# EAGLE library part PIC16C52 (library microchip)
MICROCONTROLLER

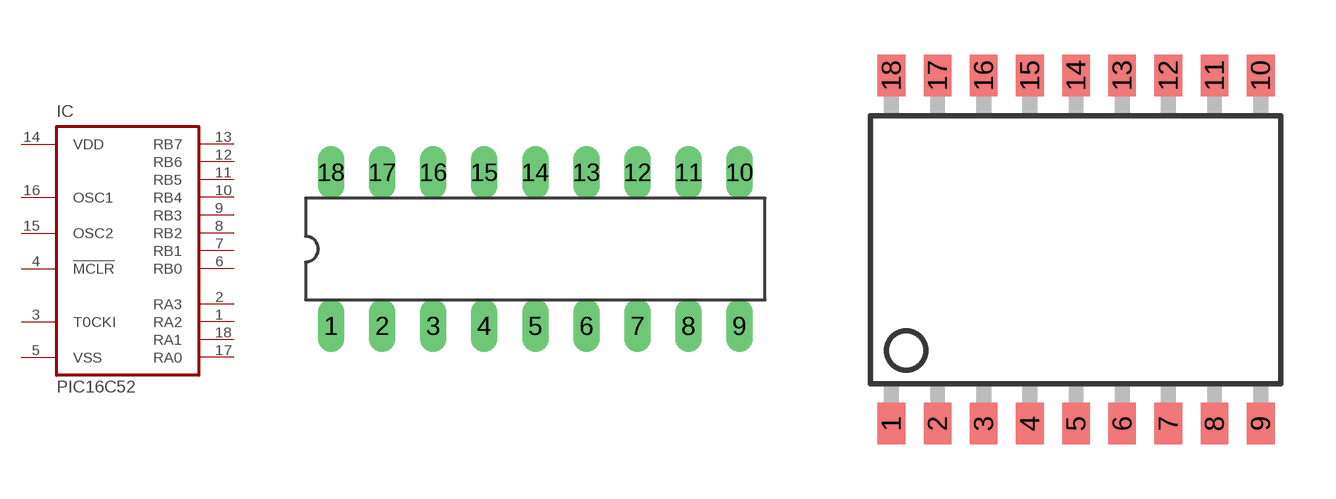
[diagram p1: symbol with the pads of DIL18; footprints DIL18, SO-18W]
Designator prefix IC

## PIC16C52P (OC_FARNELL: unknown; OC_NEWARK: unknown)  [DIL18]
1  RA2
2  RA3
3  T0CKI  in
4  !MCLR  in
5  VSS  pwr
6  RB0
7  RB1
8  RB2
9  RB3
10  RB4
11  RB5
12  RB6
13  RB7
14  VDD  pwr
15  OSC2  out
16  OSC1  in
17  RA0
18  RA1

## PIC16C52JW (OC_FARNELL: unknown; OC_NEWARK: unknown)  [DIL18]
Pads as for DIL18

## PIC16C52SO (OC_FARNELL: unknown; OC_NEWARK: unknown)  [SO-18W]
Pads as for DIL18

## Footprint DIL18 (pad centres in mm)
Dual In Line package type P
drill 0.813 long: 1 -10.16,-3.81; 2 -7.62,-3.81; 3 -5.08,-3.81; 4 -2.54,-3.81; 5 0,-3.81; 6 2.54,-3.81; 7 5.08,-3.81; 8 7.62,-3.81; 9 10.16,-3.81; 10 10.16,3.81; 11 7.62,3.81; 12 5.08,3.81; 13 2.54,3.81; 14 0,3.81; 15 -2.54,3.81; 16 -5.08,3.81; 17 -7.62,3.81; 18 -10.16,3.81

## Footprint SO-18W (pad centres in mm)
Small Outline Wide Plastic Gull Wing 300-mil body, package type SO
smd 0.762 x 1.143: 1 -5.08,-4.788; 2 -3.81,-4.788; 3 -2.54,-4.788; 4 -1.27,-4.788; 5 0,-4.788; 6 1.27,-4.788; 7 2.54,-4.788; 8 3.81,-4.788; 9 5.08,-4.788; 10 5.08,4.788; 11 3.81,4.788; 12 2.54,4.788; 13 1.27,4.788; 14 0,4.788; 15 -1.27,4.788; 16 -2.54,4.788; 17 -3.81,4.788; 18 -5.08,4.788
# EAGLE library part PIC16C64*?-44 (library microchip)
MICROCONTROLLER

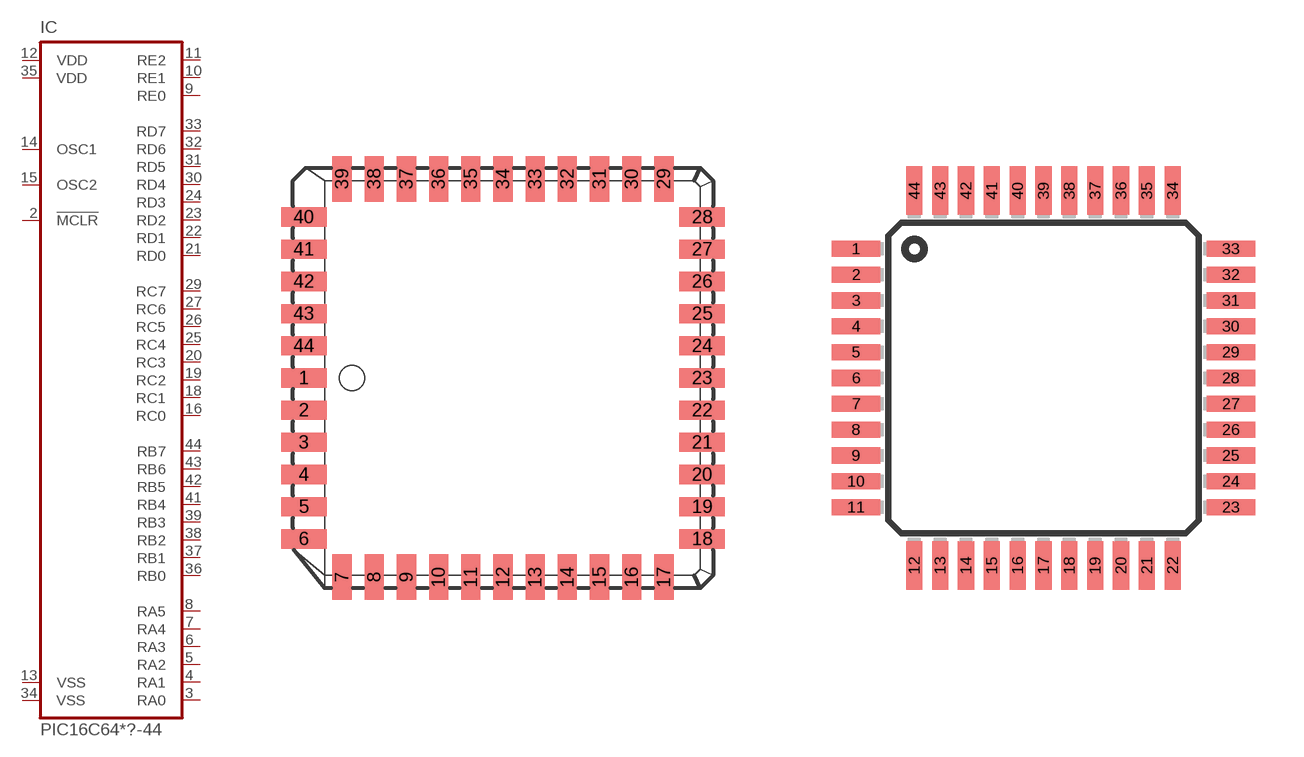
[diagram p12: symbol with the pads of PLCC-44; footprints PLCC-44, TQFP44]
Designator prefix IC

## PIC16C64L-44 (MF: MICROCHIP; MPN: PIC16C64A-20/L; OC_FARNELL: 9759646; OC_NEWARK: 23C4099)  [PLCC-44]
1  NC  nc
2  !MCLR  in
3  RA0
4  RA1
5  RA2
6  RA3
7  RA4
8  RA5
9  RE0
10  RE1
11  RE2
12  VDD  pwr
13  VSS  pwr
14  OSC1  in
15  OSC2  out
16  RC0
17  NC  nc
18  RC1
19  RC2
20  RC3
21  RD0
22  RD1
23  RD2
24  RD3
25  RC4
26  RC5
27  RC6
28  NC  nc
29  RC7
30  RD4
31  RD5
32  RD6
33  RD7
34  VSS  pwr
35  VDD  pwr
36  RB0
37  RB1
38  RB2
39  RB3
40  NC  nc
41  RB4
42  RB5
43  RB6
44  RB7

## PIC16C64PT-44 (OC_FARNELL: unknown; OC_NEWARK: unknown)  [TQFP44]
1  RC7
2  RD4
3  RD5
4  RD6
5  RD7
6  VSS  pwr
7  VDD  pwr
8  RB0
9  RB1
10  RB2
11  RB3
12  NC  nc
13  NC  nc
14  RB4
15  RB5
16  RB6
17  RB7
18  !MCLR  in
19  RA0
20  RA1
21  RA2
22  RA3
23  RA4
24  RA5
25  RE0
26  RE1
27  RE2
28  VDD  pwr
29  VSS  pwr
30  OSC1  in
31  OSC2  out
32  RC0
33  NC  nc
34  NC  nc
35  RC1
36  RC2
37  RC3
38  RD0
39  RD1
40  RD2
41  RD3
42  RC4
43  RC5
44  RC6

## Footprint PLCC-44 (pad centres in mm)
PLASTIC LEADED CHIP CARRIER square, package type L
smd 1.8 x 0.76: 1 -7.86,0; 2 -7.86,-1.27; 3 -7.86,-2.54; 4 -7.86,-3.81; 5 -7.86,-5.08; 6 -7.86,-6.35; 18 7.86,-6.35; 19 7.86,-5.08; 20 7.86,-3.81; 21 7.86,-2.54; 22 7.86,-1.27; 23 7.86,0; 24 7.86,1.27; 25 7.86,2.54; 26 7.86,3.81; 27 7.86,5.08; 28 7.86,6.35; 40 -7.86,6.35; 41 -7.86,5.08; 42 -7.86,3.81; 43 -7.86,2.54; 44 -7.86,1.27
smd 0.76 x 1.8: 7 -6.35,-7.86; 8 -5.08,-7.86; 9 -3.81,-7.86; 10 -2.54,-7.86; 11 -1.27,-7.86; 12 0,-7.86; 13 1.27,-7.86; 14 2.54,-7.86; 15 3.81,-7.86; 16 5.08,-7.86; 17 6.35,-7.86; 29 6.35,7.86; 30 5.08,7.86; 31 3.81,7.86; 32 2.54,7.86; 33 1.27,7.86; 34 0,7.86; 35 -1.27,7.86; 36 -2.54,7.86; 37 -3.81,7.86; 38 -5.08,7.86; 39 -6.35,7.86

## Footprint TQFP44 (pad centres in mm)
Thin Quad Flat Pack package type TQ
smd 1.5 x 0.5: 1 -5.8,4; 2 -5.8,3.2; 3 -5.8,2.4; 4 -5.8,1.6; 5 -5.8,0.8; 6 -5.8,0; 7 -5.8,-0.8; 8 -5.8,-1.6; 9 -5.8,-2.4; 10 -5.8,-3.2; 11 -5.8,-4; 23 5.8,-4; 24 5.8,-3.2; 25 5.8,-2.4; 26 5.8,-1.6; 27 5.8,-0.8; 28 5.8,0; 29 5.8,0.8; 30 5.8,1.6; 31 5.8,2.4; 32 5.8,3.2; 33 5.8,4
smd 0.5 x 1.5: 12 -4,-5.8; 13 -3.2,-5.8; 14 -2.4,-5.8; 15 -1.6,-5.8; 16 -0.8,-5.8; 17 0,-5.8; 18 0.8,-5.8; 19 1.6,-5.8; 20 2.4,-5.8; 21 3.2,-5.8; 22 4,-5.8; 34 4,5.8; 35 3.2,5.8; 36 2.4,5.8; 37 1.6,5.8; 38 0.8,5.8; 39 0,5.8; 40 -0.8,5.8; 41 -1.6,5.8; 42 -2.4,5.8; 43 -3.2,5.8; 44 -4,5.8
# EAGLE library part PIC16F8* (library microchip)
MICROCONTROLLER 8-Bit PIC16F8X Family - CMOS Flash/EEPROM Pin Compatible : PIC16F83, PIC16CR83, PIC16F84A, PIC16CR84 see also PIC16C*

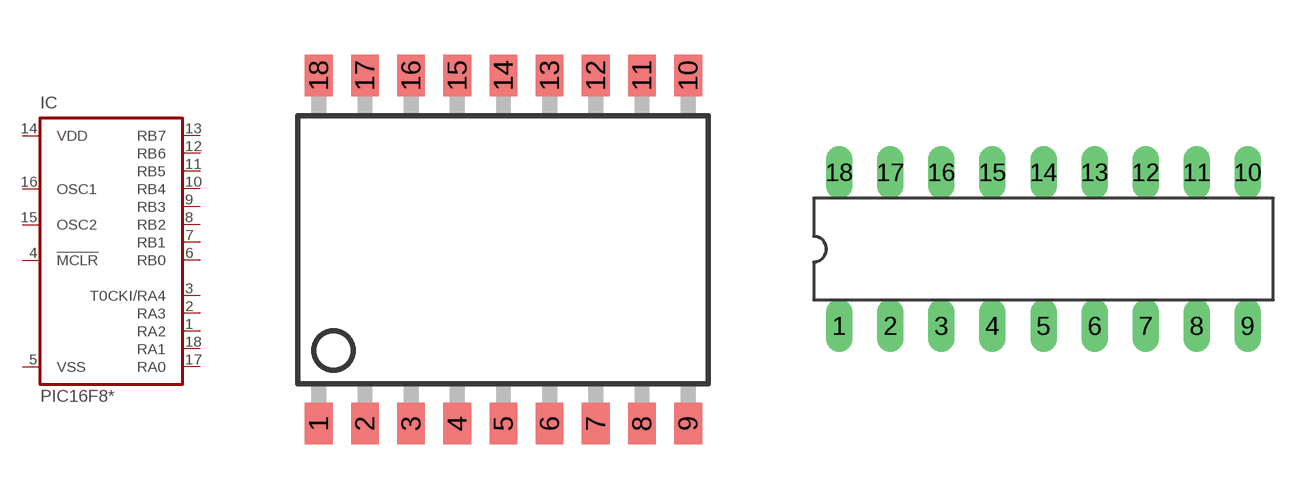
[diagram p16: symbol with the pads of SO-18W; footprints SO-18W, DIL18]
Designator prefix IC

## PIC16F83SO (MF: MICROCHIP; MPN: PIC16F83-04/SO; OC_FARNELL: unknown; OC_NEWARK: 23C4997), PIC16F84ASO (MF: MICROCHIP; MPN: PIC16F84A-04/SO; OC_FARNELL: 9760890; OC_NEWARK: 69K7634)  [SO-18W]
1  RA2
2  RA3
3  T0CKI/RA4
4  !MCLR  in
5  VSS  pwr
6  RB0
7  RB1
8  RB2
9  RB3
10  RB4
11  RB5
12  RB6
13  RB7
14  VDD  pwr
15  OSC2  out
16  OSC1  in
17  RA0
18  RA1

## PIC16F83P (MPN: PIC16F83-04/P; OC_FARNELL: 1084354; OC_NEWARK: 97K7388), PIC16F84AP (MF: MICROCHIP; MPN: PIC16F84A-04I/P; OC_FARNELL: 9760865; OC_NEWARK: 69K7635)  [DIL18]
Pads as for SO-18W

## Footprint SO-18W (pad centres in mm)
Small Outline Wide Plastic Gull Wing 300-mil body, package type SO
smd 0.762 x 1.143: 1 -5.08,-4.788; 2 -3.81,-4.788; 3 -2.54,-4.788; 4 -1.27,-4.788; 5 0,-4.788; 6 1.27,-4.788; 7 2.54,-4.788; 8 3.81,-4.788; 9 5.08,-4.788; 10 5.08,4.788; 11 3.81,4.788; 12 2.54,4.788; 13 1.27,4.788; 14 0,4.788; 15 -1.27,4.788; 16 -2.54,4.788; 17 -3.81,4.788; 18 -5.08,4.788

## Footprint DIL18 (pad centres in mm)
Dual In Line package type P
drill 0.813 long: 1 -10.16,-3.81; 2 -7.62,-3.81; 3 -5.08,-3.81; 4 -2.54,-3.81; 5 0,-3.81; 6 2.54,-3.81; 7 5.08,-3.81; 8 7.62,-3.81; 9 10.16,-3.81; 10 10.16,3.81; 11 7.62,3.81; 12 5.08,3.81; 13 2.54,3.81; 14 0,3.81; 15 -2.54,3.81; 16 -5.08,3.81; 17 -7.62,3.81; 18 -10.16,3.81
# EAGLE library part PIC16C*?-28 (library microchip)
MICROCONTROLLER 8-BitEPROM/ROM-based Pin compatible: PIC16CR62, PIC16C62A, PIC16C63, PIC16CR63 PIC16C66, PIC16C72, PIC16C73A, PIC16C76

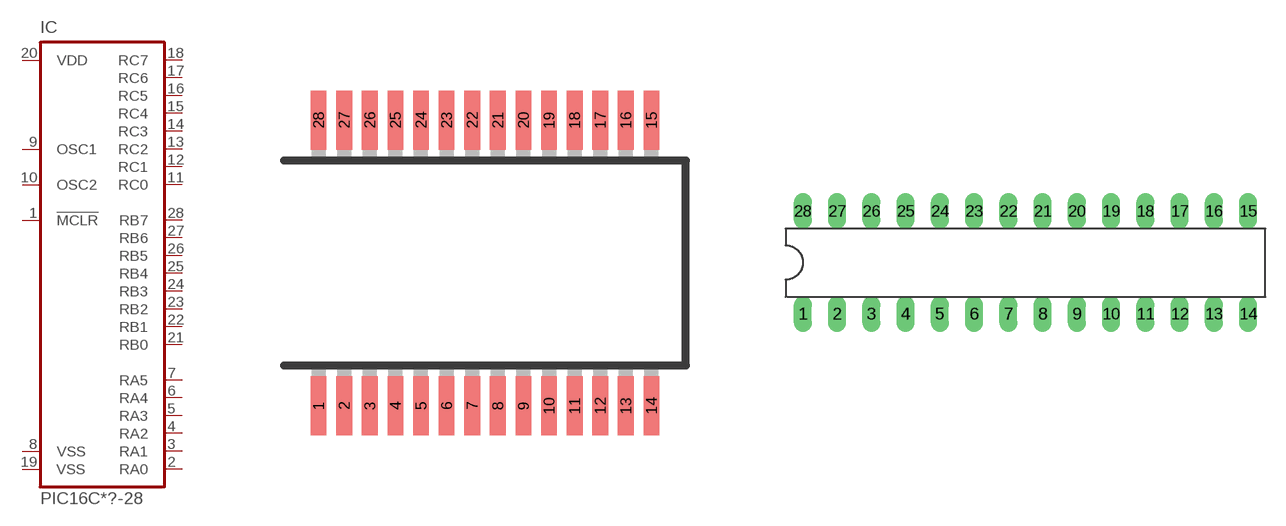
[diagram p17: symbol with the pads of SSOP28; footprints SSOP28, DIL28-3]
Designator prefix IC

## PIC16C62ASS-28 (MF: MICROCHIP; MPN: PIC16C62A-04/SS; OC_FARNELL: unknown; OC_NEWARK: 23C3766), PIC16C63SS-28 (MF: MICROCHIP; MPN: PIC16C63A-04/SS; OC_FARNELL: unknown; OC_NEWARK: 96K3811), PIC16C66SS-28 (OC_FARNELL: unknown; OC_NEWARK: unknown), PIC16C72SS-28 (MF: MICROCHIP; MPN: PIC16C72A-04/SS; OC_FARNELL: unknown; OC_NEWARK: 23C4612), PIC16C73ASS-28 (MPN: PIC16C73B-20I/SS; OC_FARNELL: 1137313; OC_NEWARK: 24M5884), PIC16C76SS-28 (OC_FARNELL: unknown; OC_NEWARK: unknown), PIC16CR62SS-28 (OC_FARNELL: unknown; OC_NEWARK: unknown), PIC16CR63SS-28 (OC_FARNELL: unknown; OC_NEWARK: unknown)  [SSOP28]
1  !MCLR  in
2  RA0
3  RA1
4  RA2
5  RA3
6  RA4
7  RA5
8  VSS  pwr
9  OSC1
10  OSC2
11  RC0
12  RC1
13  RC2
14  RC3
15  RC4
16  RC5
17  RC6
18  RC7
19  VSS  pwr
20  VDD  pwr
21  RB0
22  RB1
23  RB2
24  RB3
25  RB4
26  RB5
27  RB6
28  RB7

## PIC16C62AP-28 (MF: MICROCHIP; MPN: PIC16C62A-10/SP; OC_FARNELL: 9759557; OC_NEWARK: 23C3774), PIC16C63P-28 (MF: MICROCHIP; MPN: PIC16C63-04I/SP; OC_FARNELL: 9759590; OC_NEWARK: 23C4025), PIC16C66P-28 (MF: MICROCHIP; MPN: PIC16C66-04I/SP; OC_FARNELL: 9759735; OC_NEWARK: 23C4276), PIC16C72P-28 (MF: MICROCHIP; MPN: PIC16C72-04/SO; OC_FARNELL: 1196858; OC_NEWARK: 23C4583), PIC16C73AP-28 (MF: MICROCHIP; MPN: PIC16C73A-20I/SP; OC_FARNELL: 1815911; OC_NEWARK: 23C4675), PIC16C76P-28 (MF: MICROCHIP; MPN: PIC16C76-20/SP; OC_FARNELL: 1196859; OC_NEWARK: 12C1934), PIC16CR62P-28 (OC_FARNELL: unknown; OC_NEWARK: unknown), PIC16CR63P-28 (OC_FARNELL: unknown; OC_NEWARK: unknown)  [DIL28-3]
Pads as for SSOP28

## PIC16C62ASO-28 (MF: MICROCHIP; MPN: PIC16C62A-20/SO; OC_FARNELL: 9759573; OC_NEWARK: 23C3782), PIC16C63SO-28 (MPN: PIC16C63-04/SO; OC_FARNELL: 9759581; OC_NEWARK: 97K7237), PIC16C66SO-28 (MPN: PIC16C66-10/SO; OC_FARNELL: 9759727; OC_NEWARK: 97K7254), PIC16C72SO-28 (MF: MICROCHIP; MPN: PIC16C72-04/SO; OC_FARNELL: 9759891; OC_NEWARK: 23C4583), PIC16C73ASO-28 (MPN: PIC16C73A-04/SO; OC_FARNELL: 9759930; OC_NEWARK: 97K7282), PIC16C76SO-28 (MF: MICROCHIP; MPN: PIC16C76-20/SO; OC_FARNELL: unknown; OC_NEWARK: 65K1040), PIC16CR62SO-28 (OC_FARNELL: unknown; OC_NEWARK: unknown), PIC16CR63SO-28 (OC_FARNELL: unknown; OC_NEWARK: unknown)  [SO28W]
Pads as for SSOP28

## PIC16C62PS-28 (MF: MICROCHIP; MPN: PIC16C62B-20/SP; OC_FARNELL: 9759565; OC_NEWARK: 12C1900), PIC16C62APS-28 (MF: MICROCHIP; MPN: PIC16C62A-10/SP; OC_FARNELL: 1818502; OC_NEWARK: 23C3774), PIC16C63PS-28 (MF: MICROCHIP; MPN: PIC16C63-04I/SP; OC_FARNELL: 9759590; OC_NEWARK: 23C4025), PIC16C66PS-28 (MF: MICROCHIP; MPN: PIC16C66-04I/SP; OC_FARNELL: 685999; OC_NEWARK: 23C4276), PIC16C72PS-28 (MF: MICROCHIP; MPN: PIC16C72A-04/SP; OC_FARNELL: 1196858; OC_NEWARK: 12C1924), PIC16C73APS-28 (MF: MICROCHIP; MPN: PIC16C73A-20/SP; OC_FARNELL: 1196850; OC_NEWARK: 69K7069), PIC16C76PS-28 (MF: MICROCHIP; MPN: PIC16C76-04/SP; OC_FARNELL: 1196836; OC_NEWARK: 96K3849), PIC16CR63PS-28 (OC_FARNELL: unknown; OC_NEWARK: unknown)  [DIL28-3]
Pads as for SSOP28

## PIC16C62AJW-28 (MF: MICROCHIP; MPN: PIC16C62A-10/SP; OC_FARNELL: 9759557; OC_NEWARK: 23C3774), PIC16C63JW-28 (MPN: PIC16C63-04/SP; OC_FARNELL: 1084289; OC_NEWARK: 97K7238), PIC16C66JW-28 (MF: MICROCHIP; MPN: PIC16C66/JW; OC_FARNELL: 685999; OC_NEWARK: 96K3820), PIC16C72JW-28 (MF: MICROCHIP; MPN: PIC16C72-20/SP; OC_FARNELL: 1196858; OC_NEWARK: 23C4602), PIC16C73AJW-28 (MPN: PIC16C73A-10/SP; OC_FARNELL: 9759948; OC_NEWARK: 97K7284), PIC16C76JW-28 (MPN: PIC16C76-04/SP; OC_FARNELL: 1196836; OC_NEWARK: 97K7307), PIC16CR62JW-28 (OC_FARNELL: unknown; OC_NEWARK: unknown), PIC16CR63JW-28 (OC_FARNELL: unknown; OC_NEWARK: unknown)  [DIL28-6]
Pads as for SSOP28

## Footprint SSOP28 (pad centres in mm)
Shrink Small Outline Package package type SS
smd 0.4 x 1.5: 1 -4.225,-3.625; 2 -3.575,-3.625; 3 -2.925,-3.625; 4 -2.275,-3.625; 5 -1.625,-3.625; 6 -0.975,-3.625; 7 -0.325,-3.625; 8 0.325,-3.625; 9 0.975,-3.625; 10 1.625,-3.625; 11 2.275,-3.625; 12 2.925,-3.625; 13 3.575,-3.625; 14 4.225,-3.625; 15 4.225,3.625; 16 3.575,3.625; 17 2.925,3.625; 18 2.275,3.625; 19 1.625,3.625; 20 0.975,3.625; 21 0.325,3.625; 22 -0.325,3.625; 23 -0.975,3.625; 24 -1.625,3.625; 25 -2.275,3.625; 26 -2.925,3.625; 27 -3.575,3.625; 28 -4.225,3.625

## Footprint DIL28-3 (pad centres in mm)
Dual In Line package type P
drill 0.813 long: 1 -16.51,-3.81; 2 -13.97,-3.81; 3 -11.43,-3.81; 4 -8.89,-3.81; 5 -6.35,-3.81; 6 -3.81,-3.81; 7 -1.27,-3.81; 8 1.27,-3.81; 9 3.81,-3.81; 10 6.35,-3.81; 11 8.89,-3.81; 12 11.43,-3.81; 13 13.97,-3.81; 14 16.51,-3.81; 15 16.51,3.81; 16 13.97,3.81; 17 11.43,3.81; 18 8.89,3.81; 19 6.35,3.81; 20 3.81,3.81; 21 1.27,3.81; 22 -1.27,3.81; 23 -3.81,3.81; 24 -6.35,3.81; 25 -8.89,3.81; 26 -11.43,3.81; 27 -13.97,3.81; 28 -16.51,3.81

## Footprint SO28W (pad centres in mm)
28-Lead Plastic Small Outline (SO) Wide, 300 mil Body (SOIC) Source: http://ww1.microchip.com/downloads/en/devicedoc/39632c.pdf
smd 0.65 x 1.7: 1 -7.62,-4.78; 2 -6.35,-4.78; 3 -5.08,-4.78; 4 -3.81,-4.78; 5 -2.54,-4.78; 6 -1.27,-4.78; 7 0,-4.78; 8 1.27,-4.78; 9 2.54,-4.78; 10 3.81,-4.78; 11 5.08,-4.78; 12 6.35,-4.78; 13 7.62,-4.78; 14 8.89,-4.78; 15 8.89,4.78; 16 7.62,4.78; 17 6.35,4.78; 18 5.08,4.78; 19 3.81,4.78; 20 2.54,4.78; 21 1.27,4.78; 22 0,4.78; 23 -1.27,4.78; 24 -2.54,4.78; 25 -3.81,4.78; 26 -5.08,4.78; 27 -6.35,4.78; 28 -7.62,4.78

## Footprint DIL28-6 (pad centres in mm)
Dual In Line package type P
drill 0.813 long: 1 -16.51,-7.62; 2 -13.97,-7.62; 3 -11.43,-7.62; 4 -8.89,-7.62; 5 -6.35,-7.62; 6 -3.81,-7.62; 7 -1.27,-7.62; 8 1.27,-7.62; 9 3.81,-7.62; 10 6.35,-7.62; 11 8.89,-7.62; 12 11.43,-7.62; 13 13.97,-7.62; 14 16.51,-7.62; 15 16.51,7.62; 16 13.97,7.62; 17 11.43,7.62; 18 8.89,7.62; 19 6.35,7.62; 20 3.81,7.62; 21 1.27,7.62; 22 -1.27,7.62; 23 -3.81,7.62; 24 -6.35,7.62; 25 -8.89,7.62; 26 -11.43,7.62; 27 -13.97,7.62; 28 -16.51,7.62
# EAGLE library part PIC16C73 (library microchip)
MICROCONTROLLER EPROM/ROM-based

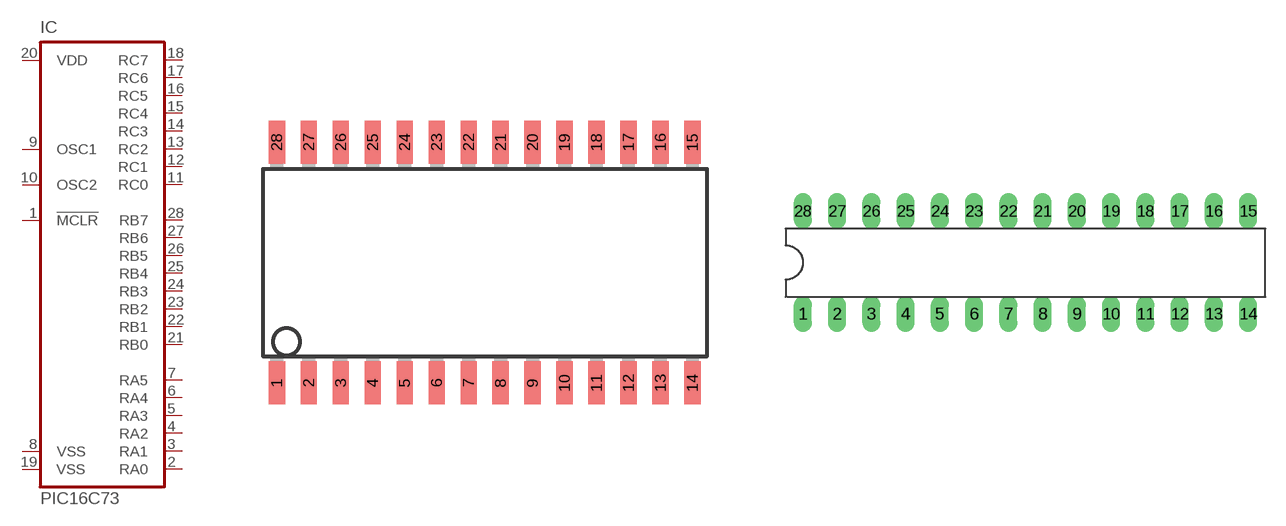
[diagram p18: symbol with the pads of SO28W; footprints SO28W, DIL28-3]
Designator prefix IC

## PIC16C73SO (MF: MICROCHIP; MPN: PIC16C73B-20/SO; OC_FARNELL: 9759999; OC_NEWARK: 12C1926)  [SO28W]
1  !MCLR  in
2  RA0
3  RA1
4  RA2
5  RA3
6  RA4
7  RA5
8  VSS  pwr
9  OSC1
10  OSC2
11  RC0
12  RC1
13  RC2
14  RC3
15  RC4
16  RC5
17  RC6
18  RC7
19  VSS  pwr
20  VDD  pwr
21  RB0
22  RB1
23  RB2
24  RB3
25  RB4
26  RB5
27  RB6
28  RB7

## PIC16C73P (MF: MICROCHIP; MPN: PIC16C73B-04I/SP; OC_FARNELL: 9759980; OC_NEWARK: 96K3842)  [DIL28-3]
Pads as for SO28W

## Footprint SO28W (pad centres in mm)
28-Lead Plastic Small Outline (SO) Wide, 300 mil Body (SOIC) Source: http://ww1.microchip.com/downloads/en/devicedoc/39632c.pdf
smd 0.65 x 1.7: 1 -7.62,-4.78; 2 -6.35,-4.78; 3 -5.08,-4.78; 4 -3.81,-4.78; 5 -2.54,-4.78; 6 -1.27,-4.78; 7 0,-4.78; 8 1.27,-4.78; 9 2.54,-4.78; 10 3.81,-4.78; 11 5.08,-4.78; 12 6.35,-4.78; 13 7.62,-4.78; 14 8.89,-4.78; 15 8.89,4.78; 16 7.62,4.78; 17 6.35,4.78; 18 5.08,4.78; 19 3.81,4.78; 20 2.54,4.78; 21 1.27,4.78; 22 0,4.78; 23 -1.27,4.78; 24 -2.54,4.78; 25 -3.81,4.78; 26 -5.08,4.78; 27 -6.35,4.78; 28 -7.62,4.78

## Footprint DIL28-3 (pad centres in mm)
Dual In Line package type P
drill 0.813 long: 1 -16.51,-3.81; 2 -13.97,-3.81; 3 -11.43,-3.81; 4 -8.89,-3.81; 5 -6.35,-3.81; 6 -3.81,-3.81; 7 -1.27,-3.81; 8 1.27,-3.81; 9 3.81,-3.81; 10 6.35,-3.81; 11 8.89,-3.81; 12 11.43,-3.81; 13 13.97,-3.81; 14 16.51,-3.81; 15 16.51,3.81; 16 13.97,3.81; 17 11.43,3.81; 18 8.89,3.81; 19 6.35,3.81; 20 3.81,3.81; 21 1.27,3.81; 22 -1.27,3.81; 23 -3.81,3.81; 24 -6.35,3.81; 25 -8.89,3.81; 26 -11.43,3.81; 27 -13.97,3.81; 28 -16.51,3.81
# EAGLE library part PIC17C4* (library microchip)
MICROCONTROLLER EPROM-based

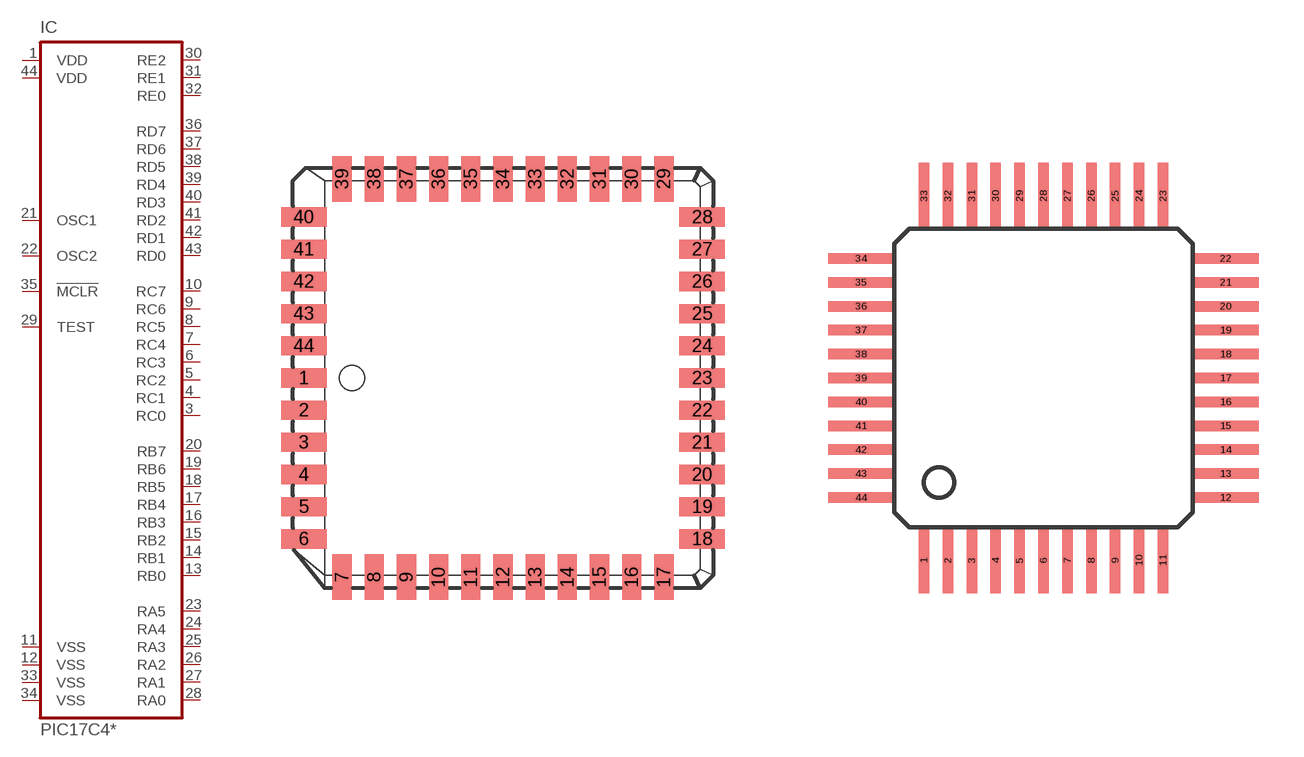
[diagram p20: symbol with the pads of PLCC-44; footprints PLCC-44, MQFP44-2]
Designator prefix IC

## PIC17C42L (MF: MICROCHIP; MPN: PIC17C42A-25I/L; OC_FARNELL: unknown; OC_NEWARK: 23C5787), PIC17C43L (MF: MICROCHIP; MPN: PIC17C43-16/L; OC_FARNELL: 9761861; OC_NEWARK: 23C5830), PIC17C44L (MF: MICROCHIP; MPN: PIC17C44-16/L; OC_FARNELL: 9761918; OC_NEWARK: 69K7642)  [PLCC-44]
1  VDD  pwr
2  NC  nc
3  RC0
4  RC1
5  RC2
6  RC3
7  RC4
8  RC5
9  RC6
10  RC7
11  VSS  pwr
12  VSS  pwr
13  RB0
14  RB1
15  RB2
16  RB3
17  RB4
18  RB5
19  RB6
20  RB7
21  OSC1  in
22  OSC2  out
23  RA5
24  RA4
25  RA3
26  RA2
27  RA1
28  RA0
29  TEST  in
30  RE2
31  RE1
32  RE0
33  VSS  pwr
34  VSS  pwr
35  !MCLR  in
36  RD7
37  RD6
38  RD5
39  RD4
40  RD3
41  RD2
42  RD1
43  RD0
44  VDD  pwr

## PIC17C42PQ (MF: MICROCHIP; MPN: PIC17C42A-16/PQ; OC_FARNELL: unknown; OC_NEWARK: 23C5769), PIC17C43PQ (MF: MICROCHIP; MPN: PIC17C43-33/PT; OC_FARNELL: unknown; OC_NEWARK: 23C5857), PIC17C44PQ (OC_FARNELL: unknown; OC_NEWARK: unknown)  [MQFP44-2]
1  TEST  in
2  RE2
3  RE1
4  RE0
5  VSS  pwr
6  VSS  pwr
7  !MCLR  in
8  RD7
9  RD6
10  RD5
11  RD4
12  RD3
13  RD2
14  RD1
15  RD0
16  VDD  pwr
17  VDD  pwr
18  NC  nc
19  RC0
20  RC1
21  RC2
22  RC3
23  RC4
24  RC5
25  RC6
26  RC7
27  VSS  pwr
28  VSS  pwr
29  RB0
30  RB1
31  RB2
32  RB3
33  RB4
34  RB5
35  RB6
36  RB7
37  OSC1  in
38  OSC2  out
39  RA5
40  RA4
41  RA3
42  RA2
43  RA1
44  RA0

## Footprint PLCC-44 (pad centres in mm)
PLASTIC LEADED CHIP CARRIER square, package type L
smd 1.8 x 0.76: 1 -7.86,0; 2 -7.86,-1.27; 3 -7.86,-2.54; 4 -7.86,-3.81; 5 -7.86,-5.08; 6 -7.86,-6.35; 18 7.86,-6.35; 19 7.86,-5.08; 20 7.86,-3.81; 21 7.86,-2.54; 22 7.86,-1.27; 23 7.86,0; 24 7.86,1.27; 25 7.86,2.54; 26 7.86,3.81; 27 7.86,5.08; 28 7.86,6.35; 40 -7.86,6.35; 41 -7.86,5.08; 42 -7.86,3.81; 43 -7.86,2.54; 44 -7.86,1.27
smd 0.76 x 1.8: 7 -6.35,-7.86; 8 -5.08,-7.86; 9 -3.81,-7.86; 10 -2.54,-7.86; 11 -1.27,-7.86; 12 0,-7.86; 13 1.27,-7.86; 14 2.54,-7.86; 15 3.81,-7.86; 16 5.08,-7.86; 17 6.35,-7.86; 29 6.35,7.86; 30 5.08,7.86; 31 3.81,7.86; 32 2.54,7.86; 33 1.27,7.86; 34 0,7.86; 35 -1.27,7.86; 36 -2.54,7.86; 37 -3.81,7.86; 38 -5.08,7.86; 39 -6.35,7.86

## Footprint MQFP44-2 (pad centres in mm)
Plastic Metric Quad Flat Pack package type PQ
smd 0.35 x 2.2: 1 -4,-6.1; 2 -3.2,-6.1; 3 -2.4,-6.1; 4 -1.6,-6.1; 5 -0.8,-6.1; 6 0,-6.1; 7 0.8,-6.1; 8 1.6,-6.1; 9 2.4,-6.1; 10 3.2,-6.1; 11 4,-6.1; 23 4,6.1; 24 3.2,6.1; 25 2.4,6.1; 26 1.6,6.1; 27 0.8,6.1; 28 0,6.1; 29 -0.8,6.1; 30 -1.6,6.1; 31 -2.4,6.1; 32 -3.2,6.1; 33 -4,6.1
smd 2.2 x 0.35: 12 6.1,-4; 13 6.1,-3.2; 14 6.1,-2.4; 15 6.1,-1.6; 16 6.1,-0.8; 17 6.1,0; 18 6.1,0.8; 19 6.1,1.6; 20 6.1,2.4; 21 6.1,3.2; 22 6.1,4; 34 -6.1,4; 35 -6.1,3.2; 36 -6.1,2.4; 37 -6.1,1.6; 38 -6.1,0.8; 39 -6.1,0; 40 -6.1,-0.8; 41 -6.1,-1.6; 42 -6.1,-2.4; 43 -6.1,-3.2; 44 -6.1,-4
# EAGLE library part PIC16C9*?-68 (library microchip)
MICROCONTROLLER with LCD driver

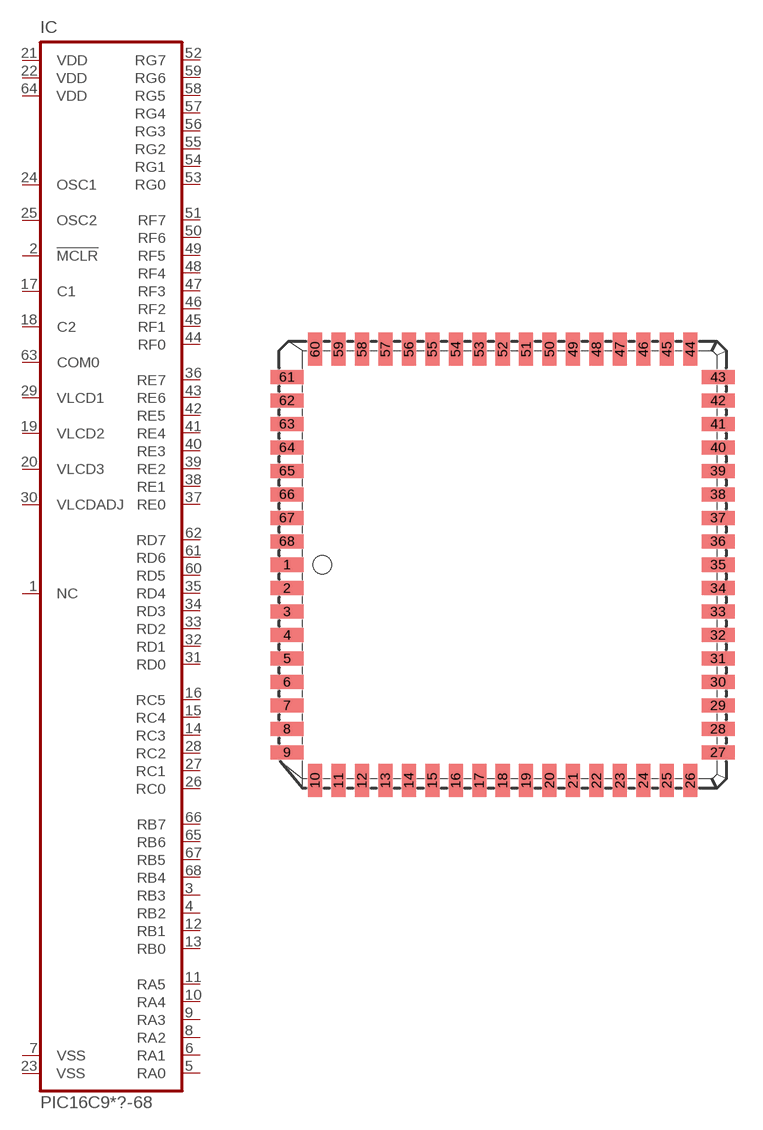
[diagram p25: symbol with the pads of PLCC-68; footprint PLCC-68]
Designator prefix IC

## PIC16C923L-68 (MF: MICROCHIP; MPN: PIC16C923-04/L; OC_FARNELL: 1196843; OC_NEWARK: 23C4927), PIC16C924L-68 (MF: MICROCHIP; MPN: PIC16C924-08I/L; OC_FARNELL: unknown; OC_NEWARK: 23C4949)  [PLCC-68]
1  NC  nc
2  !MCLR  in
3  RB3
4  RB2
5  RA0
6  RA1
7  VSS  pwr
8  RA2
9  RA3
10  RA4
11  RA5
12  RB1
13  RB0
14  RC3
15  RC4
16  RC5
17  C1  in
18  C2  in
19  VLCD2  in
20  VLCD3  in
21  VDD  pwr
22  VDD  pwr
23  VSS  pwr
24  OSC1  in
25  OSC2  out
26  RC0
27  RC1
28  RC2
29  VLCD1  in
30  VLCDADJ  in
31  RD0
32  RD1
33  RD2
34  RD3
35  RD4
36  RE7
37  RE0
38  RE1
39  RE2
40  RE3
41  RE4
42  RE5
43  RE6
44  RF0
45  RF1
46  RF2
47  RF3
48  RF4
49  RF5
50  RF6
51  RF7
52  RG7
53  RG0
54  RG1
55  RG2
56  RG3
57  RG4
58  RG5
59  RG6
60  RD5
61  RD6
62  RD7
63  COM0  out
64  VDD  pwr
65  RB6
66  RB7
67  RB5
68  RB4

## Footprint PLCC-68 (pad centres in mm)
PLASTIC LEADED CHIP CARRIER square, package type L
smd 1.8 x 0.76: 1 -11.67,0; 2 -11.67,-1.27; 3 -11.67,-2.54; 4 -11.67,-3.81; 5 -11.67,-5.08; 6 -11.67,-6.35; 7 -11.67,-7.62; 8 -11.67,-8.89; 9 -11.67,-10.16; 27 11.67,-10.16; 28 11.67,-8.89; 29 11.67,-7.62; 30 11.67,-6.35; 31 11.67,-5.08; 32 11.67,-3.81; 33 11.67,-2.54; 34 11.67,-1.27; 35 11.67,0; 36 11.67,1.27; 37 11.67,2.54; 38 11.67,3.81; 39 11.67,5.08; 40 11.67,6.35; 41 11.67,7.62; 42 11.67,8.89; 43 11.67,10.16; 61 -11.67,10.16; 62 -11.67,8.89; 63 -11.67,7.62; 64 -11.67,6.35; 65 -11.67,5.08; 66 -11.67,3.81; 67 -11.67,2.54; 68 -11.67,1.27
smd 0.76 x 1.8: 10 -10.16,-11.67; 11 -8.89,-11.67; 12 -7.62,-11.67; 13 -6.35,-11.67; 14 -5.08,-11.67; 15 -3.81,-11.67; 16 -2.54,-11.67; 17 -1.27,-11.67; 18 0,-11.67; 19 1.27,-11.67; 20 2.54,-11.67; 21 3.81,-11.67; 22 5.08,-11.67; 23 6.35,-11.67; 24 7.62,-11.67; 25 8.89,-11.67; 26 10.16,-11.67; 44 10.16,11.67; 45 8.89,11.67; 46 7.62,11.67; 47 6.35,11.67; 48 5.08,11.67; 49 3.81,11.67; 50 2.54,11.67; 51 1.27,11.67; 52 0,11.67; 53 -1.27,11.67; 54 -2.54,11.67; 55 -3.81,11.67; 56 -5.08,11.67; 57 -6.35,11.67; 58 -7.62,11.67; 59 -8.89,11.67; 60 -10.16,11.67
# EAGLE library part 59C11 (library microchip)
Serial EEPROM 1 K, 5.0 V, CMOS

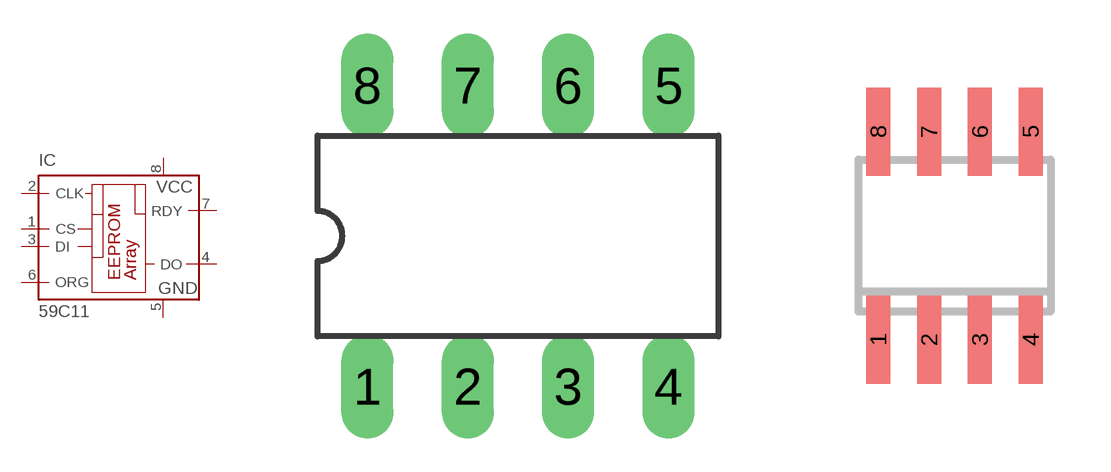
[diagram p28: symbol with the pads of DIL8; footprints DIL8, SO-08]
Designator prefix IC

## 59C11P (OC_FARNELL: unknown; OC_NEWARK: unknown)  [DIL8]
1  CS  in
2  CLK  in
3  DI  in
4  DO  hiz
5  GND  pwr
6  ORG  in
7  RDY  out
8  VCC  pwr

## 59C11SN (OC_FARNELL: unknown; OC_NEWARK: unknown)  [SO-08]
Pads as for DIL8

## 59C11SM (OC_FARNELL: unknown; OC_NEWARK: unknown)  [SO-08M]
Pads as for DIL8

## Footprint DIL8 (pad centres in mm)
Dual In Line package type P
drill 0.813 long: 1 -3.81,-3.81; 2 -1.27,-3.81; 3 1.27,-3.81; 4 3.81,-3.81; 5 3.81,3.81; 6 1.27,3.81; 7 -1.27,3.81; 8 -3.81,3.81

## Footprint SO-08 (pad centres in mm)
Small Outline Narrow Plastic Gull Wing 150-mil body, package type SN
smd 0.6 x 2.2: 1 -1.905,-2.6; 2 -0.635,-2.6; 3 0.635,-2.6; 4 1.905,-2.6; 5 1.905,2.6; 6 0.635,2.6; 7 -0.635,2.6; 8 -1.905,2.6

## Footprint SO-08M (pad centres in mm)
Small Outline Medium Plastic Gull Wing 207-mil body, package type SM
smd 0.6 x 2.2: 1 -1.905,-3.33; 2 -0.635,-3.33; 3 0.635,-3.33; 4 1.905,-3.33; 5 1.905,3.33; 6 0.635,3.33; 7 -0.635,3.33; 8 -1.905,3.33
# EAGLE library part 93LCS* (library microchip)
EEPROM 2 K/4 K, 2.5 V Microwire with software write protect

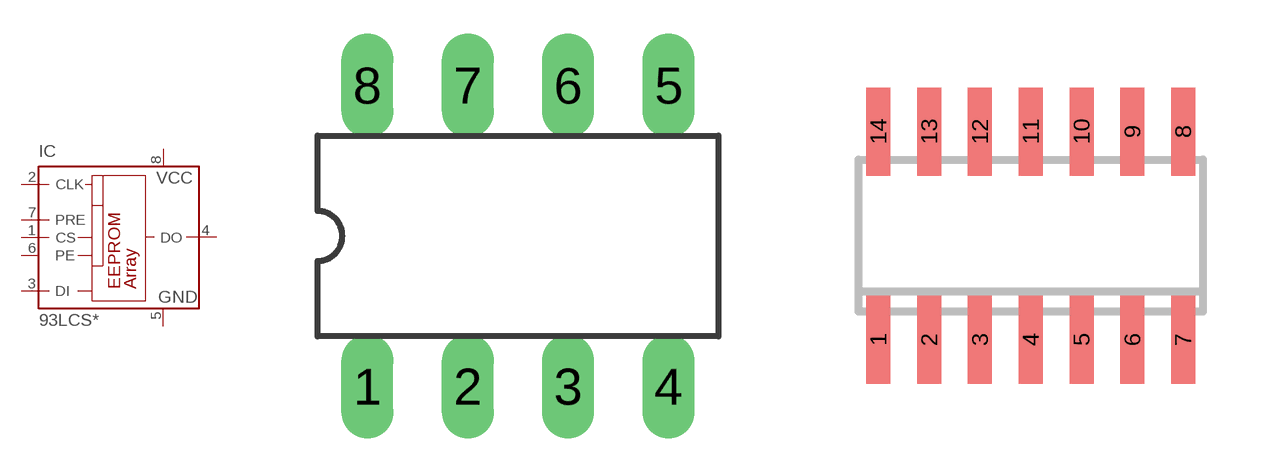
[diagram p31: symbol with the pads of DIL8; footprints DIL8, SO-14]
Designator prefix IC

## 93LCS56P (OC_FARNELL: unknown; OC_NEWARK: unknown), 93LCS66P (OC_FARNELL: unknown; OC_NEWARK: unknown)  [DIL8]
1  CS  in
2  CLK  in
3  DI  in
4  DO  hiz
5  GND  pwr
6  PE  in
7  PRE  in
8  VCC  pwr

## 93LCS56SL (OC_FARNELL: unknown; OC_NEWARK: unknown), 93LCS66SL (OC_FARNELL: unknown; OC_NEWARK: unknown)  [SO-14]
2  CS  in
3  CLK  in
5  DI  in
6  DO  hiz
9  GND  pwr
10  PE  in
12  PRE  in
13  VCC  pwr

## 93LCS56SM (OC_FARNELL: unknown; OC_NEWARK: unknown), 93LCS66SM (OC_FARNELL: unknown; OC_NEWARK: unknown)  [SO-08M]
Pads as for DIL8

## 93LCS56SN (OC_FARNELL: unknown; OC_NEWARK: unknown), 93LCS66SN (OC_FARNELL: unknown; OC_NEWARK: unknown)  [SO-08]
Pads as for DIL8

## Footprint DIL8 (pad centres in mm)
Dual In Line package type P
drill 0.813 long: 1 -3.81,-3.81; 2 -1.27,-3.81; 3 1.27,-3.81; 4 3.81,-3.81; 5 3.81,3.81; 6 1.27,3.81; 7 -1.27,3.81; 8 -3.81,3.81

## Footprint SO-14 (pad centres in mm)
Small Outline Narrow Plastic Gull Wing 150-mil body, package type SL
smd 0.6 x 2.2: 1 -3.81,-2.6; 2 -2.54,-2.6; 3 -1.27,-2.6; 4 0,-2.6; 5 1.27,-2.6; 6 2.54,-2.6; 7 3.81,-2.6; 8 3.81,2.6; 9 2.54,2.6; 10 1.27,2.6; 11 0,2.6; 12 -1.27,2.6; 13 -2.54,2.6; 14 -3.81,2.6

## Footprint SO-08M (pad centres in mm)
Small Outline Medium Plastic Gull Wing 207-mil body, package type SM
smd 0.6 x 2.2: 1 -1.905,-3.33; 2 -0.635,-3.33; 3 0.635,-3.33; 4 1.905,-3.33; 5 1.905,3.33; 6 0.635,3.33; 7 -0.635,3.33; 8 -1.905,3.33

## Footprint SO-08 (pad centres in mm)
Small Outline Narrow Plastic Gull Wing 150-mil body, package type SN
smd 0.6 x 2.2: 1 -1.905,-2.6; 2 -0.635,-2.6; 3 0.635,-2.6; 4 1.905,-2.6; 5 1.905,2.6; 6 0.635,2.6; 7 -0.635,2.6; 8 -1.905,2.6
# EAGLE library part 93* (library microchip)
Serial EPROM 1 K/2 K/4 K, low voltage, Microwire

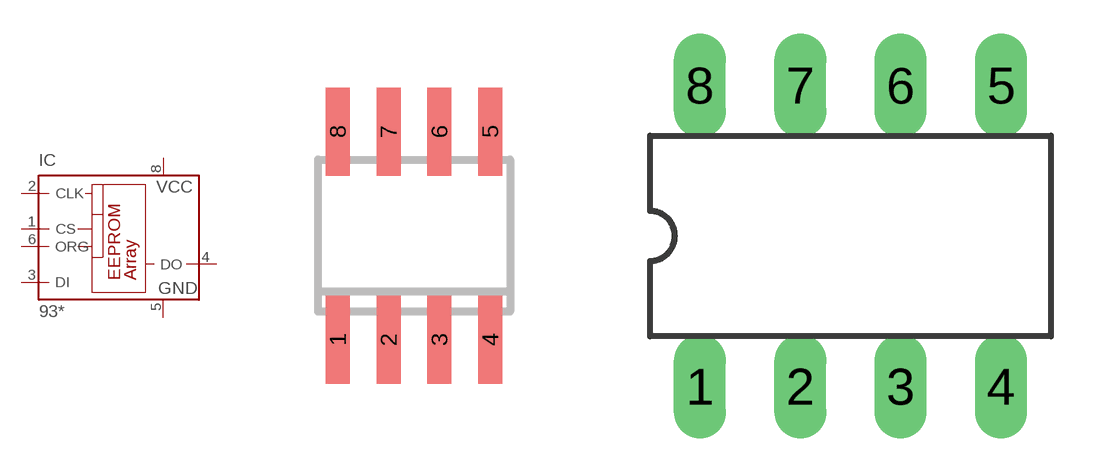
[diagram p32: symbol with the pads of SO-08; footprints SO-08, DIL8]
Designator prefix IC

## 93AA46SN (MF: MICROCHIP; MPN: 93AA46/SN; OC_FARNELL: 1331414; OC_NEWARK: 96K4100), 93AA56SN (MF: MICROCHIP; MPN: 93AA56/SN; OC_FARNELL: 1816074; OC_NEWARK: 92C7564), 93AA66SN (MF: MICROCHIP; MPN: 93AA66C-I/SN; OC_FARNELL: 1331441; OC_NEWARK: 30H4582), 93LC45SN (OC_FARNELL: unknown; OC_NEWARK: unknown), 93LC46SN (MF: MICROCHIP; MPN: 93LC46/SN; OC_FARNELL: 9758194; OC_NEWARK: 12C2030), 93LC66SN (MF: MICROCHIP; MPN: 93LC66/SN; OC_FARNELL: 1296586; OC_NEWARK: 65K1154)  [SO-08]
1  CS  in
2  CLK  in
3  DI  in
4  DO  hiz
5  GND  pwr
6  ORG  in
7  NU  pas
8  VCC  pwr

## 93AA46P (MF: MICROCHIP; MPN: 93AA46/P; OC_FARNELL: 1331412; OC_NEWARK: 96K4099), 93AA56P (MF: MICROCHIP; MPN: 93AA56C-I/P; OC_FARNELL: 1331421; OC_NEWARK: 30H4522), 93AA66P (MF: MICROCHIP; MPN: 93AA66/P; OC_FARNELL: 1331440; OC_NEWARK: 92C7573), 93LC46P (MF: MICROCHIP; MPN: 93LC46/P; OC_FARNELL: 1212720; OC_NEWARK: 33C3013), 93LC56P (MF: MICROCHIP; MPN: 93LC56/P; OC_FARNELL: 1556157; OC_NEWARK: 96K4105), 93LC66P (MF: MICROCHIP; MPN: 93LC66/P; OC_FARNELL: 1556169; OC_NEWARK: 62K2086)  [DIL8]
Pads as for SO-08

## 93AA46SM (MF: MICROCHIP; MPN: 93AA46A-I/SN; OC_FARNELL: 1331414; OC_NEWARK: 96K4101), 93AA56SM (MF: MICROCHIP; MPN: 93AA56/SN; OC_FARNELL: 1331418; OC_NEWARK: 92C7564), 93AA66SM (MF: MICROCHIP; MPN: 93AA66C-I/SN; OC_FARNELL: 1331432; OC_NEWARK: 30H4582), 93LC46SM (MF: MICROCHIP; MPN: 93LC46B/SN; OC_FARNELL: 1084341; OC_NEWARK: 65K1153), 93LC56SM (MF: MICROCHIP; MPN: 93LC56T/SN; OC_FARNELL: 9758240; OC_NEWARK: 92C7699), 93LC66SM (MF: MICROCHIP; MPN: 93LC66/SN; OC_FARNELL: 1296586; OC_NEWARK: 65K1154)  [SO-08M]
Pads as for SO-08

## 93LC46ST (MF: MICROCHIP; MPN: 93LC46C-I/ST; OC_FARNELL: 1817225; OC_NEWARK: 30H4716), 93LC56ST (MF: MICROCHIP; MPN: 93LC56B-I/ST; OC_FARNELL: unknown; OC_NEWARK: 92C7687), 93LC66ST (MF: MICROCHIP; MPN: 93LC66C-I/ST; OC_FARNELL: 1846729; OC_NEWARK: 30H4846)  [TSSOP8]
Pads as for SO-08

## Footprint SO-08 (pad centres in mm)
Small Outline Narrow Plastic Gull Wing 150-mil body, package type SN
smd 0.6 x 2.2: 1 -1.905,-2.6; 2 -0.635,-2.6; 3 0.635,-2.6; 4 1.905,-2.6; 5 1.905,2.6; 6 0.635,2.6; 7 -0.635,2.6; 8 -1.905,2.6

## Footprint DIL8 (pad centres in mm)
Dual In Line package type P
drill 0.813 long: 1 -3.81,-3.81; 2 -1.27,-3.81; 3 1.27,-3.81; 4 3.81,-3.81; 5 3.81,3.81; 6 1.27,3.81; 7 -1.27,3.81; 8 -3.81,3.81

## Footprint SO-08M (pad centres in mm)
Small Outline Medium Plastic Gull Wing 207-mil body, package type SM
smd 0.6 x 2.2: 1 -1.905,-3.33; 2 -0.635,-3.33; 3 0.635,-3.33; 4 1.905,-3.33; 5 1.905,3.33; 6 0.635,3.33; 7 -0.635,3.33; 8 -1.905,3.33

## Footprint TSSOP8 (pad centres in mm)
Thin Shrink Small Outline Package package type ST
smd 0.35 x 1.2: 1 -0.975,-2.925; 2 -0.325,-2.925; 3 0.325,-2.925; 4 0.975,-2.925; 5 0.975,2.925; 6 0.325,2.925; 7 -0.325,2.925; 8 -0.975,2.925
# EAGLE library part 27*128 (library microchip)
CMOS EPROM 128 K (16 K x 8)

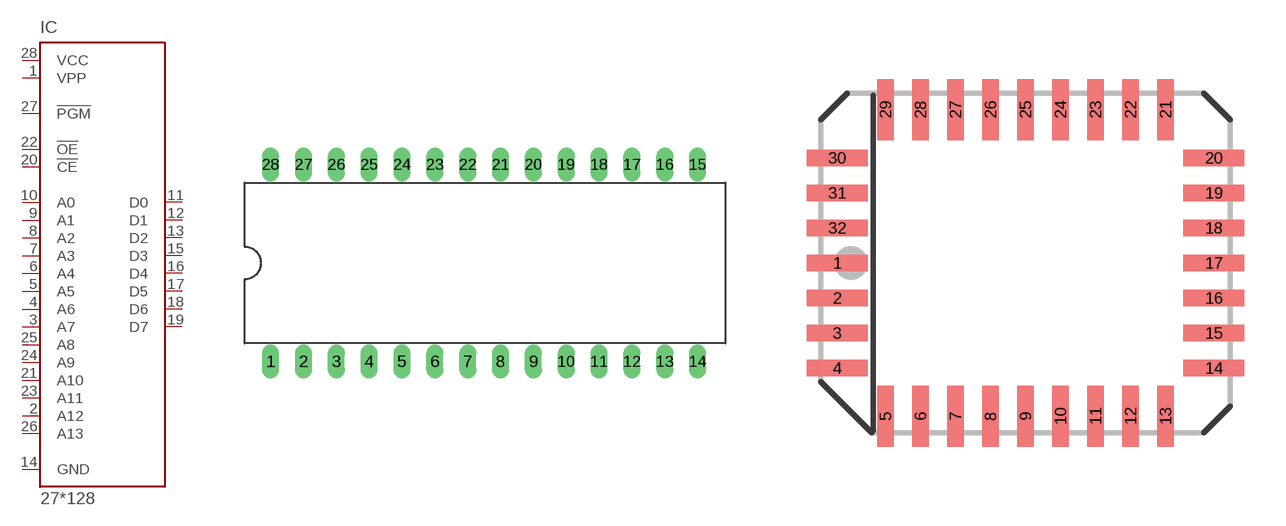
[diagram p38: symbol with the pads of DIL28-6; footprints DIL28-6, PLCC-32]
Designator prefix IC

## 27C128P (OC_FARNELL: unknown; OC_NEWARK: unknown)  [DIL28-6]
1  VPP  in
2  A12  in
3  A7  in
4  A6  in
5  A5  in
6  A4  in
7  A3  in
8  A2  in
9  A1  in
10  A0  in
11  D0  hiz
12  D1  hiz
13  D2  hiz
14  GND  pwr
15  D3  hiz
16  D4  hiz
17  D5  hiz
18  D6  hiz
19  D7  hiz
20  !CE  in
21  A10  in
22  !OE  in
23  A11  in
24  A9  in
25  A8  in
26  A13  in
27  !PGM  pas
28  VCC  pwr

## 27C128L (OC_FARNELL: unknown; OC_NEWARK: unknown)  [PLCC-32]
2  VPP  in
3  A12  in
4  A7  in
5  A6  in
6  A5  in
7  A4  in
8  A3  in
9  A2  in
10  A1  in
11  A0  in
13  D0  hiz
14  D1  hiz
15  D2  hiz
16  GND  pwr
18  D3  hiz
19  D4  hiz
20  D5  hiz
21  D6  hiz
22  D7  hiz
23  !CE  in
24  A10  in
25  !OE  in
27  A11  in
28  A9  in
29  A8  in
30  A13  in
31  !PGM  pas
32  VCC  pwr

## 27C128TS (OC_FARNELL: unknown; OC_NEWARK: unknown), 27LV128TS (OC_FARNELL: unknown; OC_NEWARK: unknown)  [TSOP28]
1  !OE  in
2  A11  in
3  A9  in
4  A8  in
5  A13  in
6  !PGM  pas
7  VCC  pwr
8  VPP  in
9  A12  in
10  A7  in
11  A6  in
12  A5  in
13  A4  in
14  A3  in
15  A2  in
16  A1  in
17  A0  in
18  D0  hiz
19  D1  hiz
20  D2  hiz
21  GND  pwr
22  D3  hiz
23  D4  hiz
24  D5  hiz
25  D6  hiz
26  D7  hiz
27  !CE  in
28  A10  in

## Footprint DIL28-6 (pad centres in mm)
Dual In Line package type P
drill 0.813 long: 1 -16.51,-7.62; 2 -13.97,-7.62; 3 -11.43,-7.62; 4 -8.89,-7.62; 5 -6.35,-7.62; 6 -3.81,-7.62; 7 -1.27,-7.62; 8 1.27,-7.62; 9 3.81,-7.62; 10 6.35,-7.62; 11 8.89,-7.62; 12 11.43,-7.62; 13 13.97,-7.62; 14 16.51,-7.62; 15 16.51,7.62; 16 13.97,7.62; 17 11.43,7.62; 18 8.89,7.62; 19 6.35,7.62; 20 3.81,7.62; 21 1.27,7.62; 22 -1.27,7.62; 23 -3.81,7.62; 24 -6.35,7.62; 25 -8.89,7.62; 26 -11.43,7.62; 27 -13.97,7.62; 28 -16.51,7.62

## Footprint PLCC-32 (pad centres in mm)
PLASTIC LEADED CHIP CARRIER rectangle, package type L
smd 2.2 x 0.6: 1 -6.83,0; 2 -6.83,-1.27; 3 -6.83,-2.54; 4 -6.83,-3.81; 14 6.83,-3.81; 15 6.83,-2.54; 16 6.83,-1.27; 17 6.83,0; 18 6.83,1.27; 19 6.83,2.54; 20 6.83,3.81; 30 -6.83,3.81; 31 -6.83,2.54; 32 -6.83,1.27
smd 0.6 x 2.2: 5 -5.08,-5.56; 6 -3.81,-5.56; 7 -2.54,-5.56; 8 -1.27,-5.56; 9 0,-5.56; 10 1.27,-5.56; 11 2.54,-5.56; 12 3.81,-5.56; 13 5.08,-5.56; 21 5.08,5.56; 22 3.81,5.56; 23 2.54,5.56; 24 1.27,5.56; 25 0,5.56; 26 -1.27,5.56; 27 -2.54,5.56; 28 -3.81,5.56; 29 -5.08,5.56

## Footprint TSOP28 (pad centres in mm)
Thin Small Outline Package Gull Wing type I, package type TS
smd 0.3 x 1: 1 -3.75,-9.7; 2 -3.25,-9.7; 3 -2.75,-9.7; 4 -2.25,-9.7; 5 -1.75,-9.7; 6 -1.25,-9.7; 7 -0.75,-9.7; 8 0.75,-9.7; 9 1.25,-9.7; 10 1.75,-9.7; 11 2.25,-9.7; 12 2.75,-9.7; 13 3.25,-9.7; 14 3.75,-9.7; 15 3.75,9.7; 16 3.25,9.7; 17 2.75,9.7; 18 2.25,9.7; 19 1.75,9.7; 20 1.25,9.7; 21 0.75,9.7; 22 -0.75,9.7; 23 -1.25,9.7; 24 -1.75,9.7; 25 -2.25,9.7; 26 -2.75,9.7; 27 -3.25,9.7; 28 -3.75,9.7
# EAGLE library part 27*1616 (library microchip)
EPROM Obsolete/EOL

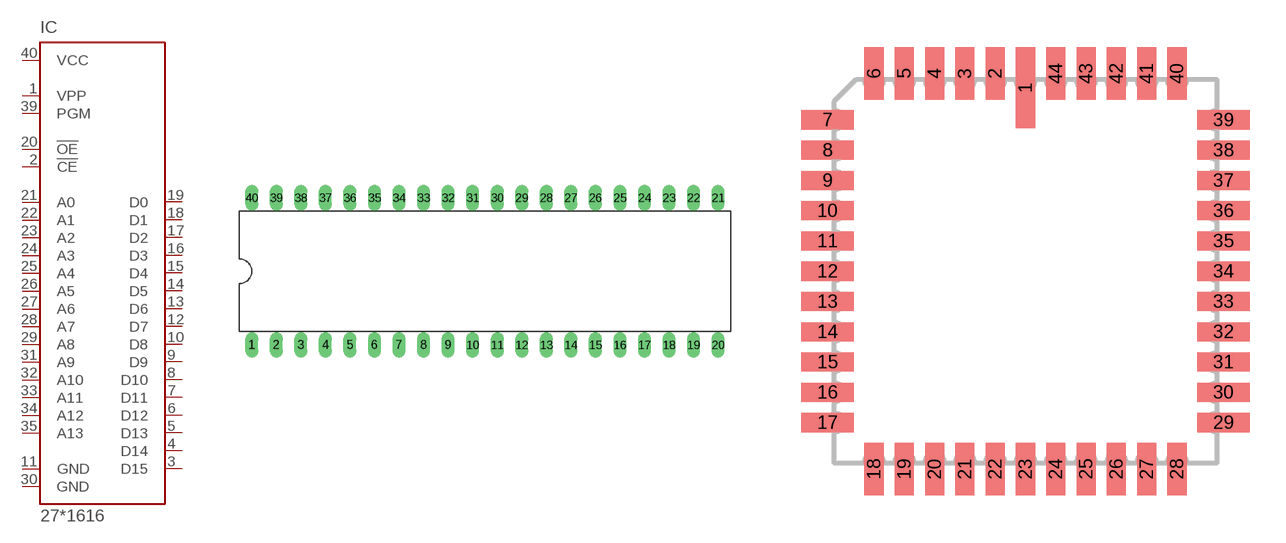
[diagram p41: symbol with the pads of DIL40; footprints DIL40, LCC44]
Designator prefix IC

## 27HC1616P (OC_FARNELL: unknown; OC_NEWARK: unknown)  [DIL40]
1  VPP  pas
2  !CE  in
3  D15  hiz
4  D14  hiz
5  D13  hiz
6  D12  hiz
7  D11  hiz
8  D10  hiz
9  D9  hiz
10  D8  hiz
11  GND  pwr
12  D7  hiz
13  D6  hiz
14  D5  hiz
15  D4  hiz
16  D3  hiz
17  D2  hiz
18  D1  hiz
19  D0  hiz
20  !OE  in
21  A0  in
22  A1  in
23  A2  in
24  A3  in
25  A4  in
26  A5  in
27  A6  in
28  A7  in
29  A8  in
30  GND  pwr
31  A9  in
32  A10  in
33  A11  in
34  A12  in
35  A13  in
36  NU36  nc
37  NU37  nc
38  NU38  nc
39  PGM  pas
40  VCC  pwr

## 271616L (OC_FARNELL: unknown; OC_NEWARK: unknown)  [LCC44]
2  VPP  pas
3  !CE  in
4  D15  hiz
5  D14  hiz
6  D13  hiz
7  D12  hiz
8  D11  hiz
9  D10  hiz
10  D9  hiz
11  D8  hiz
12  GND  pwr
13  NU36  nc
14  D7  hiz
15  D6  hiz
16  D5  hiz
17  D4  hiz
18  D3  hiz
19  D2  hiz
20  D1  hiz
21  D0  hiz
22  !OE  in
23  NU37  nc
24  A0  in
25  A1  in
26  A2  in
27  A3  in
28  A4  in
29  A5  in
30  A6  in
31  A7  in
32  A8  in
33  NU38  nc
34  GND  pwr
35  A9  in
36  A10  in
37  A11  in
38  A12  in
39  A13  in
43  PGM  pas
44  VCC  pwr

## Footprint DIL40 (pad centres in mm)
Dual In Line package type P
drill 0.813 long: 1 -24.13,-7.62; 2 -21.59,-7.62; 3 -19.05,-7.62; 4 -16.51,-7.62; 5 -13.97,-7.62; 6 -11.43,-7.62; 7 -8.89,-7.62; 8 -6.35,-7.62; 9 -3.81,-7.62; 10 -1.27,-7.62; 11 1.27,-7.62; 12 3.81,-7.62; 13 6.35,-7.62; 14 8.89,-7.62; 15 11.43,-7.62; 16 13.97,-7.62; 17 16.51,-7.62; 18 19.05,-7.62; 19 21.59,-7.62; 20 24.13,-7.62; 21 24.13,7.62; 22 21.59,7.62; 23 19.05,7.62; 24 16.51,7.62; 25 13.97,7.62; 26 11.43,7.62; 27 8.89,7.62; 28 6.35,7.62; 29 3.81,7.62; 30 1.27,7.62; 31 -1.27,7.62; 32 -3.81,7.62; 33 -6.35,7.62; 34 -8.89,7.62; 35 -11.43,7.62; 36 -13.97,7.62; 37 -16.51,7.62; 38 -19.05,7.62; 39 -21.59,7.62; 40 -24.13,7.62

## Footprint LCC44 (pad centres in mm)
CERAMIC LEADED CHIP CARRIER square, package type K
smd 0.8 x 3.4: 1 0,7.7
smd 0.8 x 2.2: 2 -1.27,8.3; 3 -2.54,8.3; 4 -3.81,8.3; 5 -5.08,8.3; 6 -6.35,8.3; 18 -6.35,-8.3; 19 -5.08,-8.3; 20 -3.81,-8.3; 21 -2.54,-8.3; 22 -1.27,-8.3; 23 0,-8.3; 24 1.27,-8.3; 25 2.54,-8.3; 26 3.81,-8.3; 27 5.08,-8.3; 28 6.35,-8.3; 40 6.35,8.3; 41 5.08,8.3; 42 3.81,8.3; 43 2.54,8.3; 44 1.27,8.3
smd 2.2 x 0.8: 7 -8.3,6.35; 8 -8.3,5.08; 9 -8.3,3.81; 10 -8.3,2.54; 11 -8.3,1.27; 12 -8.3,0; 13 -8.3,-1.27; 14 -8.3,-2.54; 15 -8.3,-3.81; 16 -8.3,-5.08; 17 -8.3,-6.35; 29 8.3,-6.35; 30 8.3,-5.08; 31 8.3,-3.81; 32 8.3,-2.54; 33 8.3,-1.27; 34 8.3,0; 35 8.3,1.27; 36 8.3,2.54; 37 8.3,3.81; 38 8.3,5.08; 39 8.3,6.35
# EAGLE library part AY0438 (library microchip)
LCD DRIVER

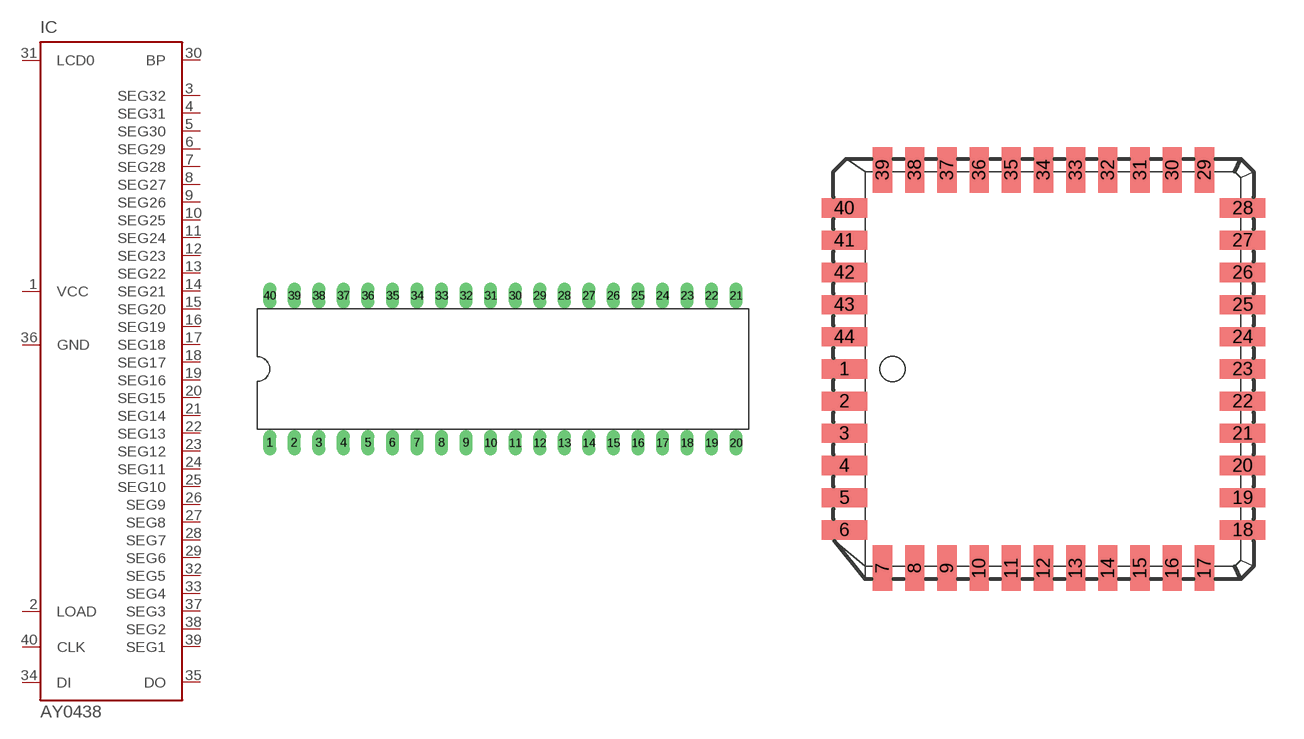
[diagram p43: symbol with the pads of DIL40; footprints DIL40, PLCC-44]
Designator prefix IC

## AY0438P (MF: MICROCHIP; MPN: AY0438/P; OC_FARNELL: 1627184; OC_NEWARK: 23C2747)  [DIL40]
1  VCC  pwr
2  LOAD  in
3  SEG32  out
4  SEG31  out
5  SEG30  out
6  SEG29  out
7  SEG28  out
8  SEG27  out
9  SEG26  out
10  SEG25  out
11  SEG24  out
12  SEG23  out
13  SEG22  out
14  SEG21  out
15  SEG20  out
16  SEG19  out
17  SEG18  out
18  SEG17  out
19  SEG16  out
20  SEG15  out
21  SEG14  out
22  SEG13  out
23  SEG12  out
24  SEG11  out
25  SEG10  out
26  SEG9  out
27  SEG8  out
28  SEG7  out
29  SEG6  out
30  BP  out
31  LCD0  in
32  SEG5  out
33  SEG4  out
34  DI  in
35  DO  out
36  GND  pwr
37  SEG3  out
38  SEG2  out
39  SEG1  out
40  CLK  in

## AY0438L (MF: MICROCHIP; MPN: AY0438/L; OC_FARNELL: 1467690; OC_NEWARK: 96K3652)  [PLCC-44]
1  VCC  pwr
2  LOAD  in
3  SEG32  out
4  SEG31  out
5  SEG30  out
7  SEG29  out
8  SEG28  out
9  SEG27  out
10  SEG26  out
11  SEG25  out
12  SEG24  out
13  SEG23  out
14  SEG22  out
15  SEG21  out
16  SEG20  out
17  SEG19  out
18  SEG18  out
19  SEG17  out
20  SEG16  out
21  SEG15  out
22  SEG14  out
23  SEG13  out
24  SEG12  out
25  SEG11  out
26  SEG10  out
27  SEG9  out
30  SEG8  out
31  SEG7  out
32  SEG6  out
33  BP  out
34  LCD0  in
35  SEG5  out
36  SEG4  out
37  DI  in
38  DO  out
40  GND  pwr
41  SEG3  out
42  SEG2  out
43  SEG1  out
44  CLK  in

## Footprint DIL40 (pad centres in mm)
Dual In Line package type P
drill 0.813 long: 1 -24.13,-7.62; 2 -21.59,-7.62; 3 -19.05,-7.62; 4 -16.51,-7.62; 5 -13.97,-7.62; 6 -11.43,-7.62; 7 -8.89,-7.62; 8 -6.35,-7.62; 9 -3.81,-7.62; 10 -1.27,-7.62; 11 1.27,-7.62; 12 3.81,-7.62; 13 6.35,-7.62; 14 8.89,-7.62; 15 11.43,-7.62; 16 13.97,-7.62; 17 16.51,-7.62; 18 19.05,-7.62; 19 21.59,-7.62; 20 24.13,-7.62; 21 24.13,7.62; 22 21.59,7.62; 23 19.05,7.62; 24 16.51,7.62; 25 13.97,7.62; 26 11.43,7.62; 27 8.89,7.62; 28 6.35,7.62; 29 3.81,7.62; 30 1.27,7.62; 31 -1.27,7.62; 32 -3.81,7.62; 33 -6.35,7.62; 34 -8.89,7.62; 35 -11.43,7.62; 36 -13.97,7.62; 37 -16.51,7.62; 38 -19.05,7.62; 39 -21.59,7.62; 40 -24.13,7.62

## Footprint PLCC-44 (pad centres in mm)
PLASTIC LEADED CHIP CARRIER square, package type L
smd 1.8 x 0.76: 1 -7.86,0; 2 -7.86,-1.27; 3 -7.86,-2.54; 4 -7.86,-3.81; 5 -7.86,-5.08; 6 -7.86,-6.35; 18 7.86,-6.35; 19 7.86,-5.08; 20 7.86,-3.81; 21 7.86,-2.54; 22 7.86,-1.27; 23 7.86,0; 24 7.86,1.27; 25 7.86,2.54; 26 7.86,3.81; 27 7.86,5.08; 28 7.86,6.35; 40 -7.86,6.35; 41 -7.86,5.08; 42 -7.86,3.81; 43 -7.86,2.54; 44 -7.86,1.27
smd 0.76 x 1.8: 7 -6.35,-7.86; 8 -5.08,-7.86; 9 -3.81,-7.86; 10 -2.54,-7.86; 11 -1.27,-7.86; 12 0,-7.86; 13 1.27,-7.86; 14 2.54,-7.86; 15 3.81,-7.86; 16 5.08,-7.86; 17 6.35,-7.86; 29 6.35,7.86; 30 5.08,7.86; 31 3.81,7.86; 32 2.54,7.86; 33 1.27,7.86; 34 0,7.86; 35 -1.27,7.86; 36 -2.54,7.86; 37 -3.81,7.86; 38 -5.08,7.86; 39 -6.35,7.86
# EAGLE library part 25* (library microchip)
Serial EEPROM 4K/ 8K , SPI bus

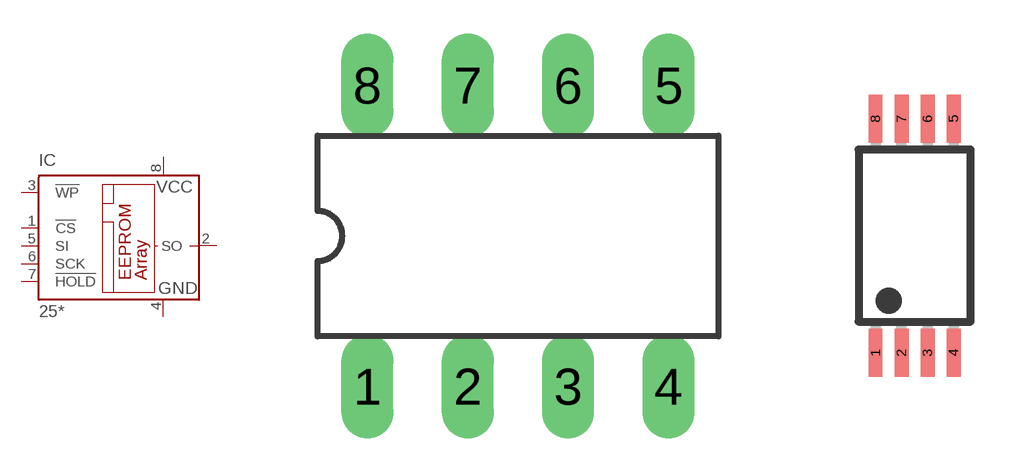
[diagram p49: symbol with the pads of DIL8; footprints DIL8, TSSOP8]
Designator prefix IC

## 25AA040P (MF: MICROCHIP; MPN: 25AA040-I/P; OC_FARNELL: 1331347; OC_NEWARK: 92C7334), 25AA080P (MF: MICROCHIP; MPN: 25AA080/P; OC_FARNELL: 1331352; OC_NEWARK: 92C7349), 25C040P (MF: MICROCHIP; MPN: 25C040/P; OC_FARNELL: 1607554; OC_NEWARK: 96K4084), 25C080P (MF: MICROCHIP; MPN: 25C080-I/P; OC_FARNELL: 1816073; OC_NEWARK: 92C7398), 25LC040P (MF: MICROCHIP; MPN: 25LC040/P; OC_FARNELL: 9758100; OC_NEWARK: 96K4091), 25LC080P (MF: MICROCHIP; MPN: 25LC080/P; OC_FARNELL: 1556143; OC_NEWARK: 92C7440)  [DIL8]
1  !CS  in
2  SO
3  !WP  in
4  GND  pwr
5  SI  in
6  SCK  in
7  !HOLD  in
8  VCC  pwr

## 25AA040ST (MPN: 25AA040A-I/MS; OC_FARNELL: 1331345; OC_NEWARK: 35M0801), 25C040ST (MF: MICROCHIP; MPN: 25C040T/SN; OC_FARNELL: unknown; OC_NEWARK: 30C5312), 25LC040ST (MF: MICROCHIP; MPN: 25LC040A-I/ST; OC_FARNELL: 1815998; OC_NEWARK: 72J3684)  [TSSOP8]
Pads as for DIL8

## 25AA080SN (MF: MICROCHIP; MPN: 25AA080/SN; OC_FARNELL: 1816072; OC_NEWARK: 92C7351), 25C080SN (MF: MICROCHIP; MPN: 25C080/SN; OC_FARNELL: unknown; OC_NEWARK: 96K4086), 25LC080SN (MF: MICROCHIP; MPN: 25LC080/SN; OC_FARNELL: 1137302; OC_NEWARK: 96K4092)  [SO-08]
Pads as for DIL8

## Footprint DIL8 (pad centres in mm)
Dual In Line package type P
drill 0.813 long: 1 -3.81,-3.81; 2 -1.27,-3.81; 3 1.27,-3.81; 4 3.81,-3.81; 5 3.81,3.81; 6 1.27,3.81; 7 -1.27,3.81; 8 -3.81,3.81

## Footprint TSSOP8 (pad centres in mm)
Thin Shrink Small Outline Package package type ST
smd 0.35 x 1.2: 1 -0.975,-2.925; 2 -0.325,-2.925; 3 0.325,-2.925; 4 0.975,-2.925; 5 0.975,2.925; 6 0.325,2.925; 7 -0.325,2.925; 8 -0.975,2.925

## Footprint SO-08 (pad centres in mm)
Small Outline Narrow Plastic Gull Wing 150-mil body, package type SN
smd 0.6 x 2.2: 1 -1.905,-2.6; 2 -0.635,-2.6; 3 0.635,-2.6; 4 1.905,-2.6; 5 1.905,2.6; 6 0.635,2.6; 7 -0.635,2.6; 8 -1.905,2.6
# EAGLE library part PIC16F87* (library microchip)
MICROCONTROLLER

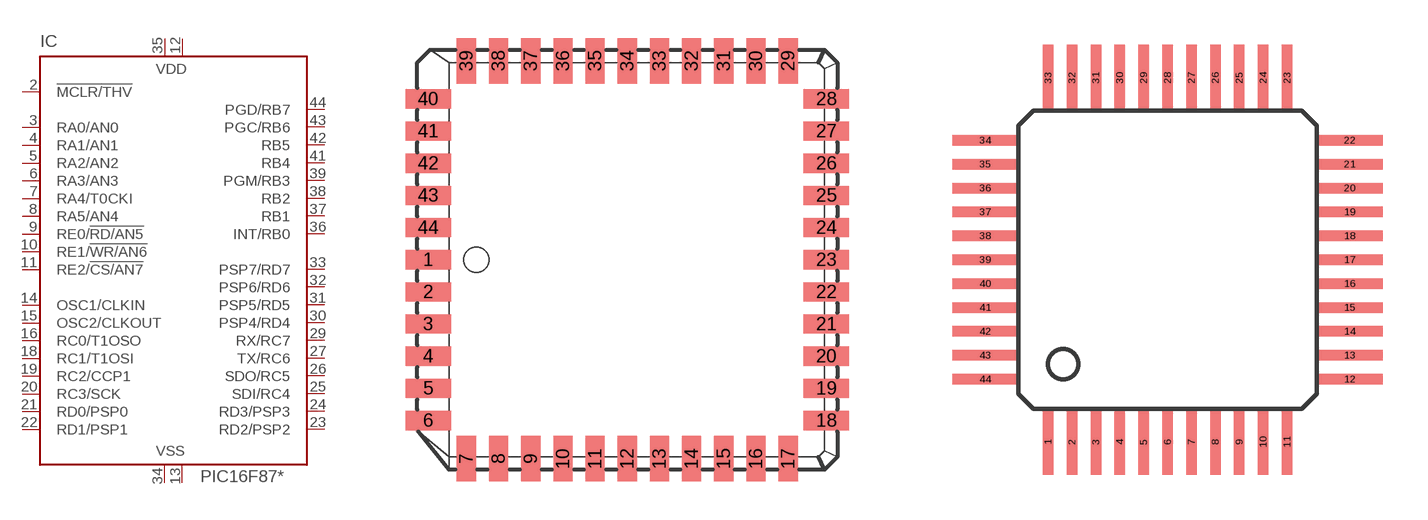
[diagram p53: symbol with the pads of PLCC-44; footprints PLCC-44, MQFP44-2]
Designator prefix IC

## PIC16F874L (MF: MICROCHIP; MPN: PIC16F874-04/L; OC_FARNELL: 9761160; OC_NEWARK: 23C5056), PIC16F877L (MF: MICROCHIP; MPN: PIC16F877-20/L; OC_FARNELL: 1660042; OC_NEWARK: 12C1952)  [PLCC-44]
2  !MCLR/THV  in
3  RA0/AN0
4  RA1/AN1
5  RA2/AN2
6  RA3/AN3
7  RA4/T0CKI
8  RA5/AN4
9  RE0/!RD/AN5
10  RE1/!WR/AN6
11  RE2/!CS/AN7
12  VDD  pwr
13  VSS  pwr
14  OSC1/CLKIN  in
15  OSC2/CLKOUT  out
16  RC0/T1OSO
18  RC1/T1OSI
19  RC2/CCP1
20  RC3/SCK
21  RD0/PSP0
22  RD1/PSP1
23  RD2/PSP2
24  RD3/PSP3
25  SDI/RC4
26  SDO/RC5
27  TX/RC6
29  RX/RC7
30  PSP4/RD4
31  PSP5/RD5
32  PSP6/RD6
33  PSP7/RD7
34  VSS  pwr
35  VDD  pwr
36  INT/RB0
37  RB1
38  RB2
39  PGM/RB3
41  RB4
42  RB5
43  PGC/RB6
44  PGD/RB7

## PIC16F874PQ (MPN: PIC16F874-20I/PQ; OC_FARNELL: 1084251; OC_NEWARK: 97K7435), PIC16F877PQ (MF: MICROCHIP; MPN: PIC16F877-04/PQ; OC_FARNELL: 9761357; OC_NEWARK: 23C5094)  [MQFP44-2]
1  RX/RC7
2  PSP4/RD4
3  PSP5/RD5
4  PSP6/RD6
5  PSP7/RD7
6  VSS  pwr
7  VDD  pwr
8  INT/RB0
9  RB1
10  RB2
11  PGM/RB3
14  RB4
15  RB5
16  PGC/RB6
17  PGD/RB7
18  !MCLR/THV  in
19  RA0/AN0
20  RA1/AN1
21  RA2/AN2
22  RA3/AN3
23  RA4/T0CKI
24  RA5/AN4
25  RE0/!RD/AN5
26  RE1/!WR/AN6
27  RE2/!CS/AN7
28  VDD  pwr
29  VSS  pwr
30  OSC1/CLKIN  in
31  OSC2/CLKOUT  out
32  RC0/T1OSO
35  RC1/T1OSI
36  RC2/CCP1
37  RC3/SCK
38  RD0/PSP0
39  RD1/PSP1
40  RD2/PSP2
41  RD3/PSP3
42  SDI/RC4
43  SDO/RC5
44  TX/RC6

## PIC16F874PT (MPN: PIC16F874-04/PQ; OC_FARNELL: 1084251; OC_NEWARK: 97K7429), PIC16F877PT (MF: MICROCHIP; MPN: PIC16F877-04/PQ; OC_FARNELL: 9761411; OC_NEWARK: 23C5094)  [TQFP44]
Pads as for MQFP44-2

## PIC16F874P (MPN: PIC16F874-04I/P; OC_FARNELL: 1196797; OC_NEWARK: 24M5903), PIC16F877P (MF: MICROCHIP; MPN: PIC16F877-04/P; OC_FARNELL: 9761349; OC_NEWARK: 61K3463)  [DIL40]
1  !MCLR/THV  in
2  RA0/AN0
3  RA1/AN1
4  RA2/AN2
5  RA3/AN3
6  RA4/T0CKI
7  RA5/AN4
8  RE0/!RD/AN5
9  RE1/!WR/AN6
10  RE2/!CS/AN7
11  VDD  pwr
12  VSS  pwr
13  OSC1/CLKIN  in
14  OSC2/CLKOUT  out
15  RC0/T1OSO
16  RC1/T1OSI
17  RC2/CCP1
18  RC3/SCK
19  RD0/PSP0
20  RD1/PSP1
21  RD2/PSP2
22  RD3/PSP3
23  SDI/RC4
24  SDO/RC5
25  TX/RC6
26  RX/RC7
27  PSP4/RD4
28  PSP5/RD5
29  PSP6/RD6
30  PSP7/RD7
31  VSS  pwr
32  VDD  pwr
33  INT/RB0
34  RB1
35  RB2
36  PGM/RB3
37  RB4
38  RB5
39  PGC/RB6
40  PGD/RB7

## PIC16F877SO (OC_FARNELL: unknown; OC_NEWARK: unknown)  [S44]
Pads as for PLCC-44

## Footprint PLCC-44 (pad centres in mm)
PLASTIC LEADED CHIP CARRIER square, package type L
smd 1.8 x 0.76: 1 -7.86,0; 2 -7.86,-1.27; 3 -7.86,-2.54; 4 -7.86,-3.81; 5 -7.86,-5.08; 6 -7.86,-6.35; 18 7.86,-6.35; 19 7.86,-5.08; 20 7.86,-3.81; 21 7.86,-2.54; 22 7.86,-1.27; 23 7.86,0; 24 7.86,1.27; 25 7.86,2.54; 26 7.86,3.81; 27 7.86,5.08; 28 7.86,6.35; 40 -7.86,6.35; 41 -7.86,5.08; 42 -7.86,3.81; 43 -7.86,2.54; 44 -7.86,1.27
smd 0.76 x 1.8: 7 -6.35,-7.86; 8 -5.08,-7.86; 9 -3.81,-7.86; 10 -2.54,-7.86; 11 -1.27,-7.86; 12 0,-7.86; 13 1.27,-7.86; 14 2.54,-7.86; 15 3.81,-7.86; 16 5.08,-7.86; 17 6.35,-7.86; 29 6.35,7.86; 30 5.08,7.86; 31 3.81,7.86; 32 2.54,7.86; 33 1.27,7.86; 34 0,7.86; 35 -1.27,7.86; 36 -2.54,7.86; 37 -3.81,7.86; 38 -5.08,7.86; 39 -6.35,7.86

## Footprint MQFP44-2 (pad centres in mm)
Plastic Metric Quad Flat Pack package type PQ
smd 0.35 x 2.2: 1 -4,-6.1; 2 -3.2,-6.1; 3 -2.4,-6.1; 4 -1.6,-6.1; 5 -0.8,-6.1; 6 0,-6.1; 7 0.8,-6.1; 8 1.6,-6.1; 9 2.4,-6.1; 10 3.2,-6.1; 11 4,-6.1; 23 4,6.1; 24 3.2,6.1; 25 2.4,6.1; 26 1.6,6.1; 27 0.8,6.1; 28 0,6.1; 29 -0.8,6.1; 30 -1.6,6.1; 31 -2.4,6.1; 32 -3.2,6.1; 33 -4,6.1
smd 2.2 x 0.35: 12 6.1,-4; 13 6.1,-3.2; 14 6.1,-2.4; 15 6.1,-1.6; 16 6.1,-0.8; 17 6.1,0; 18 6.1,0.8; 19 6.1,1.6; 20 6.1,2.4; 21 6.1,3.2; 22 6.1,4; 34 -6.1,4; 35 -6.1,3.2; 36 -6.1,2.4; 37 -6.1,1.6; 38 -6.1,0.8; 39 -6.1,0; 40 -6.1,-0.8; 41 -6.1,-1.6; 42 -6.1,-2.4; 43 -6.1,-3.2; 44 -6.1,-4

## Footprint TQFP44 (pad centres in mm)
Thin Quad Flat Pack package type TQ
smd 1.5 x 0.5: 1 -5.8,4; 2 -5.8,3.2; 3 -5.8,2.4; 4 -5.8,1.6; 5 -5.8,0.8; 6 -5.8,0; 7 -5.8,-0.8; 8 -5.8,-1.6; 9 -5.8,-2.4; 10 -5.8,-3.2; 11 -5.8,-4; 23 5.8,-4; 24 5.8,-3.2; 25 5.8,-2.4; 26 5.8,-1.6; 27 5.8,-0.8; 28 5.8,0; 29 5.8,0.8; 30 5.8,1.6; 31 5.8,2.4; 32 5.8,3.2; 33 5.8,4
smd 0.5 x 1.5: 12 -4,-5.8; 13 -3.2,-5.8; 14 -2.4,-5.8; 15 -1.6,-5.8; 16 -0.8,-5.8; 17 0,-5.8; 18 0.8,-5.8; 19 1.6,-5.8; 20 2.4,-5.8; 21 3.2,-5.8; 22 4,-5.8; 34 4,5.8; 35 3.2,5.8; 36 2.4,5.8; 37 1.6,5.8; 38 0.8,5.8; 39 0,5.8; 40 -0.8,5.8; 41 -1.6,5.8; 42 -2.4,5.8; 43 -3.2,5.8; 44 -4,5.8

## Footprint DIL40 (pad centres in mm)
Dual In Line package type P
drill 0.813 long: 1 -24.13,-7.62; 2 -21.59,-7.62; 3 -19.05,-7.62; 4 -16.51,-7.62; 5 -13.97,-7.62; 6 -11.43,-7.62; 7 -8.89,-7.62; 8 -6.35,-7.62; 9 -3.81,-7.62; 10 -1.27,-7.62; 11 1.27,-7.62; 12 3.81,-7.62; 13 6.35,-7.62; 14 8.89,-7.62; 15 11.43,-7.62; 16 13.97,-7.62; 17 16.51,-7.62; 18 19.05,-7.62; 19 21.59,-7.62; 20 24.13,-7.62; 21 24.13,7.62; 22 21.59,7.62; 23 19.05,7.62; 24 16.51,7.62; 25 13.97,7.62; 26 11.43,7.62; 27 8.89,7.62; 28 6.35,7.62; 29 3.81,7.62; 30 1.27,7.62; 31 -1.27,7.62; 32 -3.81,7.62; 33 -6.35,7.62; 34 -8.89,7.62; 35 -11.43,7.62; 36 -13.97,7.62; 37 -16.51,7.62; 38 -19.05,7.62; 39 -21.59,7.62; 40 -24.13,7.62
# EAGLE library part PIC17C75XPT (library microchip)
MICROCONTROLLER

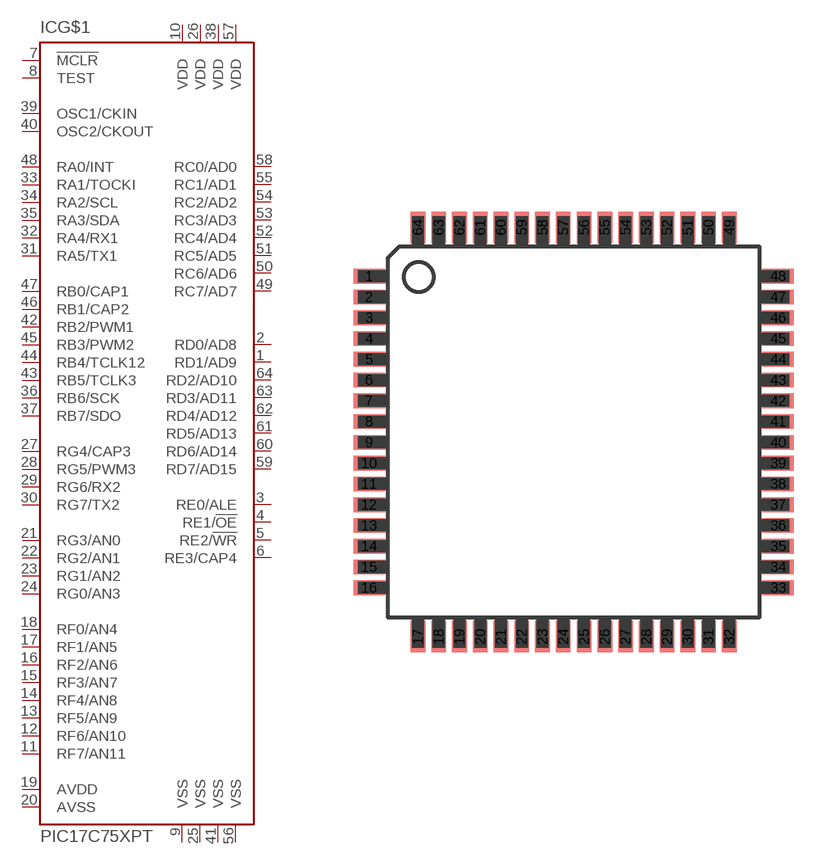
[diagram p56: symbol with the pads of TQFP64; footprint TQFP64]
Designator prefix IC; gates G$1=PIC17C75X P1=VDD P2=VDD P3=VDD P4=VDD P5=VSS P6=VSS P7=VSS P8=VSS

## PIC17C75XPT (MF: MICROCHIP; MPN: PIC17C756A-33I/PT; OC_FARNELL: unknown; OC_NEWARK: 23C5980)  [TQFP64]
1  G$1:RD1/AD9
2  G$1:RD0/AD8
3  G$1:RE0/ALE
4  G$1:RE1/!OE
5  G$1:RE2/!WR
6  G$1:RE3/CAP4
7  G$1:!MCLR  in
8  G$1:TEST  in
9  P5:VSS  pwr
10  P1:VDD  pwr
11  G$1:RF7/AN11
12  G$1:RF6/AN10
13  G$1:RF5/AN9
14  G$1:RF4/AN8
15  G$1:RF3/AN7
16  G$1:RF2/AN6
17  G$1:RF1/AN5
18  G$1:RF0/AN4
19  G$1:AVDD  pwr
20  G$1:AVSS  pwr
21  G$1:RG3/AN0
22  G$1:RG2/AN1
23  G$1:RG1/AN2
24  G$1:RG0/AN3
25  P6:VSS  pwr
26  P2:VDD  pwr
27  G$1:RG4/CAP3
28  G$1:RG5/PWM3
29  G$1:RG6/RX2
30  G$1:RG7/TX2
31  G$1:RA5/TX1
32  G$1:RA4/RX1
33  G$1:RA1/TOCKI  in
34  G$1:RA2/SCL
35  G$1:RA3/SDA
36  G$1:RB6/SCK
37  G$1:RB7/SDO
38  P3:VDD  pwr
39  G$1:OSC1/CKIN  in
40  G$1:OSC2/CKOUT  out
41  P7:VSS  pwr
42  G$1:RB2/PWM1
43  G$1:RB5/TCLK3
44  G$1:RB4/TCLK12
45  G$1:RB3/PWM2
46  G$1:RB1/CAP2
47  G$1:RB0/CAP1
48  G$1:RA0/INT  in
49  G$1:RC7/AD7
50  G$1:RC6/AD6
51  G$1:RC5/AD5
52  G$1:RC4/AD4
53  G$1:RC3/AD3
54  G$1:RC2/AD2
55  G$1:RC1/AD1
56  P8:VSS  pwr
57  P4:VDD  pwr
58  G$1:RC0/AD0
59  G$1:RD7/AD15
60  G$1:RD6/AD14
61  G$1:RD5/AD13
62  G$1:RD4/AD12
63  G$1:RD3/AD11
64  G$1:RD2/AD10

## Footprint TQFP64 (pad centres in mm)
Thin Quad Flat Pack
smd 1.194 x 0.559: 1 -7.76,5.905; 2 -7.76,5.118; 3 -7.76,4.331; 4 -7.76,3.543; 5 -7.76,2.756; 6 -7.76,1.968; 7 -7.76,1.181; 8 -7.76,0.394; 9 -7.76,-0.394; 10 -7.76,-1.181; 11 -7.76,-1.968; 12 -7.76,-2.756; 13 -7.76,-3.543; 14 -7.76,-4.331; 15 -7.76,-5.118; 16 -7.76,-5.905; 33 7.76,-5.905; 34 7.76,-5.118; 35 7.76,-4.331; 36 7.76,-3.543; 37 7.76,-2.756; 38 7.76,-1.968; 39 7.76,-1.181; 40 7.76,-0.394; 41 7.76,0.394; 42 7.76,1.181; 43 7.76,1.968; 44 7.76,2.756; 45 7.76,3.543; 46 7.76,4.331; 47 7.76,5.118; 48 7.76,5.905
smd 0.559 x 1.194: 17 -5.905,-7.76; 18 -5.118,-7.76; 19 -4.331,-7.76; 20 -3.543,-7.76; 21 -2.756,-7.76; 22 -1.968,-7.76; 23 -1.181,-7.76; 24 -0.394,-7.76; 25 0.394,-7.76; 26 1.181,-7.76; 27 1.968,-7.76; 28 2.756,-7.76; 29 3.543,-7.76; 30 4.331,-7.76; 31 5.118,-7.76; 32 5.905,-7.76; 49 5.905,7.76; 50 5.118,7.76; 51 4.331,7.76; 52 3.543,7.76; 53 2.756,7.76; 54 1.968,7.76; 55 1.181,7.76; 56 0.394,7.76; 57 -0.394,7.76; 58 -1.181,7.76; 59 -1.968,7.76; 60 -2.756,7.76; 61 -3.543,7.76; 62 -4.331,7.76; 63 -5.118,7.76; 64 -5.905,7.76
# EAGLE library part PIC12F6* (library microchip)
Data Sheet 8-Pin FLASH-Based 8-Bit CMOS Microcontrollers Source: http://www.microchip.com .. 41190c.pdf

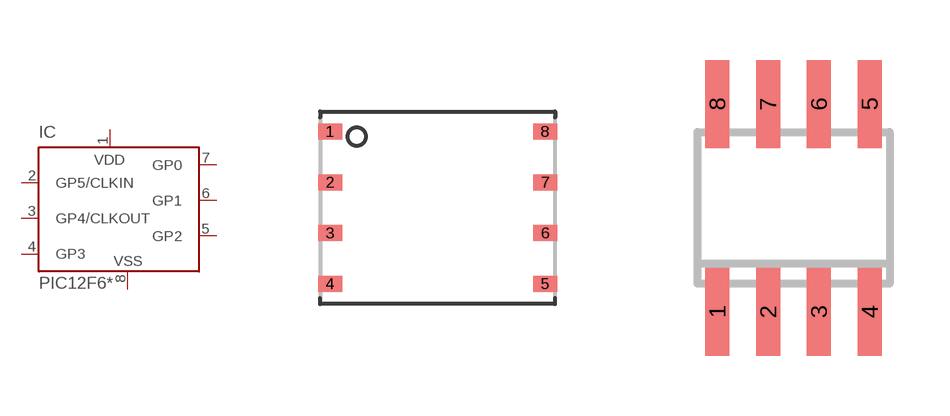
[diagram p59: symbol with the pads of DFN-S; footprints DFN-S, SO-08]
Designator prefix IC

## PIC12F629MF (MF: MICROCHIP; MPN: PIC12F629-I/MD; OC_FARNELL: 1618004; OC_NEWARK: 56K7222), PIC12F675MF (MPN: PIC12F675-I/MD; OC_FARNELL: unknown; OC_NEWARK: 56K7227)  [DFN-S]
1  VDD  pwr
2  GP5/CLKIN
3  GP4/CLKOUT
4  GP3  in
5  GP2
6  GP1
7  GP0
8  VSS  pwr

## PIC12F629SN (MF: MICROCHIP; MPN: PIC12F629-I/SN; OC_FARNELL: 9759000; OC_NEWARK: 61K3433), PIC12F675SN (MF: MICROCHIP; MPN: PIC12F675-E/SN; OC_FARNELL: 9759026; OC_NEWARK: 92C4341)  [SO-08]
Pads as for DFN-S

## PIC12F629P (MF: MICROCHIP; MPN: PIC12F629-I/P; OC_FARNELL: 1292253; OC_NEWARK: 67K0822), PIC12F675P (MF: MICROCHIP; MPN: PIC12F675-E/P; OC_FARNELL: 9759018; OC_NEWARK: 92C4340)  [DIL8]
Pads as for DFN-S

## Footprint DFN-S (pad centres in mm)
8-Lead Plastic Dual Flat No Lead Package (MF) 6x5 mm Body (DFN-S) Source: http://www.microchip.com .. 41190c.pdf
smd 0.6 x 0.4: 1 -2.69,1.905; 2 -2.69,0.635; 3 -2.69,-0.635; 4 -2.69,-1.905; 5 2.69,-1.905; 6 2.69,-0.635; 7 2.69,0.635; 8 2.69,1.905

## Footprint SO-08 (pad centres in mm)
Small Outline Narrow Plastic Gull Wing 150-mil body, package type SN
smd 0.6 x 2.2: 1 -1.905,-2.6; 2 -0.635,-2.6; 3 0.635,-2.6; 4 1.905,-2.6; 5 1.905,2.6; 6 0.635,2.6; 7 -0.635,2.6; 8 -1.905,2.6

## Footprint DIL8 (pad centres in mm)
Dual In Line package type P
drill 0.813 long: 1 -3.81,-3.81; 2 -1.27,-3.81; 3 1.27,-3.81; 4 3.81,-3.81; 5 3.81,3.81; 6 1.27,3.81; 7 -1.27,3.81; 8 -3.81,3.81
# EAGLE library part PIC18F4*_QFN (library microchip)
USB Microcontrollers with nanoWatt Technology High-Performance, Enhanced Flash, 28/40/44-Pin, Source: http://ww1.microchip.com/downloads/en/devicedoc/39632c.pdf

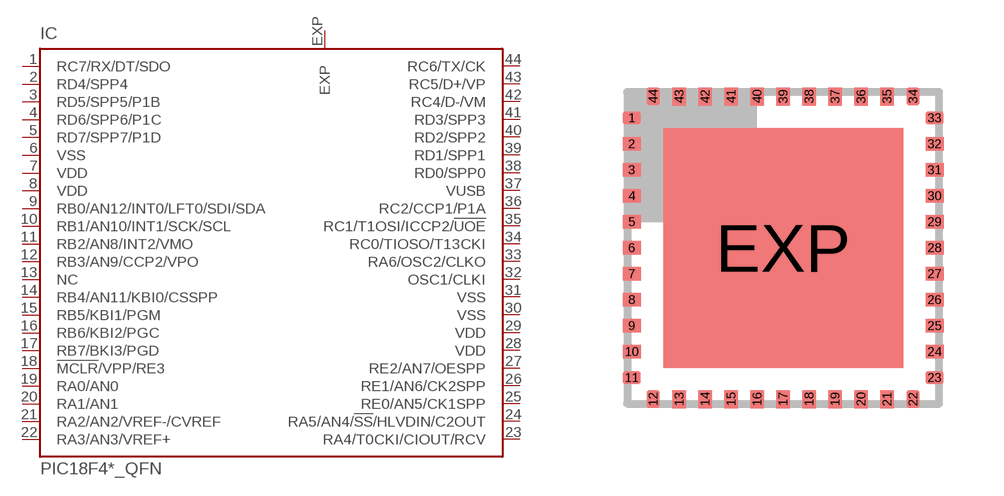
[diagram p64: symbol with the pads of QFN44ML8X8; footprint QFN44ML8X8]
Designator prefix IC

## PIC18F4455_QFN (MF: MICROCHIP; MPN: PIC18F4455T-I/ML; OC_FARNELL: 9321314; OC_NEWARK: 08J9629), PIC18F4550_QFN (MF: MICROCHIP; MPN: PIC18F4550-I/ML; OC_FARNELL: 1292276; OC_NEWARK: 08J9631)  [QFN44ML8X8]
1  RC7/RX/DT/SDO
2  RD4/SPP4
3  RD5/SPP5/P1B
4  RD6/SPP6/P1C
5  RD7/SPP7/P1D
6  VSS  pwr
7  VDD  pwr
8  VDD  pwr
9  RB0/AN12/INT0/LFT0/SDI/SDA
10  RB1/AN10/INT1/SCK/SCL
11  RB2/AN8/INT2/VMO
12  RB3/AN9/CCP2/VPO
13  NC
14  RB4/AN11/KBI0/CSSPP
15  RB5/KBI1/PGM
16  RB6/KBI2/PGC
17  RB7/BKI3/PGD
18  !MCLR!/VPP/RE3  in
19  RA0/AN0
20  RA1/AN1
21  RA2/AN2/VREF-/CVREF
22  RA3/AN3/VREF+
23  RA4/T0CKI/CIOUT/RCV
24  RA5/AN4/!SS!/HLVDIN/C2OUT
25  RE0/AN5/CK1SPP
26  RE1/AN6/CK2SPP
27  RE2/AN7/OESPP
28  VDD  pwr
29  VDD  pwr
30  VSS  pwr
31  VSS  pwr
32  OSC1/CLKI  in
33  RA6/OSC2/CLKO  out
34  RC0/TIOSO/T13CKI
35  RC1/T1OSI/ICCP2/!UOE
36  RC2/CCP1/P1A
37  VUSB
38  RD0/SPP0
39  RD1/SPP1
40  RD2/SPP2
41  RD3/SPP3
42  RC4/D-/VM
43  RC5/D+/VP
44  RC6/TX/CK
EXP  EXP  pas

## Footprint QFN44ML8X8 (pad centres in mm)
44-Lead Plastic Quad Flat No Lead Package (ML) 8x8 mm Body (QFN) Source: http://ww1.microchip.com/downloads/en/devicedoc/39632c.pdf
smd 0.45 x 0.33: 1 -3.788,3.25; 2 -3.788,2.6; 3 -3.788,1.95; 4 -3.788,1.3; 5 -3.788,0.65; 6 -3.788,0; 7 -3.788,-0.65; 8 -3.788,-1.3; 9 -3.788,-1.95; 10 -3.788,-2.6; 11 -3.788,-3.25; 23 3.788,-3.25; 24 3.788,-2.6; 25 3.788,-1.95; 26 3.788,-1.3; 27 3.788,-0.65; 28 3.788,0; 29 3.788,0.65; 30 3.788,1.3; 31 3.788,1.95; 32 3.788,2.6; 33 3.788,3.25
smd 0.33 x 0.45: 12 -3.25,-3.788; 13 -2.6,-3.788; 14 -1.95,-3.788; 15 -1.3,-3.788; 16 -0.65,-3.788; 17 0,-3.788; 18 0.65,-3.788; 19 1.3,-3.788; 20 1.95,-3.788; 21 2.6,-3.788; 22 3.25,-3.788; 34 3.25,3.788; 35 2.6,3.788; 36 1.95,3.788; 37 1.3,3.788; 38 0.65,3.788; 39 0,3.788; 40 -0.65,3.788; 41 -1.3,3.788; 42 -1.95,3.788; 43 -2.6,3.788; 44 -3.25,3.788
smd 6 x 6: EXP 0,0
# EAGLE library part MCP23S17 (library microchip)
http://ww1.microchip.com/downloads/en/DeviceDoc/21952a.pdf Source: http://ww1.microchip.com/downloads/en/DeviceDoc/21952a.pdf

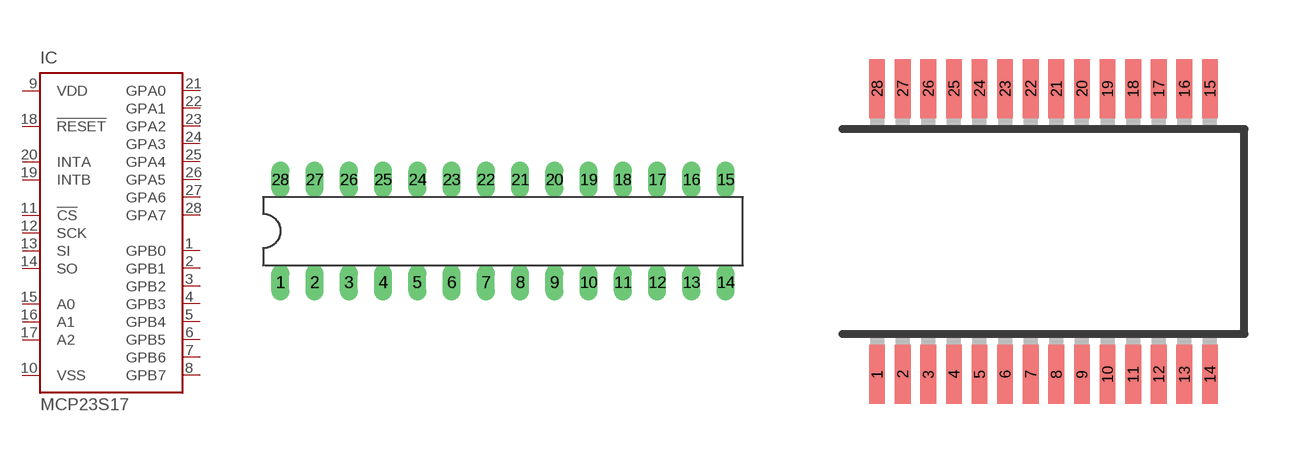
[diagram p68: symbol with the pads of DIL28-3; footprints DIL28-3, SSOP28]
Designator prefix IC

## MCP23S17SP (MF: MICROCHIP; MPN: MCP23S17-E/SP; OC_FARNELL: 1292238; OC_NEWARK: 31K2951)  [DIL28-3]
1  GPB0
2  GPB1
3  GPB2
4  GPB3
5  GPB4
6  GPB5
7  GPB6
8  GPB7
9  VDD  pwr
10  VSS  pwr
11  !CS  in
12  SCK  in
13  SI  in
14  SO  out
15  A0  in
16  A1  in
17  A2  in
18  !RESET  in
19  INTB  out
20  INTA  out
21  GPA0
22  GPA1
23  GPA2
24  GPA3
25  GPA4
26  GPA5
27  GPA6
28  GPA7

## MCP23S17SS (MF: MICROCHIP; MPN: MCP23S17-E/SS; OC_FARNELL: 1467675; OC_NEWARK: 31K2952)  [SSOP28]
Pads as for DIL28-3

## MCP23S17SO (MF: MICROCHIP; MPN: MCP23S17-E/SO; OC_FARNELL: unknown; OC_NEWARK: 31K2950)  [SO28W]
Pads as for DIL28-3

## MCP23S17ML (MF: MICROCHIP; MPN: MCP23S17-E/ML; OC_FARNELL: unknown; OC_NEWARK: 31K2949)  [QFN28-ML_6X6MM]
1  GPB4
2  GPB5
3  GPB6
4  GPB7
5  VDD  pwr
6  VSS  pwr
7  !CS  in
8  SCK  in
9  SI  in
10  SO  out
11  A0  in
12  A1  in
13  A2  in
14  !RESET  in
15  INTB  out
16  INTA  out
17  GPA0
18  GPA1
19  GPA2
20  GPA3
21  GPA4
22  GPA5
23  GPA6
24  GPA7
25  GPB0
26  GPB1
27  GPB2
28  GPB3

## Footprint DIL28-3 (pad centres in mm)
Dual In Line package type P
drill 0.813 long: 1 -16.51,-3.81; 2 -13.97,-3.81; 3 -11.43,-3.81; 4 -8.89,-3.81; 5 -6.35,-3.81; 6 -3.81,-3.81; 7 -1.27,-3.81; 8 1.27,-3.81; 9 3.81,-3.81; 10 6.35,-3.81; 11 8.89,-3.81; 12 11.43,-3.81; 13 13.97,-3.81; 14 16.51,-3.81; 15 16.51,3.81; 16 13.97,3.81; 17 11.43,3.81; 18 8.89,3.81; 19 6.35,3.81; 20 3.81,3.81; 21 1.27,3.81; 22 -1.27,3.81; 23 -3.81,3.81; 24 -6.35,3.81; 25 -8.89,3.81; 26 -11.43,3.81; 27 -13.97,3.81; 28 -16.51,3.81

## Footprint SSOP28 (pad centres in mm)
Shrink Small Outline Package package type SS
smd 0.4 x 1.5: 1 -4.225,-3.625; 2 -3.575,-3.625; 3 -2.925,-3.625; 4 -2.275,-3.625; 5 -1.625,-3.625; 6 -0.975,-3.625; 7 -0.325,-3.625; 8 0.325,-3.625; 9 0.975,-3.625; 10 1.625,-3.625; 11 2.275,-3.625; 12 2.925,-3.625; 13 3.575,-3.625; 14 4.225,-3.625; 15 4.225,3.625; 16 3.575,3.625; 17 2.925,3.625; 18 2.275,3.625; 19 1.625,3.625; 20 0.975,3.625; 21 0.325,3.625; 22 -0.325,3.625; 23 -0.975,3.625; 24 -1.625,3.625; 25 -2.275,3.625; 26 -2.925,3.625; 27 -3.575,3.625; 28 -4.225,3.625

## Footprint SO28W (pad centres in mm)
28-Lead Plastic Small Outline (SO) Wide, 300 mil Body (SOIC) Source: http://ww1.microchip.com/downloads/en/devicedoc/39632c.pdf
smd 0.65 x 1.7: 1 -7.62,-4.78; 2 -6.35,-4.78; 3 -5.08,-4.78; 4 -3.81,-4.78; 5 -2.54,-4.78; 6 -1.27,-4.78; 7 0,-4.78; 8 1.27,-4.78; 9 2.54,-4.78; 10 3.81,-4.78; 11 5.08,-4.78; 12 6.35,-4.78; 13 7.62,-4.78; 14 8.89,-4.78; 15 8.89,4.78; 16 7.62,4.78; 17 6.35,4.78; 18 5.08,4.78; 19 3.81,4.78; 20 2.54,4.78; 21 1.27,4.78; 22 0,4.78; 23 -1.27,4.78; 24 -2.54,4.78; 25 -3.81,4.78; 26 -5.08,4.78; 27 -6.35,4.78; 28 -7.62,4.78

## Footprint QFN28-ML_6X6MM (pad centres in mm)
QFN28-ML_6X6MM Source: http://www.microchip.com .. 39637a.pdf
smd 0.7 x 0.35: 1 -2.7,1.95; 2 -2.7,1.3; 3 -2.7,0.65; 4 -2.7,0; 5 -2.7,-0.65; 6 -2.7,-1.3; 7 -2.7,-1.95; 15 2.7,-1.95; 16 2.7,-1.3; 17 2.7,-0.65; 18 2.7,0; 19 2.7,0.65; 20 2.7,1.3; 21 2.7,1.95
smd 0.35 x 0.7: 8 -1.95,-2.7; 9 -1.3,-2.7; 10 -0.65,-2.7; 11 0,-2.7; 12 0.65,-2.7; 13 1.3,-2.7; 14 1.95,-2.7; 22 1.95,2.7; 23 1.3,2.7; 24 0.65,2.7; 25 0,2.7; 26 -0.65,2.7; 27 -1.3,2.7; 28 -1.95,2.7
smd 3.7 x 3.7: EXP 0,0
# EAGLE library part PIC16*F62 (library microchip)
FLASH-Based 8-Bit CMOS Microcontroller Source: http://ww1.microchip.com/downloads/en/DeviceDoc/40300C.pdf

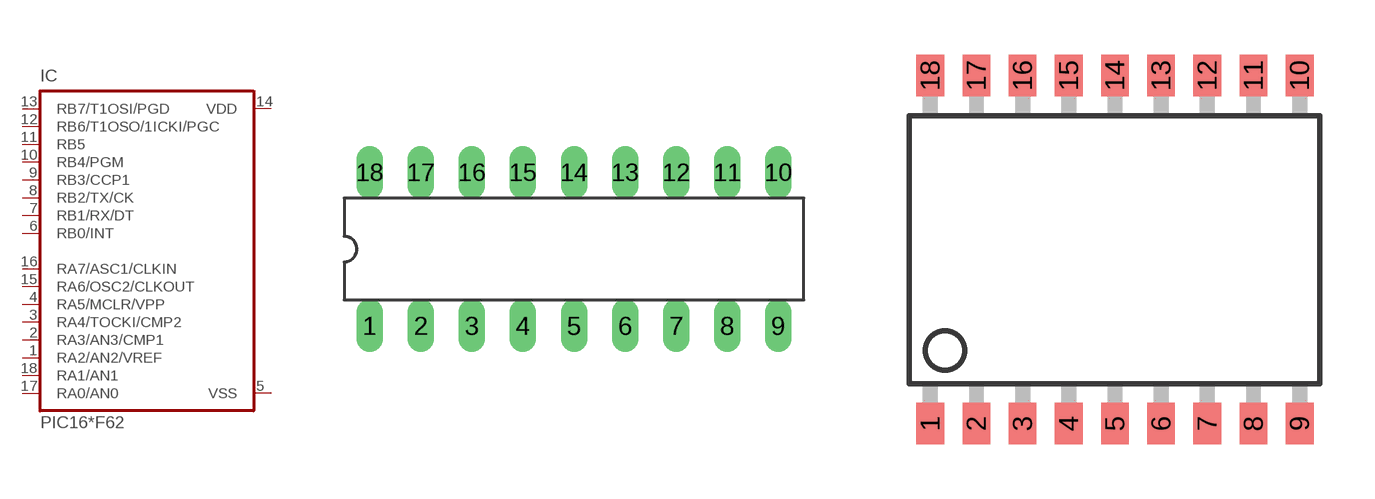
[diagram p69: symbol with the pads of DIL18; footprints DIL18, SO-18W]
Designator prefix IC

## PIC16F627P (MF: MICROCHIP; MPN: PIC16F627-20I/P; OC_FARNELL: 1084298; OC_NEWARK: 23C4967), PIC16LF627P (MF: MICROCHIP; MPN: PIC16LF627-04/P; OC_FARNELL: unknown; OC_NEWARK: 23C5660)  [DIL18]
1  RA2/AN2/VREF
2  RA3/AN3/CMP1
3  RA4/TOCKI/CMP2
4  RA5/MCLR/VPP  in
5  VSS  pwr
6  RB0/INT
7  RB1/RX/DT
8  RB2/TX/CK
9  RB3/CCP1
10  RB4/PGM
11  RB5
12  RB6/T1OSO/1ICKI/PGC
13  RB7/T1OSI/PGD
14  VDD  pwr
15  RA6/OSC2/CLKOUT
16  RA7/ASC1/CLKIN
17  RA0/AN0
18  RA1/AN1

## PIC16F627SO (MF: MICROCHIP; MPN: PIC16F627-04/SO; OC_FARNELL: 1084265; OC_NEWARK: 69K7632), PIC16LF627SO (MF: MICROCHIP; MPN: PIC16LF627A-I/SO; OC_FARNELL: 1579593; OC_NEWARK: 92C4841)  [SO-18W]
Pads as for DIL18

## PIC16F628P (MF: MICROCHIP; MPN: PIC16F628-20/P; OC_FARNELL: 9760423; OC_NEWARK: 23C4982), PIC16LF628P (MPN: PIC16LF628-04I/P; OC_FARNELL: 9761594; OC_NEWARK: 97K7476)  [DIL18]
Pads as for DIL18

## Footprint DIL18 (pad centres in mm)
Dual In Line package type P
drill 0.813 long: 1 -10.16,-3.81; 2 -7.62,-3.81; 3 -5.08,-3.81; 4 -2.54,-3.81; 5 0,-3.81; 6 2.54,-3.81; 7 5.08,-3.81; 8 7.62,-3.81; 9 10.16,-3.81; 10 10.16,3.81; 11 7.62,3.81; 12 5.08,3.81; 13 2.54,3.81; 14 0,3.81; 15 -2.54,3.81; 16 -5.08,3.81; 17 -7.62,3.81; 18 -10.16,3.81

## Footprint SO-18W (pad centres in mm)
Small Outline Wide Plastic Gull Wing 300-mil body, package type SO
smd 0.762 x 1.143: 1 -5.08,-4.788; 2 -3.81,-4.788; 3 -2.54,-4.788; 4 -1.27,-4.788; 5 0,-4.788; 6 1.27,-4.788; 7 2.54,-4.788; 8 3.81,-4.788; 9 5.08,-4.788; 10 5.08,4.788; 11 3.81,4.788; 12 2.54,4.788; 13 1.27,4.788; 14 0,4.788; 15 -1.27,4.788; 16 -2.54,4.788; 17 -3.81,4.788; 18 -5.08,4.788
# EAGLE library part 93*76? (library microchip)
8K Microwire Compatible Serial EEPROM Source: http://ww1.microchip.com/downloads/en/DeviceDoc/21796H.pdf

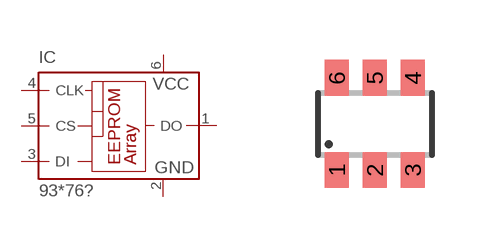
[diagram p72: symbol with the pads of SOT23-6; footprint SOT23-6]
Designator prefix IC

## 93AA76A (MPN: 93AA76AT-I/OT; OC_FARNELL: 1331443; OC_NEWARK: 35M2481), 93C76A (OC_FARNELL: unknown; OC_NEWARK: unknown), 93LC76A (MF: MICROCHIP; MPN: 93LC76AT-I/OT; OC_FARNELL: 1556170; OC_NEWARK: 61H6824)  [SOT23-6]
1  DO  hiz
2  GND  pwr
3  DI  in
4  CLK  in
5  CS  in
6  VCC  pwr

## 93AA76B (MPN: 93AA76BT-I/OT; OC_FARNELL: 1331444; OC_NEWARK: 35M2482), 93C76B (OC_FARNELL: unknown; OC_NEWARK: unknown), 93LC76B (MF: MICROCHIP; MPN: 93LC76BT-I/OT; OC_FARNELL: 1556170; OC_NEWARK: 61H6848)  [SOT23-6]
Pads as for SOT23-6

## Footprint SOT23-6 (pad centres in mm)
Small Outline Transistor 6 lead
smd 0.6 x 0.9: 1 -0.95,-1.15; 2 0,-1.15; 3 0.95,-1.15; 4 0.95,1.15; 5 0,1.15; 6 -0.95,1.15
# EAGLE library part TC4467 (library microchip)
Logic-Input CMOS Quad Drivers Source: TC 4469-MOSFET-DRIVER.pdf

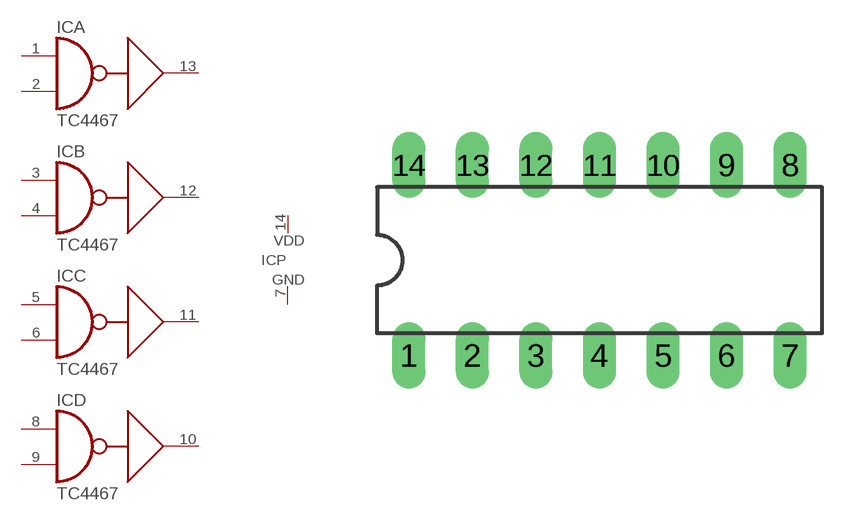
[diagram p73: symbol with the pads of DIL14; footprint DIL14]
Designator prefix IC; gates A=TC4467 B=TC4467 C=TC4467 D=TC4467 P=VDD-GND

## TC4467DP (MF: MICROCHIP; MPN: TC4467CPD; OC_FARNELL: unknown; OC_NEWARK: 92C6150)  [DIL14]
1  A:A  in
2  A:B  in
3  B:A  in
4  B:B  in
5  C:A  in
6  C:B  in
7  P:GND  pwr
8  D:A  in
9  D:B  in
10  D:Y  out
11  C:Y  out
12  B:Y  out
13  A:Y  out
14  P:VDD  pwr

## TC4467JD (MF: MICROCHIP; MPN: TC4467CPD; OC_FARNELL: unknown; OC_NEWARK: 92C6150)  [DIL14]
Pads as for DIL14

## Footprint DIL14 (pad centres in mm)
Dual In Line Package
drill 0.813 long: 1 -7.62,-3.81; 2 -5.08,-3.81; 3 -2.54,-3.81; 4 0,-3.81; 5 2.54,-3.81; 6 5.08,-3.81; 7 7.62,-3.81; 8 7.62,3.81; 9 5.08,3.81; 10 2.54,3.81; 11 0,3.81; 12 -2.54,3.81; 13 -5.08,3.81; 14 -7.62,3.81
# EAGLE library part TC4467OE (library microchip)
Logic-Input CMOS Quad Drivers Source: TC 4469-MOSFET-DRIVER.pdf

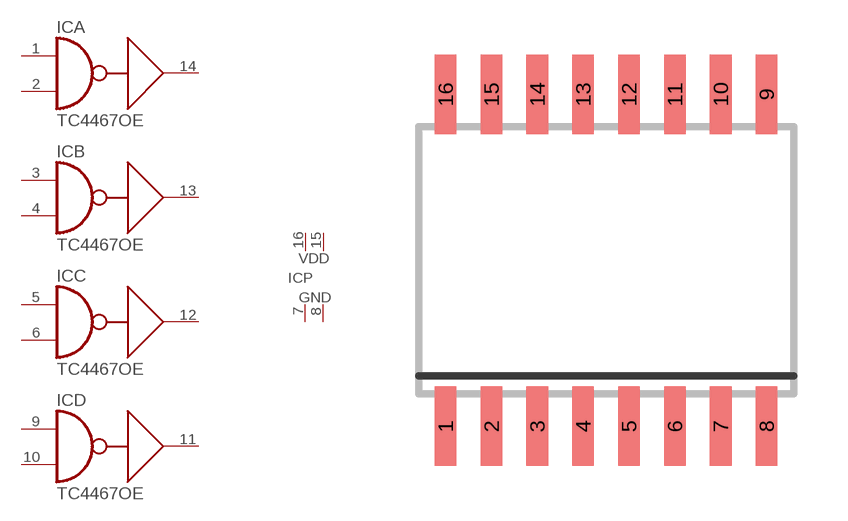
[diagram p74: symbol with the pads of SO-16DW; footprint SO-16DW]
Designator prefix IC; gates A=TC4467 B=TC4467 C=TC4467 D=TC4467 P=VDD-GND-2

## TC4467OE (MF: MICROCHIP; MPN: TC4467COE; OC_FARNELL: 1836408; OC_NEWARK: 92C6148)  [SO-16DW]
1  A:A  in
2  A:B  in
3  B:A  in
4  B:B  in
5  C:A  in
6  C:B  in
7  P:GND  pwr
8  P:GND  pwr
9  D:A  in
10  D:B  in
11  D:Y  out
12  C:Y  out
13  B:Y  out
14  A:Y  out
15  P:VDD  pwr
16  P:VDD  pwr

## Footprint SO-16DW (pad centres in mm)
Small Outline Integrated Circuit wide
smd 0.6 x 2.2: 1 -4.445,-4.6; 2 -3.175,-4.6; 3 -1.905,-4.6; 4 -0.635,-4.6; 5 0.635,-4.6; 6 1.905,-4.6; 7 3.175,-4.6; 8 4.445,-4.6; 9 4.445,4.6; 10 3.175,4.6; 11 1.905,4.6; 12 0.635,4.6; 13 -0.635,4.6; 14 -1.905,4.6; 15 -3.175,4.6; 16 -4.445,4.6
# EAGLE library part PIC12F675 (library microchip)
8-Pin FLASH-Based 8-Bit CMOS Microcontroller Precision Internal 4 MHz oscillator factory calibrated to ±1% Low Power Features: Standby Current: - 1 nA @ 2.0V, typical Operating Current: - 8.5&micro;A @ 32 kHz, 2.0V, typical - 100&micro;A @ 1 MHz, 2.0V, typical Watchdog Timer Current: - 300 nA @ 2.0V, typical Timer1 oscillator current: - 4&micro;A @ 32 kHz, 2.0V, typical Analog-to-Digital Converter module: - 10-bit resolution - Programmable 4-channel input - Voltage reference input Source: http://www.microchip.com .. 41190E.pdf

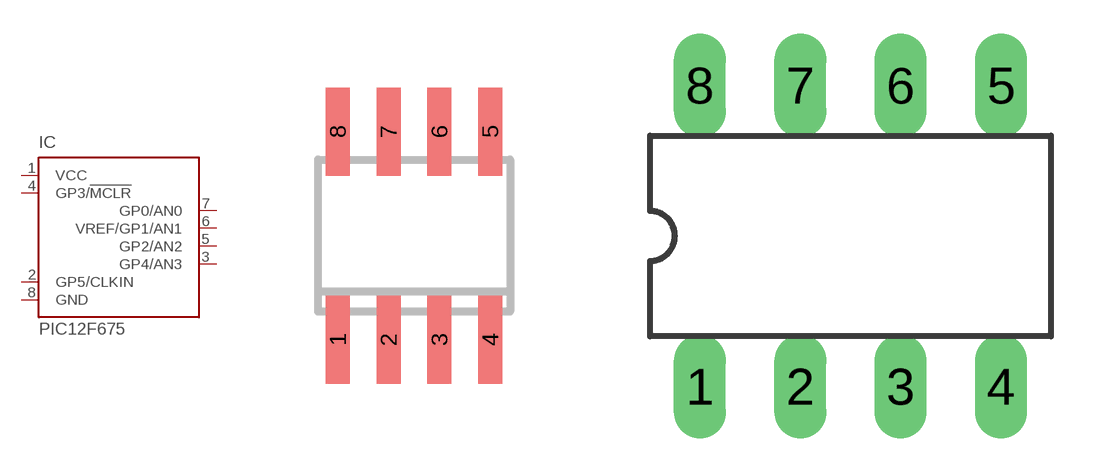
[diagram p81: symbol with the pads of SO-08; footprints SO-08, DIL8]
Designator prefix IC

## PIC12F675SN (MF: MICROCHIP; MPN: PIC12F675-E/SN; OC_FARNELL: 9759026; OC_NEWARK: 92C4341)  [SO-08]
1  VCC  pwr
2  GP5/CLKIN
3  GP4/AN3
4  GP3/!MCLR  in
5  GP2/AN2
6  VREF/GP1/AN1
7  GP0/AN0
8  GND  pwr

## PIC12F675P (MF: MICROCHIP; MPN: PIC12F675-E/P; OC_FARNELL: 9759018; OC_NEWARK: 92C4340)  [DIL8]
Pads as for SO-08

## PIC12F675MF (MF: MICROCHIP; MPN: PIC12F675-I/MF; OC_FARNELL: unknown; OC_NEWARK: 96K3774)  [DFN-S]
Pads as for SO-08

## Footprint SO-08 (pad centres in mm)
Small Outline Narrow Plastic Gull Wing 150-mil body, package type SN
smd 0.6 x 2.2: 1 -1.905,-2.6; 2 -0.635,-2.6; 3 0.635,-2.6; 4 1.905,-2.6; 5 1.905,2.6; 6 0.635,2.6; 7 -0.635,2.6; 8 -1.905,2.6

## Footprint DIL8 (pad centres in mm)
Dual In Line package type P
drill 0.813 long: 1 -3.81,-3.81; 2 -1.27,-3.81; 3 1.27,-3.81; 4 3.81,-3.81; 5 3.81,3.81; 6 1.27,3.81; 7 -1.27,3.81; 8 -3.81,3.81

## Footprint DFN-S (pad centres in mm)
8-Lead Plastic Dual Flat No Lead Package (MF) 6x5 mm Body (DFN-S) Source: http://www.microchip.com .. 41190c.pdf
smd 0.6 x 0.4: 1 -2.69,1.905; 2 -2.69,0.635; 3 -2.69,-0.635; 4 -2.69,-1.905; 5 2.69,-1.905; 6 2.69,-0.635; 7 2.69,0.635; 8 2.69,1.905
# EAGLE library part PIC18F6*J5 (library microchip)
PIC18F87J50 Family 64/80-Pin High-Performance, 1-Mbit Flash USB Microcontrollers with nanoWatt Technology Source: http://ww1.microchip.com/downloads/en/DeviceDoc/39775b.pdf

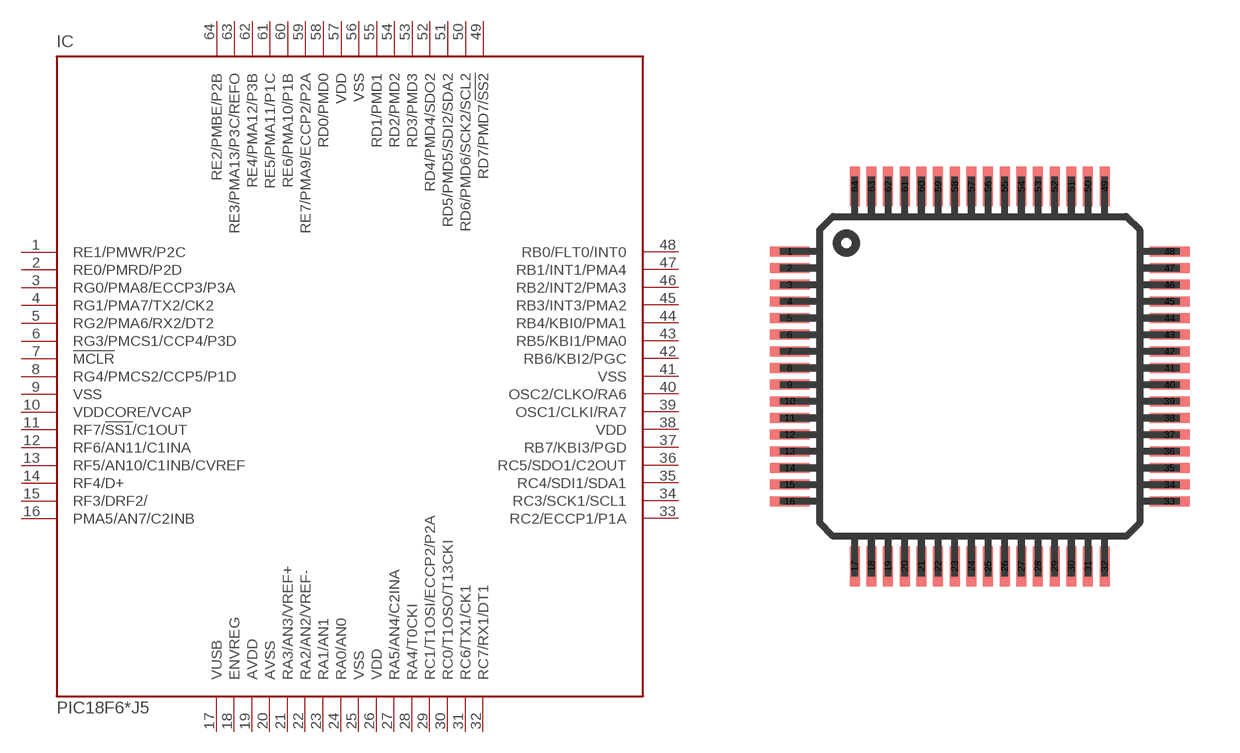
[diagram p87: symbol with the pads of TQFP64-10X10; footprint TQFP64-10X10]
Designator prefix IC

## PIC18F65J50 (MPN: PIC18F65J50-I/PT; OC_FARNELL: 1439552; OC_NEWARK: 17M0960), PIC18F66J50 (MPN: PIC18F66J50-I/PT; OC_FARNELL: 1439555; OC_NEWARK: 17M0966), PIC18F67J50 (MPN: PIC18F67J50-I/PT; OC_FARNELL: 1439559; OC_NEWARK: 17M0972)  [TQFP64-10X10]
1  RE1/PMWR/P2C
2  RE0/PMRD/P2D
3  RG0/PMA8/ECCP3/P3A
4  RG1/PMA7/TX2/CK2
5  RG2/PMA6/RX2/DT2
6  RG3/PMCS1/CCP4/P3D
7  !MCLR  in
8  RG4/PMCS2/CCP5/P1D
9  VSS  pwr
10  VDDCORE/VCAP
11  RF7/!SS1!/C1OUT
12  RF6/AN11/C1INA
13  RF5/AN10/C1INB/CVREF
14  RF4/D+
15  RF3/DRF2/
16  PMA5/AN7/C2INB
17  VUSB
18  ENVREG  in
19  AVDD
20  AVSS
21  RA3/AN3/VREF+
22  RA2/AN2/VREF-
23  RA1/AN1
24  RA0/AN0
25  VSS  pwr
26  VDD  pwr
27  RA5/AN4/C2INA
28  RA4/T0CKI
29  RC1/T1OSI/ECCP2/P2A
30  RC0/T1OSO/T13CKI
31  RC6/TX1/CK1
32  RC7/RX1/DT1
33  RC2/ECCP1/P1A
34  RC3/SCK1/SCL1
35  RC4/SDI1/SDA1
36  RC5/SDO1/C2OUT
37  RB7/KBI3/PGD
38  VDD  pwr
39  OSC1/CLKI/RA7
40  OSC2/CLKO/RA6
41  VSS  pwr
42  RB6/KBI2/PGC
43  RB5/KBI1/PMA0
44  RB4/KBI0/PMA1
45  RB3/INT3/PMA2
46  RB2/INT2/PMA3
47  RB1/INT1/PMA4
48  RB0/FLT0/INT0
49  RD7/PMD7/!SS2
50  RD6/PMD6/SCK2/SCL2
51  RD5/PMD5/SDI2/SDA2
52  RD4/PMD4/SDO2
53  RD3/PMD3
54  RD2/PMD2
55  RD1/PMD1
56  VSS  pwr
57  VDD  pwr
58  RD0/PMD0
59  RE7/PMA9/ECCP2/P2A
60  RE6/PMA10/P1B
61  RE5/PMA11/P1C
62  RE4/PMA12/P3B
63  RE3/PMA13/P3C/REFO
64  RE2/PMBE/P2B

## PIC18F66J55 (MPN: PIC18F66J55-I/PT; OC_FARNELL: 1439556; OC_NEWARK: 17M0968)  [TQFP64-10X10]
Pads as for TQFP64-10X10

## Footprint TQFP64-10X10 (pad centres in mm)
Thin Quad Flat Pack package type TQ
smd 1.2 x 0.3: 1 -5.7,3.75; 2 -5.7,3.25; 3 -5.7,2.75; 4 -5.7,2.25; 5 -5.7,1.75; 6 -5.7,1.25; 7 -5.7,0.75; 8 -5.7,0.25; 9 -5.7,-0.25; 10 -5.7,-0.75; 11 -5.7,-1.25; 12 -5.7,-1.75; 13 -5.7,-2.25; 14 -5.7,-2.75; 15 -5.7,-3.25; 16 -5.7,-3.75; 33 5.7,-3.75; 34 5.7,-3.25; 35 5.7,-2.75; 36 5.7,-2.25; 37 5.7,-1.75; 38 5.7,-1.25; 39 5.7,-0.75; 40 5.7,-0.25; 41 5.7,0.25; 42 5.7,0.75; 43 5.7,1.25; 44 5.7,1.75; 45 5.7,2.25; 46 5.7,2.75; 47 5.7,3.25; 48 5.7,3.75
smd 0.3 x 1.2: 17 -3.75,-5.7; 18 -3.25,-5.7; 19 -2.75,-5.7; 20 -2.25,-5.7; 21 -1.75,-5.7; 22 -1.25,-5.7; 23 -0.75,-5.7; 24 -0.25,-5.7; 25 0.25,-5.7; 26 0.75,-5.7; 27 1.25,-5.7; 28 1.75,-5.7; 29 2.25,-5.7; 30 2.75,-5.7; 31 3.25,-5.7; 32 3.75,-5.7; 49 3.75,5.7; 50 3.25,5.7; 51 2.75,5.7; 52 2.25,5.7; 53 1.75,5.7; 54 1.25,5.7; 55 0.75,5.7; 56 0.25,5.7; 57 -0.25,5.7; 58 -0.75,5.7; 59 -1.25,5.7; 60 -1.75,5.7; 61 -2.25,5.7; 62 -2.75,5.7; 63 -3.25,5.7; 64 -3.75,5.7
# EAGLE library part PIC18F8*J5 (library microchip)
PIC18F87J50 Family 64/80-Pin High-Performance, 1-Mbit Flash USB Microcontrollers with nanoWatt Technology Source: http://ww1.microchip.com/downloads/en/DeviceDoc/39775b.pdf

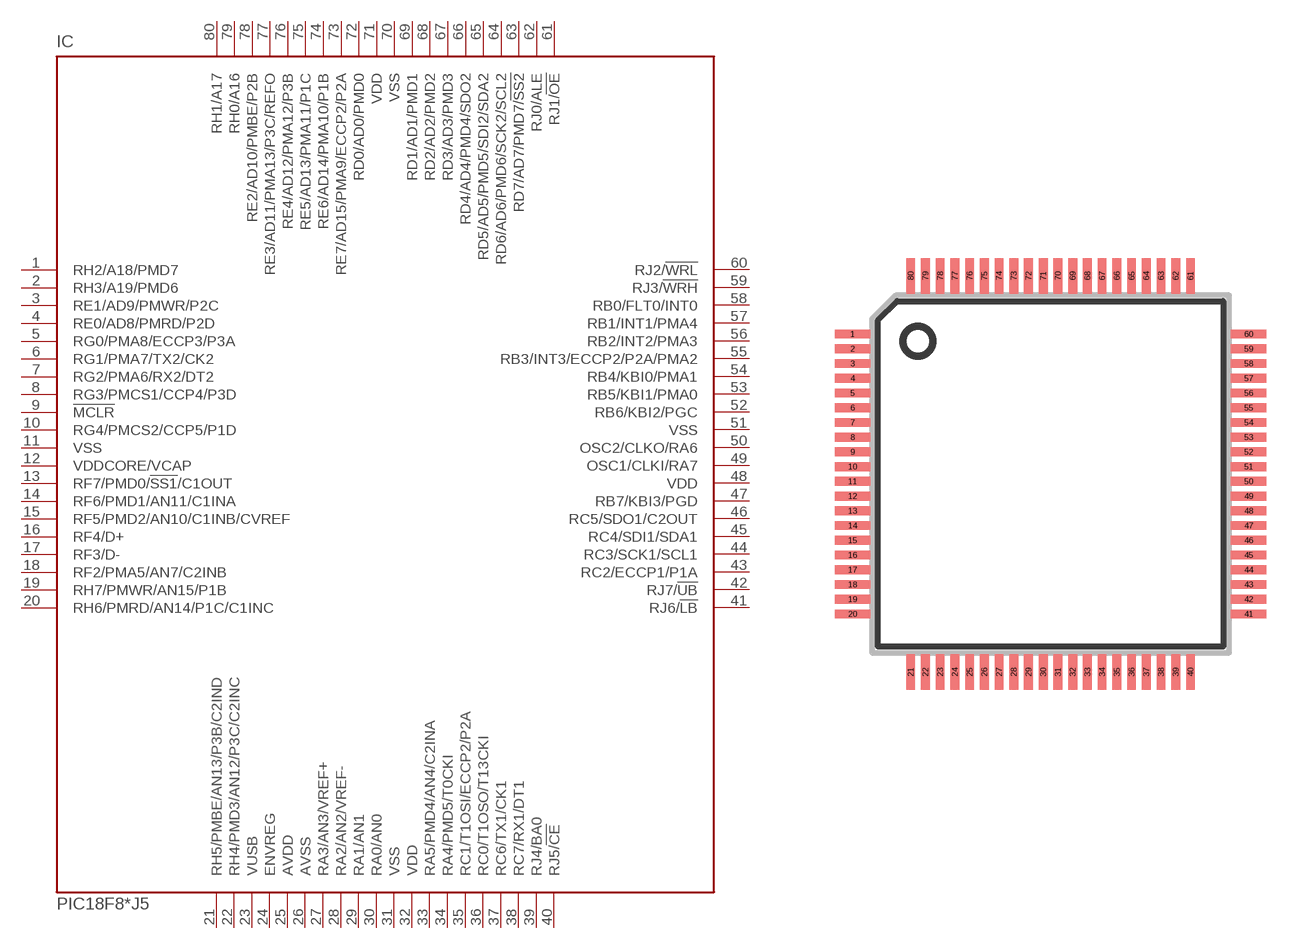
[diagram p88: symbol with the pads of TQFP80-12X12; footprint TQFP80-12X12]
Designator prefix IC

## PIC18F85J50 (MPN: PIC18F85J50-I/PT; OC_FARNELL: 1439565; OC_NEWARK: 59M1134), PIC18F86J50 (MPN: PIC18F86J50-I/PT; OC_FARNELL: 1439569; OC_NEWARK: 59M1137), PIC18F87J50 (MPN: PIC18F87J50-I/PT; OC_FARNELL: 1439572; OC_NEWARK: 17M0986)  [TQFP80-12X12]
1  RH2/A18/PMD7
2  RH3/A19/PMD6
3  RE1/AD9/PMWR/P2C
4  RE0/AD8/PMRD/P2D
5  RG0/PMA8/ECCP3/P3A
6  RG1/PMA7/TX2/CK2
7  RG2/PMA6/RX2/DT2
8  RG3/PMCS1/CCP4/P3D
9  !MCLR  in
10  RG4/PMCS2/CCP5/P1D
11  VSS  pwr
12  VDDCORE/VCAP
13  RF7/PMD0/!SS1!/C1OUT
14  RF6/PMD1/AN11/C1INA
15  RF5/PMD2/AN10/C1INB/CVREF
16  RF4/D+
17  RF3/D-
18  RF2/PMA5/AN7/C2INB
19  RH7/PMWR/AN15/P1B
20  RH6/PMRD/AN14/P1C/C1INC
21  RH5/PMBE/AN13/P3B/C2IND
22  RH4/PMD3/AN12/P3C/C2INC
23  VUSB  in
24  ENVREG  in
25  AVDD
26  AVSS
27  RA3/AN3/VREF+
28  RA2/AN2/VREF-
29  RA1/AN1
30  RA0/AN0
31  VSS  pwr
32  VDD  pwr
33  RA5/PMD4/AN4/C2INA
34  RA4/PMD5/T0CKI
35  RC1/T1OSI/ECCP2/P2A
36  RC0/T1OSO/T13CKI
37  RC6/TX1/CK1
38  RC7/RX1/DT1
39  RJ4/BA0
40  RJ5/!CE
41  RJ6/!LB
42  RJ7/!UB
43  RC2/ECCP1/P1A
44  RC3/SCK1/SCL1
45  RC4/SDI1/SDA1
46  RC5/SDO1/C2OUT
47  RB7/KBI3/PGD
48  VDD  pwr
49  OSC1/CLKI/RA7
50  OSC2/CLKO/RA6
51  VSS  pwr
52  RB6/KBI2/PGC
53  RB5/KBI1/PMA0
54  RB4/KBI0/PMA1
55  RB3/INT3/ECCP2/P2A/PMA2
56  RB2/INT2/PMA3
57  RB1/INT1/PMA4
58  RB0/FLT0/INT0
59  RJ3/!WRH
60  RJ2/!WRL
61  RJ1/!OE
62  RJ0/ALE
63  RD7/AD7/PMD7/!SS2
64  RD6/AD6/PMD6/SCK2/SCL2
65  RD5/AD5/PMD5/SDI2/SDA2
66  RD4/AD4/PMD4/SDO2
67  RD3/AD3/PMD3
68  RD2/AD2/PMD2
69  RD1/AD1/PMD1
70  VSS  pwr
71  VDD  pwr
72  RD0/AD0/PMD0
73  RE7/AD15/PMA9/ECCP2/P2A
74  RE6/AD14/PMA10/P1B
75  RE5/AD13/PMA11/P1C
76  RE4/AD12/PMA12/P3B
77  RE3/AD11/PMA13/P3C/REFO
78  RE2/AD10/PMBE/P2B
79  RH0/A16
80  RH1/A17

## PIC18F86J55 (MPN: PIC18F86J55-I/PT; OC_FARNELL: unknown; OC_NEWARK: 17M0982)  [TQFP80-12X12]
Pads as for TQFP80-12X12

## Footprint TQFP80-12X12 (pad centres in mm)
TQFP80 12x12x1 mm Body Source: http://www.microchip.com/ .. 39663c.pdf
smd 1.2 x 0.3: 1 -6.725,4.75; 2 -6.725,4.25; 3 -6.725,3.75; 4 -6.725,3.25; 5 -6.725,2.75; 6 -6.725,2.25; 7 -6.725,1.75; 8 -6.725,1.25; 9 -6.725,0.75; 10 -6.725,0.25; 11 -6.725,-0.25; 12 -6.725,-0.75; 13 -6.725,-1.25; 14 -6.725,-1.75; 15 -6.725,-2.25; 16 -6.725,-2.75; 17 -6.725,-3.25; 18 -6.725,-3.75; 19 -6.725,-4.25; 20 -6.725,-4.75; 41 6.725,-4.75; 42 6.725,-4.25; 43 6.725,-3.75; 44 6.725,-3.25; 45 6.725,-2.75; 46 6.725,-2.25; 47 6.725,-1.75; 48 6.725,-1.25; 49 6.725,-0.75; 50 6.725,-0.25; 51 6.725,0.25; 52 6.725,0.75; 53 6.725,1.25; 54 6.725,1.75; 55 6.725,2.25; 56 6.725,2.75; 57 6.725,3.25; 58 6.725,3.75; 59 6.725,4.25; 60 6.725,4.75
smd 0.3 x 1.2: 21 -4.75,-6.725; 22 -4.25,-6.725; 23 -3.75,-6.725; 24 -3.25,-6.725; 25 -2.75,-6.725; 26 -2.25,-6.725; 27 -1.75,-6.725; 28 -1.25,-6.725; 29 -0.75,-6.725; 30 -0.25,-6.725; 31 0.25,-6.725; 32 0.75,-6.725; 33 1.25,-6.725; 34 1.75,-6.725; 35 2.25,-6.725; 36 2.75,-6.725; 37 3.25,-6.725; 38 3.75,-6.725; 39 4.25,-6.725; 40 4.75,-6.725; 61 4.75,6.725; 62 4.25,6.725; 63 3.75,6.725; 64 3.25,6.725; 65 2.75,6.725; 66 2.25,6.725; 67 1.75,6.725; 68 1.25,6.725; 69 0.75,6.725; 70 0.25,6.725; 71 -0.25,6.725; 72 -0.75,6.725; 73 -1.25,6.725; 74 -1.75,6.725; 75 -2.25,6.725; 76 -2.75,6.725; 77 -3.25,6.725; 78 -3.75,6.725; 79 -4.25,6.725; 80 -4.75,6.725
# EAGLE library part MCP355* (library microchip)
Low-Power, Single-Channel 22-Bit Delta-Sigma ADCs Source: http://ww1.microchip.com/downloads/en/DeviceDoc/21950c.pdf

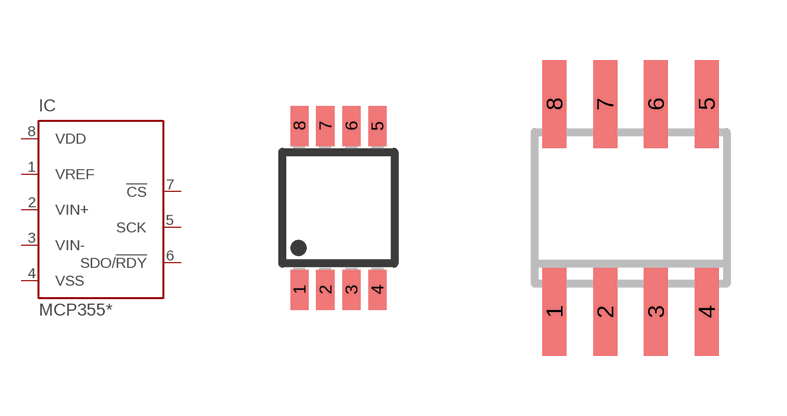
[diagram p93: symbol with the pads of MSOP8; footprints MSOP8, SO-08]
Designator prefix IC

## MCP3550-50MS (MF: MICROCHIP; MPN: MCP3550-50E/MS; OC_FARNELL: 1627198; OC_NEWARK: 69K0130), MCP3550-60MS (MF: MICROCHIP; MPN: MCP3550-60E/MS; OC_FARNELL: 1840933; OC_NEWARK: 69K0134), MCP3551MS (MF: MICROCHIP; MPN: MCP3551-E/MS; OC_FARNELL: 1084624; OC_NEWARK: 22K1368), MCP3553MS (MPN: MCP3553-E/MS; OC_FARNELL: 1439515; OC_NEWARK: 56K7003)  [MSOP8]
1  VREF  in
2  VIN+  in
3  VIN-  in
4  VSS  pwr
5  SCK  in
6  SDO/!RDY  out
7  !CS  in
8  VDD  pwr

## MCP3550-50SN (MF: MICROCHIP; MPN: MCP3550-50-E/SN; OC_FARNELL: 1557411; OC_NEWARK: 69K0131), MCP3550-60SN (MF: MICROCHIP; MPN: MCP3550-60E/SN; OC_FARNELL: 1840934; OC_NEWARK: 69K0135), MCP3551SN (MPN: MCP3551-E/SN; OC_FARNELL: 1084625; OC_NEWARK: 97K4494), MCP3553SN (MF: MICROCHIP; MPN: MCP3553-E/SN; OC_FARNELL: 1605569; OC_NEWARK: 56K7004)  [SO-08]
Pads as for MSOP8

## Footprint MSOP8 (pad centres in mm)
Micro Small Outline Package Grid 0.65mm Source: http://ww1.microchip.com/downloads/en/DeviceDoc/21796H.pdf
smd 0.45 x 1: 1 -0.975,-2.05; 2 -0.325,-2.05; 3 0.325,-2.05; 4 0.975,-2.05; 5 0.975,2.05; 6 0.325,2.05; 7 -0.325,2.05; 8 -0.975,2.05

## Footprint SO-08 (pad centres in mm)
Small Outline Narrow Plastic Gull Wing 150-mil body, package type SN
smd 0.6 x 2.2: 1 -1.905,-2.6; 2 -0.635,-2.6; 3 0.635,-2.6; 4 1.905,-2.6; 5 1.905,2.6; 6 0.635,2.6; 7 -0.635,2.6; 8 -1.905,2.6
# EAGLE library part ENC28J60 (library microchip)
Stand-Alone Ethernet Controller with SPI Interface Source: http://ww1.microchip.com/downloads/en/DeviceDoc/39662c.pdf

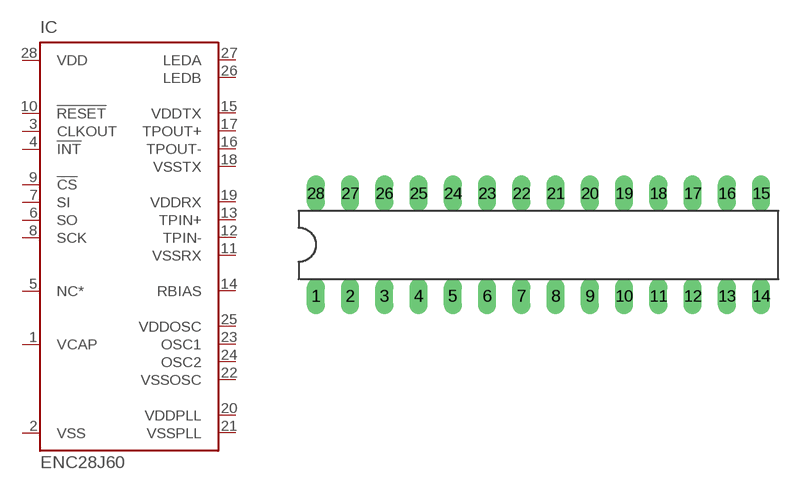
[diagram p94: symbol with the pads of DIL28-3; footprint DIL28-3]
Designator prefix IC

## ENC28J60SP (MF: MICROCHIP; MPN: ENC28J60/SP; OC_FARNELL: 1084619; OC_NEWARK: 96K3661)  [DIL28-3]
1  VCAP  in
2  VSS  in
3  CLKOUT  out
4  !INT  out
5  NC*  out
6  SO  out
7  SI  in
8  SCK  in
9  !CS  in
10  !RESET  in
11  VSSRX  in
12  TPIN-  in
13  TPIN+  in
14  RBIAS  in
15  VDDTX  in
16  TPOUT-  out
17  TPOUT+  out
18  VSSTX  in
19  VDDRX  in
20  VDDPLL  in
21  VSSPLL  in
22  VSSOSC  in
23  OSC1  in
24  OSC2  out
25  VDDOSC  in
26  LEDB  out
27  LEDA  out
28  VDD  in

## Footprint DIL28-3 (pad centres in mm)
Dual In Line package type P
drill 0.813 long: 1 -16.51,-3.81; 2 -13.97,-3.81; 3 -11.43,-3.81; 4 -8.89,-3.81; 5 -6.35,-3.81; 6 -3.81,-3.81; 7 -1.27,-3.81; 8 1.27,-3.81; 9 3.81,-3.81; 10 6.35,-3.81; 11 8.89,-3.81; 12 11.43,-3.81; 13 13.97,-3.81; 14 16.51,-3.81; 15 16.51,3.81; 16 13.97,3.81; 17 11.43,3.81; 18 8.89,3.81; 19 6.35,3.81; 20 3.81,3.81; 21 1.27,3.81; 22 -1.27,3.81; 23 -3.81,3.81; 24 -6.35,3.81; 25 -8.89,3.81; 26 -11.43,3.81; 27 -13.97,3.81; 28 -16.51,3.81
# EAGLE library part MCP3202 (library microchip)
2.7V Dual Channel 12-Bit A/D Converter with SPI Serial Interface Source: http://ww1.microchip.com/downloads/en/DeviceDoc/21034D.pdf

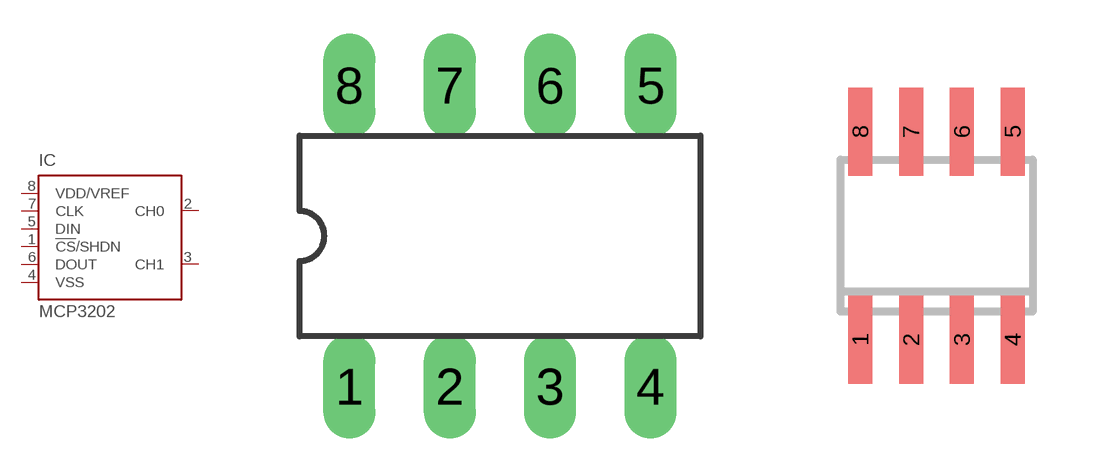
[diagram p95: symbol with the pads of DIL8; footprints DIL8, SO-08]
Designator prefix IC

## MCP3202P (MF: MICROCHIP; MPN: MCP3202-CI/P; OC_FARNELL: 1196794; OC_NEWARK: 72K7287)  [DIL8]
1  !CS!/SHDN  in
2  CH0  in
3  CH1  in
4  VSS  in
5  DIN  in
6  DOUT  in
7  CLK  in
8  VDD/VREF  in

## MCP3202SN (MF: MICROCHIP; MPN: MCP3202-CI/SN; OC_FARNELL: 1196803; OC_NEWARK: 19C7207)  [SO-08]
Pads as for DIL8

## MCP3202MS (MF: MICROCHIP; MPN: MCP3202-CI/MS; OC_FARNELL: unknown; OC_NEWARK: 68H9370)  [MSOP8]
Pads as for DIL8

## MCP3202ST (MF: MICROCHIP; MPN: MCP3202-CI/ST; OC_FARNELL: unknown; OC_NEWARK: 59K0226)  [TSSOP8]
Pads as for DIL8

## Footprint DIL8 (pad centres in mm)
Dual In Line package type P
drill 0.813 long: 1 -3.81,-3.81; 2 -1.27,-3.81; 3 1.27,-3.81; 4 3.81,-3.81; 5 3.81,3.81; 6 1.27,3.81; 7 -1.27,3.81; 8 -3.81,3.81

## Footprint SO-08 (pad centres in mm)
Small Outline Narrow Plastic Gull Wing 150-mil body, package type SN
smd 0.6 x 2.2: 1 -1.905,-2.6; 2 -0.635,-2.6; 3 0.635,-2.6; 4 1.905,-2.6; 5 1.905,2.6; 6 0.635,2.6; 7 -0.635,2.6; 8 -1.905,2.6

## Footprint MSOP8 (pad centres in mm)
Micro Small Outline Package Grid 0.65mm Source: http://ww1.microchip.com/downloads/en/DeviceDoc/21796H.pdf
smd 0.45 x 1: 1 -0.975,-2.05; 2 -0.325,-2.05; 3 0.325,-2.05; 4 0.975,-2.05; 5 0.975,2.05; 6 0.325,2.05; 7 -0.325,2.05; 8 -0.975,2.05

## Footprint TSSOP8 (pad centres in mm)
Thin Shrink Small Outline Package package type ST
smd 0.35 x 1.2: 1 -0.975,-2.925; 2 -0.325,-2.925; 3 0.325,-2.925; 4 0.975,-2.925; 5 0.975,2.925; 6 0.325,2.925; 7 -0.325,2.925; 8 -0.975,2.925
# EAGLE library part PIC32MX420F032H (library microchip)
PIC32MX420F032H edit this description Auto generated by make-symbol-device-package-bsdl.ulp Rev. 25 Source: PIC32MX420F032H.bsdl

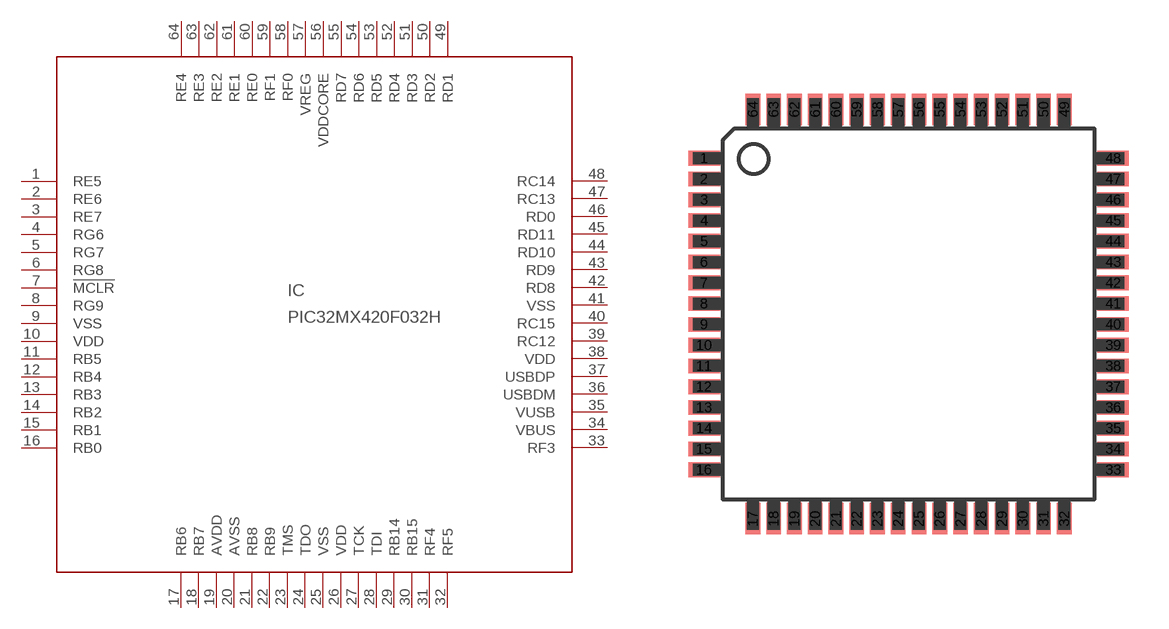
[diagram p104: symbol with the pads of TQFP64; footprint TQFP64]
Designator prefix IC

## PIC32MX420F032H (MPN: PIC32MX420F032H-40I/PT; OC_FARNELL: 1640230; OC_NEWARK: 98M1932)  [TQFP64]
1  RE5
2  RE6
3  RE7
4  RG6
5  RG7
6  RG8
7  !MCLR  in
8  RG9
9  VSS  pwr
10  VDD  pwr
11  RB5
12  RB4
13  RB3
14  RB2
15  RB1
16  RB0
17  RB6
18  RB7
19  AVDD  pwr
20  AVSS  pwr
21  RB8
22  RB9
23  TMS  in
24  TDO  out
25  VSS  pwr
26  VDD  pwr
27  TCK  in
28  TDI  in
29  RB14
30  RB15
31  RF4
32  RF5
33  RF3
34  VBUS
35  VUSB  pas
36  USBDM
37  USBDP
38  VDD  pwr
39  RC12
40  RC15
41  VSS  pwr
42  RD8
43  RD9
44  RD10
45  RD11
46  RD0
47  RC13
48  RC14
49  RD1
50  RD2
51  RD3
52  RD4
53  RD5
54  RD6
55  RD7
56  VDDCORE  pwr
57  VREG  pas
58  RF0
59  RF1
60  RE0
61  RE1
62  RE2
63  RE3
64  RE4

## Footprint TQFP64 (pad centres in mm)
Thin Quad Flat Pack
smd 1.194 x 0.559: 1 -7.76,5.905; 2 -7.76,5.118; 3 -7.76,4.331; 4 -7.76,3.543; 5 -7.76,2.756; 6 -7.76,1.968; 7 -7.76,1.181; 8 -7.76,0.394; 9 -7.76,-0.394; 10 -7.76,-1.181; 11 -7.76,-1.968; 12 -7.76,-2.756; 13 -7.76,-3.543; 14 -7.76,-4.331; 15 -7.76,-5.118; 16 -7.76,-5.905; 33 7.76,-5.905; 34 7.76,-5.118; 35 7.76,-4.331; 36 7.76,-3.543; 37 7.76,-2.756; 38 7.76,-1.968; 39 7.76,-1.181; 40 7.76,-0.394; 41 7.76,0.394; 42 7.76,1.181; 43 7.76,1.968; 44 7.76,2.756; 45 7.76,3.543; 46 7.76,4.331; 47 7.76,5.118; 48 7.76,5.905
smd 0.559 x 1.194: 17 -5.905,-7.76; 18 -5.118,-7.76; 19 -4.331,-7.76; 20 -3.543,-7.76; 21 -2.756,-7.76; 22 -1.968,-7.76; 23 -1.181,-7.76; 24 -0.394,-7.76; 25 0.394,-7.76; 26 1.181,-7.76; 27 1.968,-7.76; 28 2.756,-7.76; 29 3.543,-7.76; 30 4.331,-7.76; 31 5.118,-7.76; 32 5.905,-7.76; 49 5.905,7.76; 50 5.118,7.76; 51 4.331,7.76; 52 3.543,7.76; 53 2.756,7.76; 54 1.968,7.76; 55 1.181,7.76; 56 0.394,7.76; 57 -0.394,7.76; 58 -1.181,7.76; 59 -1.968,7.76; 60 -2.756,7.76; 61 -3.543,7.76; 62 -4.331,7.76; 63 -5.118,7.76; 64 -5.905,7.76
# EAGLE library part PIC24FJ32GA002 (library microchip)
PIC24FJ32GA002 edit this description Auto generated by make-symbol-device-package-bsdl.ulp Rev. 25 Source: PIC24FJ32GA002.bsd

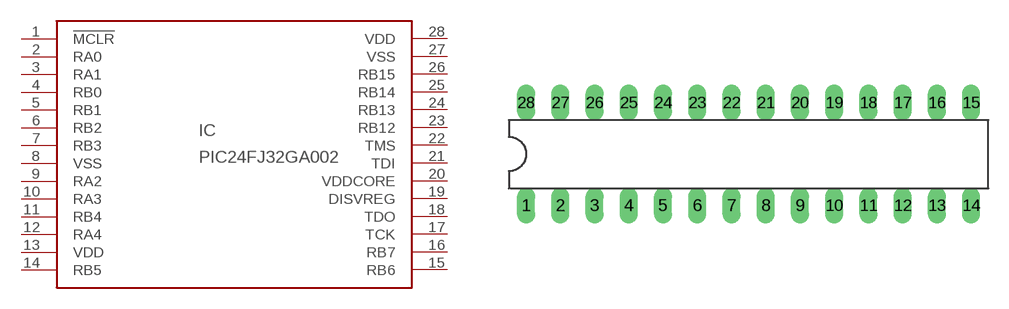
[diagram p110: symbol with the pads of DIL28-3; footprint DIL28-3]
Designator prefix IC

## PIC24FJ32GA002 (MPN: PIC24FJ32GA002-I/SP; OC_FARNELL: 1332294; OC_NEWARK: 88K6123)  [DIL28-3]
1  !MCLR
2  RA0
3  RA1
4  RB0
5  RB1
6  RB2
7  RB3
8  VSS  pwr
9  RA2
10  RA3
11  RB4
12  RA4
13  VDD  pwr
14  RB5
15  RB6
16  RB7
17  TCK  in
18  TDO  out
19  DISVREG  pas
20  VDDCORE  pwr
21  TDI  in
22  TMS  in
23  RB12
24  RB13
25  RB14
26  RB15
27  VSS  pwr
28  VDD  pwr

## Footprint DIL28-3 (pad centres in mm)
Dual In Line package type P
drill 0.813 long: 1 -16.51,-3.81; 2 -13.97,-3.81; 3 -11.43,-3.81; 4 -8.89,-3.81; 5 -6.35,-3.81; 6 -3.81,-3.81; 7 -1.27,-3.81; 8 1.27,-3.81; 9 3.81,-3.81; 10 6.35,-3.81; 11 8.89,-3.81; 12 11.43,-3.81; 13 13.97,-3.81; 14 16.51,-3.81; 15 16.51,3.81; 16 13.97,3.81; 17 11.43,3.81; 18 8.89,3.81; 19 6.35,3.81; 20 3.81,3.81; 21 1.27,3.81; 22 -1.27,3.81; 23 -3.81,3.81; 24 -6.35,3.81; 25 -8.89,3.81; 26 -11.43,3.81; 27 -13.97,3.81; 28 -16.51,3.81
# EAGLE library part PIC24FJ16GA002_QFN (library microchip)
PIC24FJ16GA002_QFN edit this description Auto generated by make-symbol-device-package-bsdl.ulp Rev. 25 Source: PIC24FJ16GA002_QFN.bsd

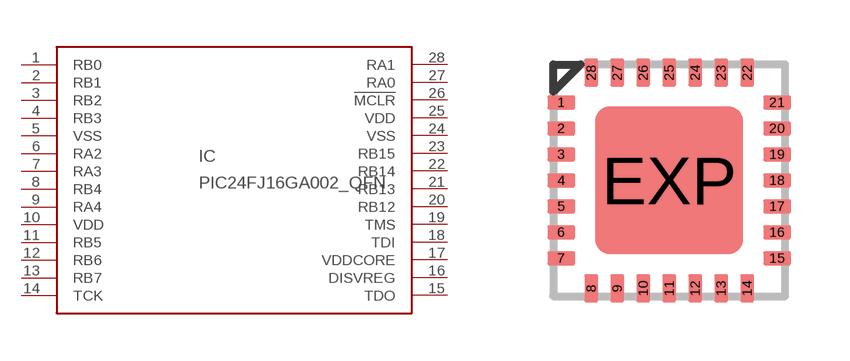
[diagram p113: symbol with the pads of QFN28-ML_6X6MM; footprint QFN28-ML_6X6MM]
Designator prefix IC

## PIC24FJ16GA002_QFN (MPN: PIC24FJ16GA002-I/ML; OC_FARNELL: unknown; OC_NEWARK: 40M1425)  [QFN28-ML_6X6MM]
1  RB0
2  RB1
3  RB2
4  RB3
5  VSS  pwr
6  RA2
7  RA3
8  RB4
9  RA4
10  VDD  pwr
11  RB5
12  RB6
13  RB7
14  TCK  in
15  TDO  out
16  DISVREG  pas
17  VDDCORE  pwr
18  TDI  in
19  TMS  in
20  RB12
21  RB13
22  RB14
23  RB15
24  VSS  pwr
25  VDD  pwr
26  !MCLR
27  RA0
28  RA1

## Footprint QFN28-ML_6X6MM (pad centres in mm)
QFN28-ML_6X6MM Source: http://www.microchip.com .. 39637a.pdf
smd 0.7 x 0.35: 1 -2.7,1.95; 2 -2.7,1.3; 3 -2.7,0.65; 4 -2.7,0; 5 -2.7,-0.65; 6 -2.7,-1.3; 7 -2.7,-1.95; 15 2.7,-1.95; 16 2.7,-1.3; 17 2.7,-0.65; 18 2.7,0; 19 2.7,0.65; 20 2.7,1.3; 21 2.7,1.95
smd 0.35 x 0.7: 8 -1.95,-2.7; 9 -1.3,-2.7; 10 -0.65,-2.7; 11 0,-2.7; 12 0.65,-2.7; 13 1.3,-2.7; 14 1.95,-2.7; 22 1.95,2.7; 23 1.3,2.7; 24 0.65,2.7; 25 0,2.7; 26 -0.65,2.7; 27 -1.3,2.7; 28 -1.95,2.7
smd 3.7 x 3.7: EXP 0,0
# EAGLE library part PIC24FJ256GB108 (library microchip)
PIC24FJ256GB108 edit this description Auto generated by make-symbol-device-package-bsdl.ulp Rev. 25 Source: PIC24FJ256GB108.bsd

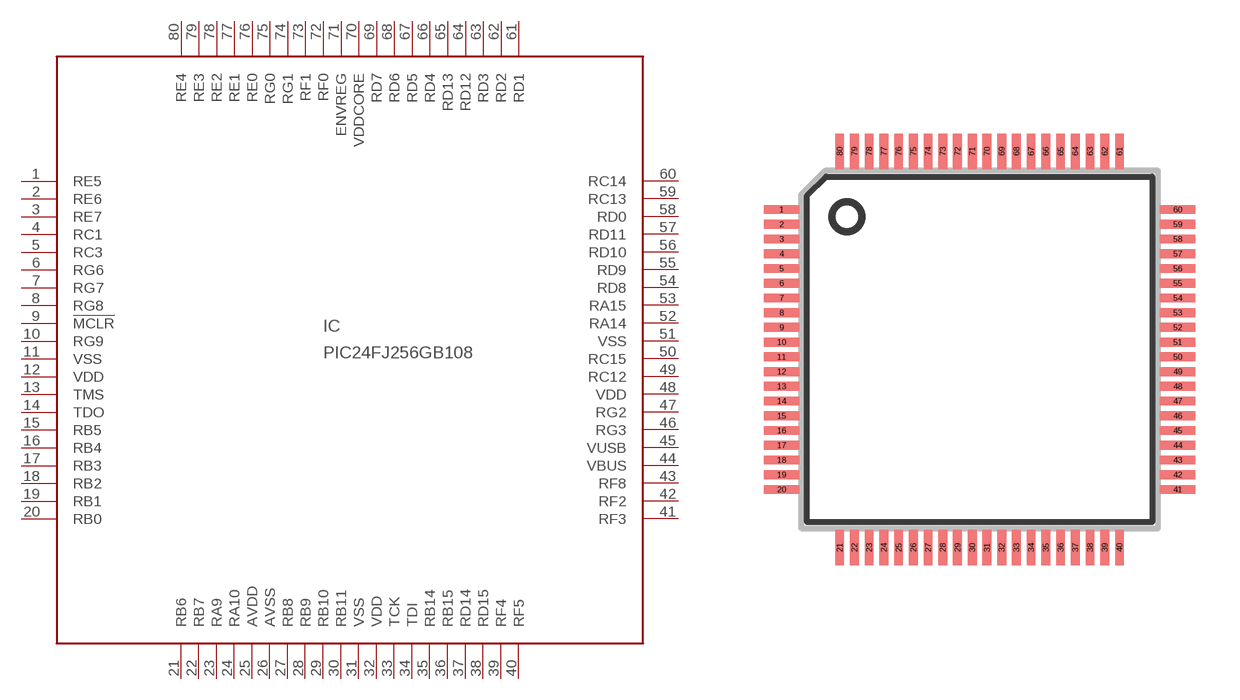
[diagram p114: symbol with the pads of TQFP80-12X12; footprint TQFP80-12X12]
Designator prefix IC

## PIC24FJ256GB108 (MPN: PIC24FJ256GB108-I/PT; OC_FARNELL: 1576869; OC_NEWARK: 54M5131)  [TQFP80-12X12]
1  RE5
2  RE6
3  RE7
4  RC1
5  RC3
6  RG6
7  RG7
8  RG8
9  !MCLR
10  RG9
11  VSS  pwr
12  VDD  pwr
13  TMS  in
14  TDO  out
15  RB5
16  RB4
17  RB3
18  RB2
19  RB1
20  RB0
21  RB6
22  RB7
23  RA9
24  RA10
25  AVDD  pwr
26  AVSS  pwr
27  RB8
28  RB9
29  RB10
30  RB11
31  VSS  pwr
32  VDD  pwr
33  TCK  in
34  TDI  in
35  RB14
36  RB15
37  RD14
38  RD15
39  RF4
40  RF5
41  RF3
42  RF2
43  RF8
44  VBUS  pas
45  VUSB  pas
46  RG3
47  RG2
48  VDD  pwr
49  RC12
50  RC15
51  VSS  pwr
52  RA14
53  RA15
54  RD8
55  RD9
56  RD10
57  RD11
58  RD0
59  RC13
60  RC14
61  RD1
62  RD2
63  RD3
64  RD12
65  RD13
66  RD4
67  RD5
68  RD6
69  RD7
70  VDDCORE  pwr
71  ENVREG  pas
72  RF0
73  RF1
74  RG1
75  RG0
76  RE0
77  RE1
78  RE2
79  RE3
80  RE4

## Footprint TQFP80-12X12 (pad centres in mm)
TQFP80 12x12x1 mm Body Source: http://www.microchip.com/ .. 39663c.pdf
smd 1.2 x 0.3: 1 -6.725,4.75; 2 -6.725,4.25; 3 -6.725,3.75; 4 -6.725,3.25; 5 -6.725,2.75; 6 -6.725,2.25; 7 -6.725,1.75; 8 -6.725,1.25; 9 -6.725,0.75; 10 -6.725,0.25; 11 -6.725,-0.25; 12 -6.725,-0.75; 13 -6.725,-1.25; 14 -6.725,-1.75; 15 -6.725,-2.25; 16 -6.725,-2.75; 17 -6.725,-3.25; 18 -6.725,-3.75; 19 -6.725,-4.25; 20 -6.725,-4.75; 41 6.725,-4.75; 42 6.725,-4.25; 43 6.725,-3.75; 44 6.725,-3.25; 45 6.725,-2.75; 46 6.725,-2.25; 47 6.725,-1.75; 48 6.725,-1.25; 49 6.725,-0.75; 50 6.725,-0.25; 51 6.725,0.25; 52 6.725,0.75; 53 6.725,1.25; 54 6.725,1.75; 55 6.725,2.25; 56 6.725,2.75; 57 6.725,3.25; 58 6.725,3.75; 59 6.725,4.25; 60 6.725,4.75
smd 0.3 x 1.2: 21 -4.75,-6.725; 22 -4.25,-6.725; 23 -3.75,-6.725; 24 -3.25,-6.725; 25 -2.75,-6.725; 26 -2.25,-6.725; 27 -1.75,-6.725; 28 -1.25,-6.725; 29 -0.75,-6.725; 30 -0.25,-6.725; 31 0.25,-6.725; 32 0.75,-6.725; 33 1.25,-6.725; 34 1.75,-6.725; 35 2.25,-6.725; 36 2.75,-6.725; 37 3.25,-6.725; 38 3.75,-6.725; 39 4.25,-6.725; 40 4.75,-6.725; 61 4.75,6.725; 62 4.25,6.725; 63 3.75,6.725; 64 3.25,6.725; 65 2.75,6.725; 66 2.25,6.725; 67 1.75,6.725; 68 1.25,6.725; 69 0.75,6.725; 70 0.25,6.725; 71 -0.25,6.725; 72 -0.75,6.725; 73 -1.25,6.725; 74 -1.75,6.725; 75 -2.25,6.725; 76 -2.75,6.725; 77 -3.25,6.725; 78 -3.75,6.725; 79 -4.25,6.725; 80 -4.75,6.725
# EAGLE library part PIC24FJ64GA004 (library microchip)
PIC24FJ64GA004 edit this description Auto generated by make-symbol-device-package-bsdl.ulp Rev. 25 Source: PIC24FJ64GA004.bsd

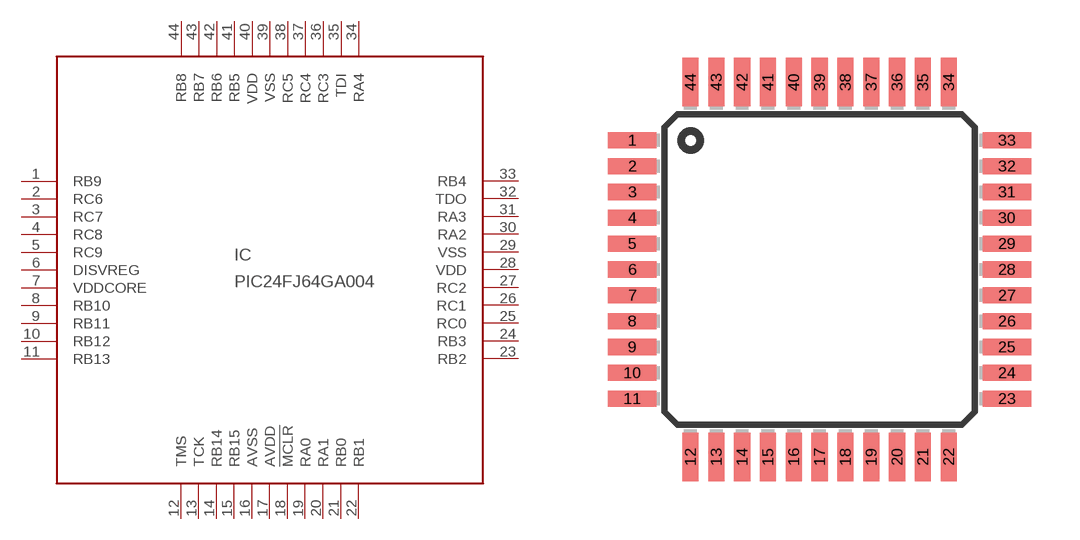
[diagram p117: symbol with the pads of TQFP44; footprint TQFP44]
Designator prefix IC

## PIC24FJ64GA004 (MPN: PIC24FJ64GA004-E/PT; OC_FARNELL: 1332299; OC_NEWARK: 98M1927)  [TQFP44]
1  RB9
2  RC6
3  RC7
4  RC8
5  RC9
6  DISVREG  pas
7  VDDCORE  pwr
8  RB10
9  RB11
10  RB12
11  RB13
12  TMS  in
13  TCK  in
14  RB14
15  RB15
16  AVSS  pwr
17  AVDD  pwr
18  !MCLR
19  RA0
20  RA1
21  RB0
22  RB1
23  RB2
24  RB3
25  RC0
26  RC1
27  RC2
28  VDD  pwr
29  VSS  pwr
30  RA2
31  RA3
32  TDO  out
33  RB4
34  RA4
35  TDI  in
36  RC3
37  RC4
38  RC5
39  VSS  pwr
40  VDD  pwr
41  RB5
42  RB6
43  RB7
44  RB8

## Footprint TQFP44 (pad centres in mm)
Thin Quad Flat Pack package type TQ
smd 1.5 x 0.5: 1 -5.8,4; 2 -5.8,3.2; 3 -5.8,2.4; 4 -5.8,1.6; 5 -5.8,0.8; 6 -5.8,0; 7 -5.8,-0.8; 8 -5.8,-1.6; 9 -5.8,-2.4; 10 -5.8,-3.2; 11 -5.8,-4; 23 5.8,-4; 24 5.8,-3.2; 25 5.8,-2.4; 26 5.8,-1.6; 27 5.8,-0.8; 28 5.8,0; 29 5.8,0.8; 30 5.8,1.6; 31 5.8,2.4; 32 5.8,3.2; 33 5.8,4
smd 0.5 x 1.5: 12 -4,-5.8; 13 -3.2,-5.8; 14 -2.4,-5.8; 15 -1.6,-5.8; 16 -0.8,-5.8; 17 0,-5.8; 18 0.8,-5.8; 19 1.6,-5.8; 20 2.4,-5.8; 21 3.2,-5.8; 22 4,-5.8; 34 4,5.8; 35 3.2,5.8; 36 2.4,5.8; 37 1.6,5.8; 38 0.8,5.8; 39 0,5.8; 40 -0.8,5.8; 41 -1.6,5.8; 42 -2.4,5.8; 43 -3.2,5.8; 44 -4,5.8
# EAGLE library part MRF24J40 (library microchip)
IEEE 802.15.4? 2.4 GHz RF Transceiver Source: http://ww1.microchip.com/downloads/en/DeviceDoc/39776a.pdf

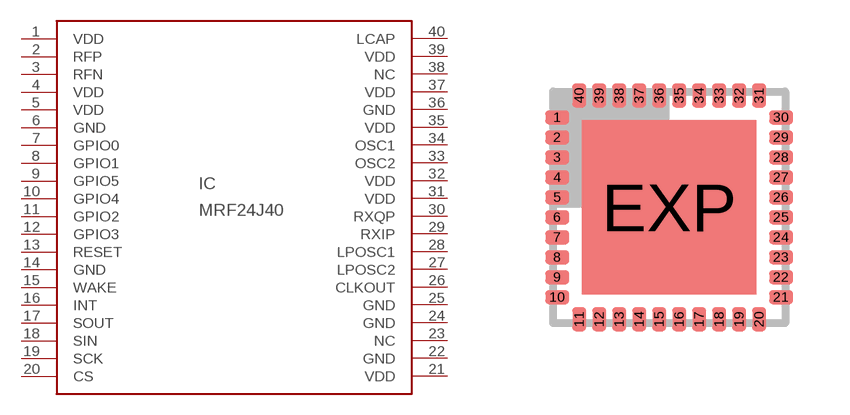
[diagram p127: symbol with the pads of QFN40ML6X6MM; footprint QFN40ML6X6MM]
Designator prefix IC

## MRF24J40 (MPN: MRF24J40-I/ML; OC_FARNELL: 1436019; OC_NEWARK: 17M0699)  [QFN40ML6X6MM]
1  VDD  pwr
2  RFP
3  RFN
4  VDD  pwr
5  VDD  pwr
6  GND  pwr
7  GPIO0  in
8  GPIO1  in
9  GPIO5  in
10  GPIO4  in
11  GPIO2  in
12  GPIO3  in
13  RESET  in
14  GND  pwr
15  WAKE  in
16  INT  out
17  SOUT  in
18  SIN  in
19  SCK  in
20  CS  in
21  VDD  pwr
22  GND  pwr
23  NC  nc
24  GND  pwr
25  GND  pwr
26  CLKOUT  in
27  LPOSC2  in
28  LPOSC1  in
29  RXIP  out
30  RXQP  out
31  VDD  pwr
32  VDD  pwr
33  OSC2  in
34  OSC1  in
35  VDD  pwr
36  GND  pwr
37  VDD  pwr
38  NC  nc
39  VDD  pwr
40  LCAP  nc

## Footprint QFN40ML6X6MM (pad centres in mm)
40-Lead Plastic Quad Flat 6x6x0.9 mm Body [QFN] With 0.40 mm Contact Length Source: http://ww1.microchip.com/downloads/en/DeviceDoc/39776a.pdf
smd 0.6 x 0.35: 1 -2.8,2.25; 2 -2.8,1.75; 3 -2.8,1.25; 4 -2.8,0.75; 5 -2.8,0.25; 6 -2.8,-0.25; 7 -2.8,-0.75; 8 -2.8,-1.25; 9 -2.8,-1.75; 10 -2.8,-2.25; 21 2.8,-2.25; 22 2.8,-1.75; 23 2.8,-1.25; 24 2.8,-0.75; 25 2.8,-0.25; 26 2.8,0.25; 27 2.8,0.75; 28 2.8,1.25; 29 2.8,1.75; 30 2.8,2.25
smd 0.35 x 0.6: 11 -2.25,-2.8; 12 -1.75,-2.8; 13 -1.25,-2.8; 14 -0.75,-2.8; 15 -0.25,-2.8; 16 0.25,-2.8; 17 0.75,-2.8; 18 1.25,-2.8; 19 1.75,-2.8; 20 2.25,-2.8; 31 2.25,2.8; 32 1.75,2.8; 33 1.25,2.8; 34 0.75,2.8; 35 0.25,2.8; 36 -0.25,2.8; 37 -0.75,2.8; 38 -1.25,2.8; 39 -1.75,2.8; 40 -2.25,2.8
smd 4.37 x 4.37: EXP 0,0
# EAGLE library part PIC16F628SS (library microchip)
FLASH-Based 8-Bit CMOS Microcontroller Source: http://ww1.microchip.com/downloads/en/DeviceDoc/40300C.pdf

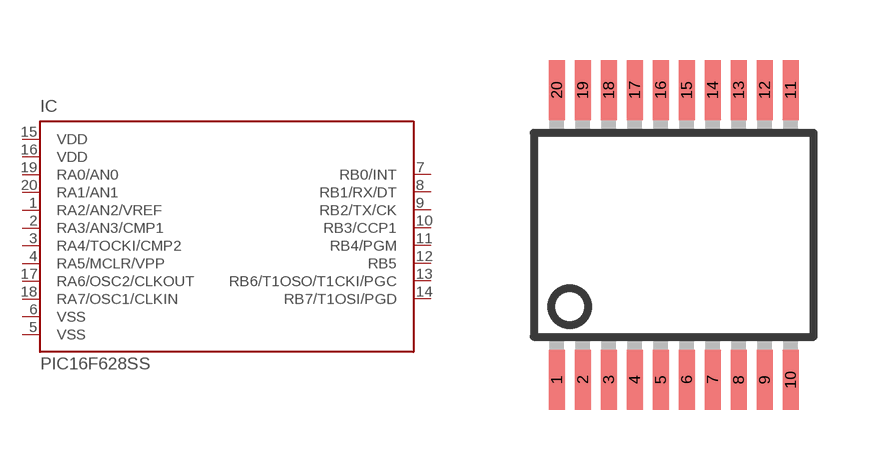
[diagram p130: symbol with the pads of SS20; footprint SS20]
Designator prefix IC

## PIC16F628SS (MF: MICROCHIP; MPN: PIC16F628-20I/SS; OC_FARNELL: 1084266; OC_NEWARK: 23C4987)  [SS20]
1  RA2/AN2/VREF
2  RA3/AN3/CMP1
3  RA4/TOCKI/CMP2
4  RA5/MCLR/VPP
5  VSS  pwr
6  VSS  pwr
7  RB0/INT
8  RB1/RX/DT
9  RB2/TX/CK
10  RB3/CCP1
11  RB4/PGM
12  RB5
13  RB6/T1OSO/T1CKI/PGC
14  RB7/T1OSI/PGD
15  VDD  pwr
16  VDD  pwr
17  RA6/OSC2/CLKOUT
18  RA7/OSC1/CLKIN
19  RA0/AN0
20  RA1/AN1

## Footprint SS20 (pad centres in mm)
20-Lead Plastic Shrink Small Outline K04-072 (SS) - 5.30 mm Source: http://ww1.microchip.com/downloads/en/DeviceDoc/40300C.pdf
smd 0.4 x 1.5: 1 -2.925,-3.625; 2 -2.275,-3.625; 3 -1.625,-3.625; 4 -0.975,-3.625; 5 -0.325,-3.625; 6 0.325,-3.625; 7 0.975,-3.625; 8 1.625,-3.625; 9 2.275,-3.625; 10 2.925,-3.625; 11 2.925,3.625; 12 2.275,3.625; 13 1.625,3.625; 14 0.975,3.625; 15 0.325,3.625; 16 -0.325,3.625; 17 -0.975,3.625; 18 -1.625,3.625; 19 -2.275,3.625; 20 -2.925,3.625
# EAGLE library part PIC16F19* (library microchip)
Flash-Based, 8-Bit CMOS Microcontrollers wtih LCD Driver and nanoWatt XLP Technology Auto generated by make-symbol-device-package-bsdl.ulp Rev. 33 Source: http://ww1.microchip.com/downloads/en/DeviceDoc/41364D.pdf

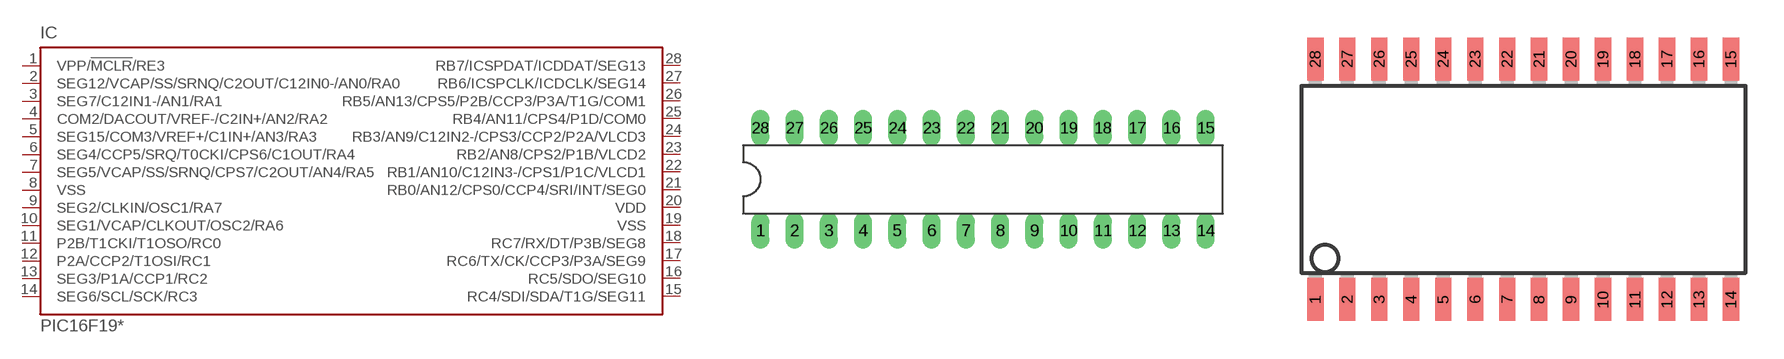
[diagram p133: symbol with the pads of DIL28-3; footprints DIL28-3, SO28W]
Designator prefix IC

## PIC16F1933SP (MPN: PIC16F1933-I/SP; OC_FARNELL: 1755814; OC_NEWARK: 08R1938), PIC16F1936SP (MPN: PIC16F1936-I/SP; OC_FARNELL: 1755822; OC_NEWARK: 45P4765), PIC16F1938SP (MPN: PIC16F1938-I/SP; OC_FARNELL: 1755829; OC_NEWARK: 08R1949)  [DIL28-3]
1  VPP/!MCLR!/RE3  in
2  SEG12/VCAP/SS/SRNQ/C2OUT/C12IN0-/AN0/RA0
3  SEG7/C12IN1-/AN1/RA1
4  COM2/DACOUT/VREF-/C2IN+/AN2/RA2
5  SEG15/COM3/VREF+/C1IN+/AN3/RA3
6  SEG4/CCP5/SRQ/T0CKI/CPS6/C1OUT/RA4
7  SEG5/VCAP/SS/SRNQ/CPS7/C2OUT/AN4/RA5
8  VSS  pwr
9  SEG2/CLKIN/OSC1/RA7
10  SEG1/VCAP/CLKOUT/OSC2/RA6
11  P2B/T1CKI/T1OSO/RC0
12  P2A/CCP2/T1OSI/RC1
13  SEG3/P1A/CCP1/RC2
14  SEG6/SCL/SCK/RC3
15  RC4/SDI/SDA/T1G/SEG11
16  RC5/SDO/SEG10
17  RC6/TX/CK/CCP3/P3A/SEG9
18  RC7/RX/DT/P3B/SEG8
19  VSS  pwr
20  VDD  pwr
21  RB0/AN12/CPS0/CCP4/SRI/INT/SEG0
22  RB1/AN10/C12IN3-/CPS1/P1C/VLCD1
23  RB2/AN8/CPS2/P1B/VLCD2
24  RB3/AN9/C12IN2-/CPS3/CCP2/P2A/VLCD3
25  RB4/AN11/CPS4/P1D/COM0
26  RB5/AN13/CPS5/P2B/CCP3/P3A/T1G/COM1
27  RB6/ICSPCLK/ICDCLK/SEG14
28  RB7/ICSPDAT/ICDDAT/SEG13

## PIC16F1933SO (MPN: PIC16F1933-I/SO; OC_FARNELL: 1755812; OC_NEWARK: 08R1937), PIC16F1936SO (MPN: PIC16F1936-I/SO; OC_FARNELL: 1755819; OC_NEWARK: 34R4516), PIC16F1938SO (MPN: PIC16F1938-I/SO; OC_FARNELL: 1755828; OC_NEWARK: 08R1948)  [SO28W]
Pads as for DIL28-3

## PIC16F1933SS (MPN: PIC16F1933T-I/SS; OC_FARNELL: 1755815; OC_NEWARK: 08R1942), PIC16F1936SS (MPN: PIC16F1936-E/SS; OC_FARNELL: 1755823; OC_NEWARK: 45P4762), PIC16F1938SS (MPN: PIC16F1938-E/SS; OC_FARNELL: 1755830; OC_NEWARK: 08R1946)  [SSOP28]
Pads as for DIL28-3

## PIC16F1933QF (MPN: PIC16F1933-I/ML; OC_FARNELL: 1755812; OC_NEWARK: 08R1936), PIC16F1936QF (MPN: PIC16F1936-I/ML; OC_FARNELL: 1755819; OC_NEWARK: 34R4515), PIC16F1938QF (MPN: PIC16F1938-E/ML; OC_FARNELL: 1755827; OC_NEWARK: 08R1943)  [QFN28-ML_6X6MM]
1  COM2/DACOUT/VREF-/C2IN+/AN2/RA2
2  SEG15/COM3/VREF+/C1IN+/AN3/RA3
3  SEG4/CCP5/SRQ/T0CKI/CPS6/C1OUT/RA4
4  SEG5/VCAP/SS/SRNQ/CPS7/C2OUT/AN4/RA5
5  VSS  pwr
6  SEG2/CLKIN/OSC1/RA7
7  SEG1/VCAP/CLKOUT/OSC2/RA6
8  P2B/T1CKI/T1OSO/RC0
9  P2A/CCP2/T1OSI/RC1
10  SEG3/P1A/CCP1/RC2
11  SEG6/SCL/SCK/RC3
12  RC4/SDI/SDA/T1G/SEG11
13  RC5/SDO/SEG10
14  RC6/TX/CK/CCP3/P3A/SEG9
15  RC7/RX/DT/P3B/SEG8
16  VSS  pwr
17  VDD  pwr
18  RB0/AN12/CPS0/CCP4/SRI/INT/SEG0
19  RB1/AN10/C12IN3-/CPS1/P1C/VLCD1
20  RB2/AN8/CPS2/P1B/VLCD2
21  RB3/AN9/C12IN2-/CPS3/CCP2/P2A/VLCD3
22  RB4/AN11/CPS4/P1D/COM0
23  RB5/AN13/CPS5/P2B/CCP3/P3A/T1G/COM1
24  RB6/ICSPCLK/ICDCLK/SEG14
25  RB7/ICSPDAT/ICDDAT/SEG13
26  VPP/!MCLR!/RE3  in
27  SEG12/VCAP/SS/SRNQ/C2OUT/C12IN0-/AN0/RA0
28  SEG7/C12IN1-/AN1/RA1

## Footprint DIL28-3 (pad centres in mm)
Dual In Line package type P
drill 0.813 long: 1 -16.51,-3.81; 2 -13.97,-3.81; 3 -11.43,-3.81; 4 -8.89,-3.81; 5 -6.35,-3.81; 6 -3.81,-3.81; 7 -1.27,-3.81; 8 1.27,-3.81; 9 3.81,-3.81; 10 6.35,-3.81; 11 8.89,-3.81; 12 11.43,-3.81; 13 13.97,-3.81; 14 16.51,-3.81; 15 16.51,3.81; 16 13.97,3.81; 17 11.43,3.81; 18 8.89,3.81; 19 6.35,3.81; 20 3.81,3.81; 21 1.27,3.81; 22 -1.27,3.81; 23 -3.81,3.81; 24 -6.35,3.81; 25 -8.89,3.81; 26 -11.43,3.81; 27 -13.97,3.81; 28 -16.51,3.81

## Footprint SO28W (pad centres in mm)
28-Lead Plastic Small Outline (SO) Wide, 300 mil Body (SOIC) Source: http://ww1.microchip.com/downloads/en/devicedoc/39632c.pdf
smd 0.65 x 1.7: 1 -7.62,-4.78; 2 -6.35,-4.78; 3 -5.08,-4.78; 4 -3.81,-4.78; 5 -2.54,-4.78; 6 -1.27,-4.78; 7 0,-4.78; 8 1.27,-4.78; 9 2.54,-4.78; 10 3.81,-4.78; 11 5.08,-4.78; 12 6.35,-4.78; 13 7.62,-4.78; 14 8.89,-4.78; 15 8.89,4.78; 16 7.62,4.78; 17 6.35,4.78; 18 5.08,4.78; 19 3.81,4.78; 20 2.54,4.78; 21 1.27,4.78; 22 0,4.78; 23 -1.27,4.78; 24 -2.54,4.78; 25 -3.81,4.78; 26 -5.08,4.78; 27 -6.35,4.78; 28 -7.62,4.78

## Footprint SSOP28 (pad centres in mm)
Shrink Small Outline Package package type SS
smd 0.4 x 1.5: 1 -4.225,-3.625; 2 -3.575,-3.625; 3 -2.925,-3.625; 4 -2.275,-3.625; 5 -1.625,-3.625; 6 -0.975,-3.625; 7 -0.325,-3.625; 8 0.325,-3.625; 9 0.975,-3.625; 10 1.625,-3.625; 11 2.275,-3.625; 12 2.925,-3.625; 13 3.575,-3.625; 14 4.225,-3.625; 15 4.225,3.625; 16 3.575,3.625; 17 2.925,3.625; 18 2.275,3.625; 19 1.625,3.625; 20 0.975,3.625; 21 0.325,3.625; 22 -0.325,3.625; 23 -0.975,3.625; 24 -1.625,3.625; 25 -2.275,3.625; 26 -2.925,3.625; 27 -3.575,3.625; 28 -4.225,3.625

## Footprint QFN28-ML_6X6MM (pad centres in mm)
QFN28-ML_6X6MM Source: http://www.microchip.com .. 39637a.pdf
smd 0.7 x 0.35: 1 -2.7,1.95; 2 -2.7,1.3; 3 -2.7,0.65; 4 -2.7,0; 5 -2.7,-0.65; 6 -2.7,-1.3; 7 -2.7,-1.95; 15 2.7,-1.95; 16 2.7,-1.3; 17 2.7,-0.65; 18 2.7,0; 19 2.7,0.65; 20 2.7,1.3; 21 2.7,1.95
smd 0.35 x 0.7: 8 -1.95,-2.7; 9 -1.3,-2.7; 10 -0.65,-2.7; 11 0,-2.7; 12 0.65,-2.7; 13 1.3,-2.7; 14 1.95,-2.7; 22 1.95,2.7; 23 1.3,2.7; 24 0.65,2.7; 25 0,2.7; 26 -0.65,2.7; 27 -1.3,2.7; 28 -1.95,2.7
smd 3.7 x 3.7: EXP 0,0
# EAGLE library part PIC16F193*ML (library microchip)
Flash-Based, 8-Bit CMOS Microcontrollers wtih LCD Driver and nanoWatt XLP Technology Source: http://ww1.microchip.com/downloads/en/DeviceDoc/41364D.pdf

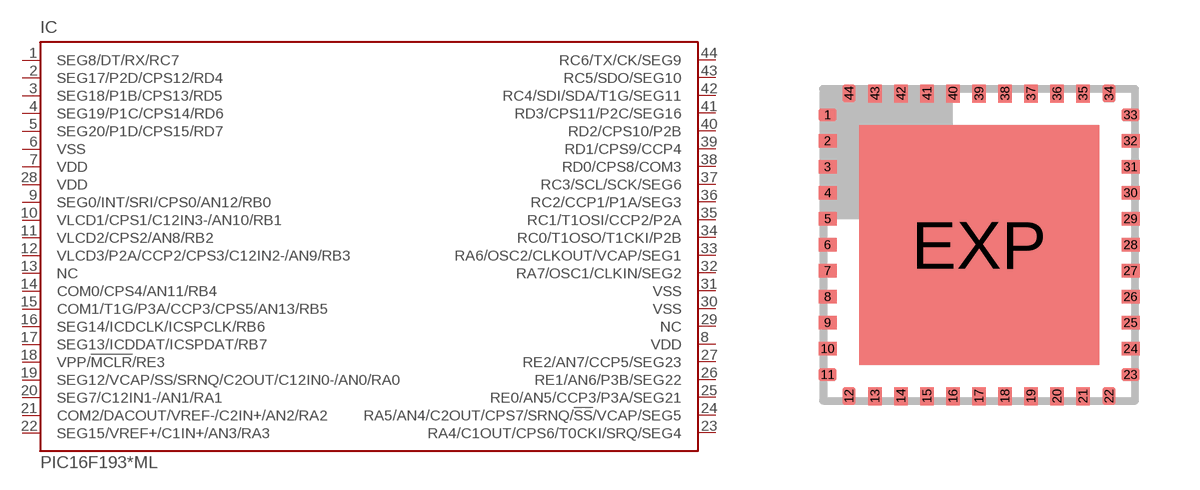
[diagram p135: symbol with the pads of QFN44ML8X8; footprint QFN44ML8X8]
Designator prefix IC

## PIC16F1934ML (MPN: PIC16F1934-I/ML; OC_FARNELL: 1755816; OC_NEWARK: 34R4512), PIC16F1937ML (MPN: PIC16F1937-I/ML; OC_FARNELL: 1755824; OC_NEWARK: 34R4519), PIC16F1939ML (MPN: PIC16F1939-I/ML; OC_FARNELL: 1755831; OC_NEWARK: 08R1957)  [QFN44ML8X8]
1  SEG8/DT/RX/RC7
2  SEG17/P2D/CPS12/RD4
3  SEG18/P1B/CPS13/RD5
4  SEG19/P1C/CPS14/RD6
5  SEG20/P1D/CPS15/RD7
6  VSS  pwr
7  VDD  pwr
8  VDD  pwr
9  SEG0/INT/SRI/CPS0/AN12/RB0
10  VLCD1/CPS1/C12IN3-/AN10/RB1
11  VLCD2/CPS2/AN8/RB2
12  VLCD3/P2A/CCP2/CPS3/C12IN2-/AN9/RB3
13  NC  nc
14  COM0/CPS4/AN11/RB4
15  COM1/T1G/P3A/CCP3/CPS5/AN13/RB5
16  SEG14/ICDCLK/ICSPCLK/RB6
17  SEG13/ICDDAT/ICSPDAT/RB7
18  VPP/!MCLR!/RE3  in
19  SEG12/VCAP/SS/SRNQ/C2OUT/C12IN0-/AN0/RA0
20  SEG7/C12IN1-/AN1/RA1
21  COM2/DACOUT/VREF-/C2IN+/AN2/RA2
22  SEG15/VREF+/C1IN+/AN3/RA3
23  RA4/C1OUT/CPS6/T0CKI/SRQ/SEG4
24  RA5/AN4/C2OUT/CPS7/SRNQ/!SS!/VCAP/SEG5
25  RE0/AN5/CCP3/P3A/SEG21
26  RE1/AN6/P3B/SEG22
27  RE2/AN7/CCP5/SEG23
28  VDD  pwr
29  NC  nc
30  VSS  pwr
31  VSS  pwr
32  RA7/OSC1/CLKIN/SEG2
33  RA6/OSC2/CLKOUT/VCAP/SEG1
34  RC0/T1OSO/T1CKI/P2B
35  RC1/T1OSI/CCP2/P2A
36  RC2/CCP1/P1A/SEG3
37  RC3/SCL/SCK/SEG6
38  RD0/CPS8/COM3
39  RD1/CPS9/CCP4
40  RD2/CPS10/P2B
41  RD3/CPS11/P2C/SEG16
42  RC4/SDI/SDA/T1G/SEG11
43  RC5/SDO/SEG10
44  RC6/TX/CK/SEG9

## Footprint QFN44ML8X8 (pad centres in mm)
44-Lead Plastic Quad Flat No Lead Package (ML) 8x8 mm Body (QFN) Source: http://ww1.microchip.com/downloads/en/devicedoc/39632c.pdf
smd 0.45 x 0.33: 1 -3.788,3.25; 2 -3.788,2.6; 3 -3.788,1.95; 4 -3.788,1.3; 5 -3.788,0.65; 6 -3.788,0; 7 -3.788,-0.65; 8 -3.788,-1.3; 9 -3.788,-1.95; 10 -3.788,-2.6; 11 -3.788,-3.25; 23 3.788,-3.25; 24 3.788,-2.6; 25 3.788,-1.95; 26 3.788,-1.3; 27 3.788,-0.65; 28 3.788,0; 29 3.788,0.65; 30 3.788,1.3; 31 3.788,1.95; 32 3.788,2.6; 33 3.788,3.25
smd 0.33 x 0.45: 12 -3.25,-3.788; 13 -2.6,-3.788; 14 -1.95,-3.788; 15 -1.3,-3.788; 16 -0.65,-3.788; 17 0,-3.788; 18 0.65,-3.788; 19 1.3,-3.788; 20 1.95,-3.788; 21 2.6,-3.788; 22 3.25,-3.788; 34 3.25,3.788; 35 2.6,3.788; 36 1.95,3.788; 37 1.3,3.788; 38 0.65,3.788; 39 0,3.788; 40 -0.65,3.788; 41 -1.3,3.788; 42 -1.95,3.788; 43 -2.6,3.788; 44 -3.25,3.788
smd 6 x 6: EXP 0,0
